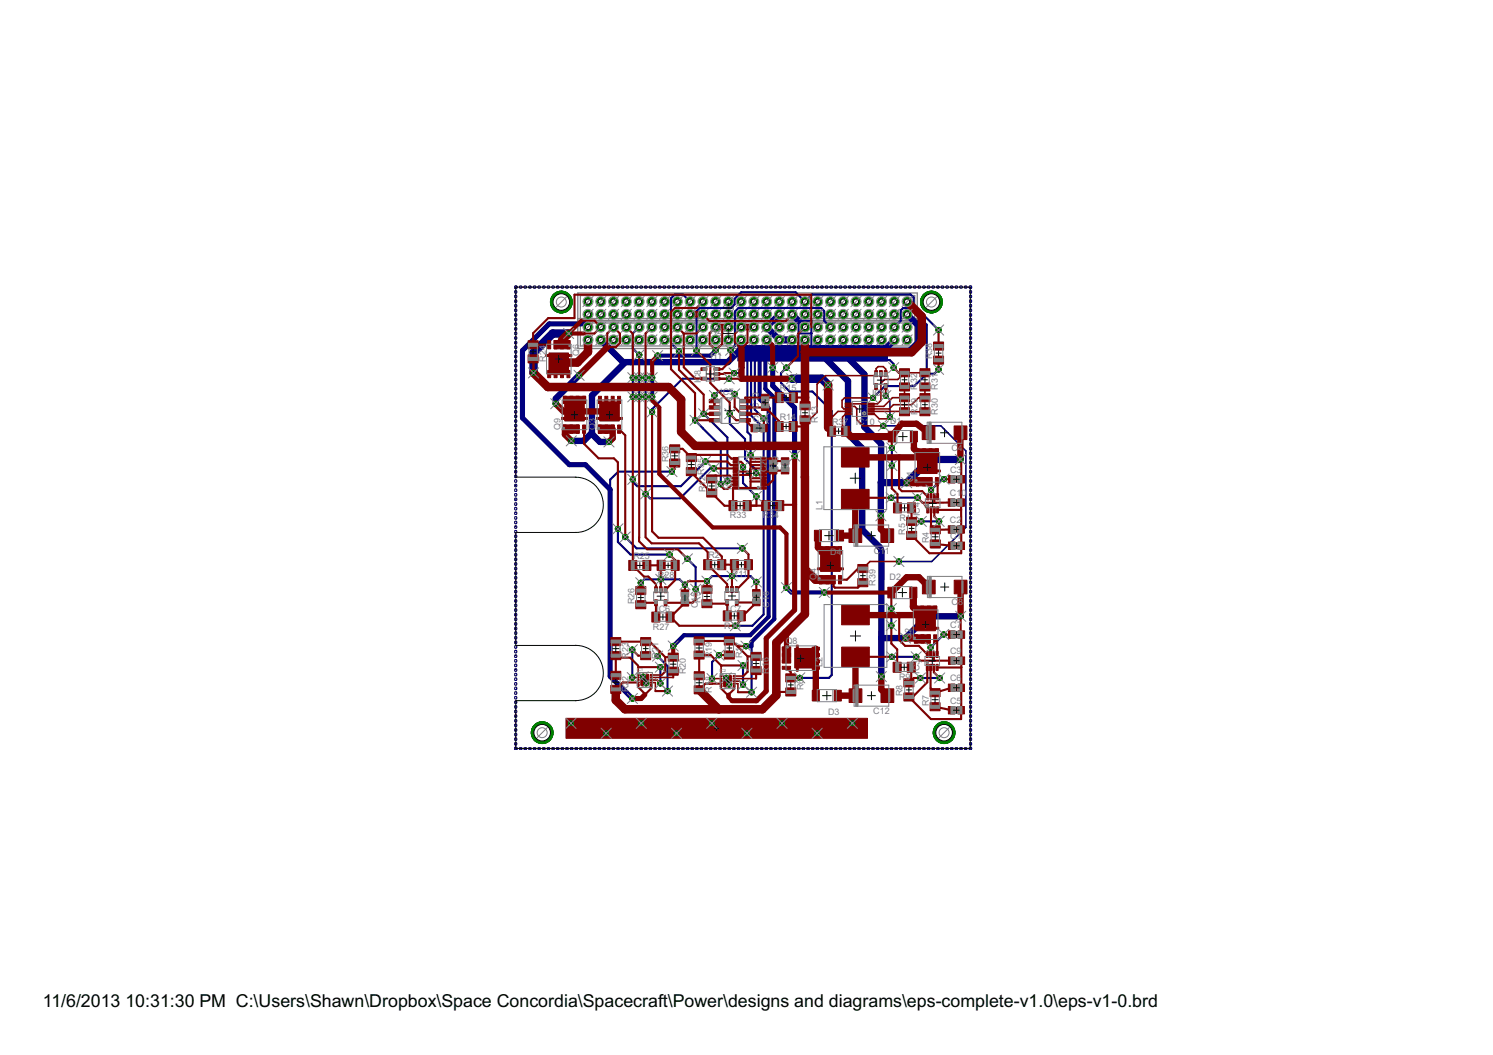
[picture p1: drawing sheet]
<svg xmlns="http://www.w3.org/2000/svg" width="297mm" height="210mm" viewBox="0 0 297 210" stroke-linecap="round" stroke-linejoin="round" font-family="sans-serif">
<defs><g id="words">
<g font-size="4">
<text x="8.5" y="200.4">11/6/2013</text>
<text x="25" y="200.4">10:31:30 PM C:\Users\Shawn\Dropbox\Space Concordia\Spacecraft\Power\designs and diagrams\eps-complete-v1.0\eps-v1-0.brd</text>
</g>
<g font-size="2" fill="#808080">
<text x="115.2" y="70.8" transform="rotate(-90 115.2 70.8)">Q6</text>
<text x="141.4" y="71.4">H1</text>
<text x="141.4" y="66.4">H2</text>
<text x="185.5" y="71.5" transform="rotate(-90 185.5 71.5)">R38</text>
<text x="108.6" y="72" transform="rotate(-90 108.6 72)">R24</text>
<text x="139.4" y="76.3" transform="rotate(-90 139.4 76.3)">IC8</text>
<text x="155.2" y="77.8">R15</text>
<text x="182.5" y="77.6" transform="rotate(-90 182.5 77.6)">R32</text>
<text x="186.6" y="77.6" transform="rotate(-90 186.6 77.6)">R31</text>
<text x="143.3" y="78.5">IC5</text>
<text x="149.7" y="83.9">C14</text>
<text x="151" y="81.3" transform="rotate(-90 151 81.3)">C1</text>
<text x="151" y="79" transform="rotate(-90 151 79)">3</text>
<text x="155.1" y="83.6">R14</text>
<text x="173.5" y="78.8">IC</text>
<text x="175.3" y="78.8">11</text>
<text x="182.5" y="82.5" transform="rotate(-90 182.5 82.5)">R29</text>
<text x="186.6" y="82.5" transform="rotate(-90 186.6 82.5)">R30</text>
<text x="111.5" y="85.5" transform="rotate(-90 111.5 85.5)">Q9</text>
<text x="118.5" y="85.5" transform="rotate(-90 118.5 85.5)">Q3</text>
<text x="162.7" y="84.1" transform="rotate(-90 162.7 84.1)">R13</text>
<text x="165.6" y="84.5">R3</text>
<text x="167.8" y="84.5">7</text>
<text x="170.3" y="84.5">IC</text>
<text x="172.1" y="84.5">10</text>
<text x="177.1" y="84.3">D1</text>
<text x="189.3" y="89.7">C4</text>
<text x="133" y="92" transform="rotate(-90 133 92)">R36</text>
<text x="152.5" y="94" transform="rotate(-90 152.5 94)">C20</text>
<text x="154.9" y="94" transform="rotate(-90 154.9 94)">C1</text>
<text x="154.9" y="91.7" transform="rotate(-90 154.9 91.7)">9</text>
<text x="181.7" y="96" transform="rotate(-90 181.7 96)">Q1</text>
<text x="189" y="94.1">C3</text>
<text x="140.3" y="98" transform="rotate(-90 140.3 98)">R12R35</text>
<text x="145.6" y="97.5" transform="rotate(-90 145.6 97.5)">IC9</text>
<text x="163.6" y="101.4" transform="rotate(-90 163.6 101.4)">L1</text>
<text x="189" y="98.7">C1</text>
<text x="191.3" y="98.7">0</text>
<text x="145.2" y="103.1">R33</text>
<text x="151.7" y="103.2">R</text>
<text x="153" y="103.2">34</text>
<text x="178.9" y="103.6">R1</text>
<text x="180.1" y="106.4" transform="rotate(-90 180.1 106.4)">R5</text>
<text x="183" y="102.7" transform="rotate(-90 183 102.7)">IC4</text>
<text x="189" y="104.1">C2</text>
<text x="189" y="107.3">C1</text>
<text x="126" y="111.2">R25</text>
<text x="140.9" y="111.1">R2</text>
<text x="165.2" y="110.4">D4</text>
<text x="173.8" y="110.1">C11</text>
<text x="184.8" y="108.1" transform="rotate(-90 184.8 108.1)">R4</text>
<text x="130.9" y="115">R28</text>
<text x="139.4" y="120" transform="rotate(-90 139.4 120)">R3</text>
<text x="145.6" y="114.9">R11</text>
<text x="162.4" y="115.5" transform="rotate(-90 162.4 115.5)">Q4</text>
<text x="174.2" y="116.5" transform="rotate(-90 174.2 116.5)">R39</text>
<text x="177" y="115.4">D2</text>
<text x="126.2" y="120.2" transform="rotate(-90 126.2 120.2)">R26</text>
<text x="129.9" y="125.3">R27</text>
<text x="130.6" y="121.8">I</text>
<text x="131.1" y="121.8">C6</text>
<text x="138.8" y="121" transform="rotate(-90 138.8 121)">C15</text>
<text x="144.1" y="125.1">R10</text>
<text x="144.8" y="121.7">I</text>
<text x="145.2" y="121.7">C7</text>
<text x="153" y="120.9" transform="rotate(-90 153 120.9)">C16</text>
<text x="189" y="125">C7</text>
<text x="189.3" y="120.4">C8</text>
<text x="125.1" y="131.1" transform="rotate(-90 125.1 131.1)">R23</text>
<text x="131" y="131.1" transform="rotate(-90 131 131.1)">R21</text>
<text x="141.6" y="130.9" transform="rotate(-90 141.6 130.9)">R19</text>
<text x="147.6" y="130.9" transform="rotate(-90 147.6 130.9)">R17</text>
<text x="156.3" y="128.2">Q8</text>
<text x="181.4" y="127.3" transform="rotate(-90 181.4 127.3)">Q2</text>
<text x="189" y="130.2">C9</text>
<text x="125.1" y="137.8" transform="rotate(-90 125.1 137.8)">R2</text>
<text x="125.1" y="135.5" transform="rotate(-90 125.1 135.5)">2</text>
<text x="136.5" y="134.2" transform="rotate(-90 136.5 134.2)">R20</text>
<text x="141.6" y="137.9" transform="rotate(-90 141.6 137.9)">R1</text>
<text x="141.6" y="135.6" transform="rotate(-90 141.6 135.6)">8</text>
<text x="153" y="134" transform="rotate(-90 153 134)">R16</text>
<text x="159.9" y="137.3" transform="rotate(-90 159.9 137.3)">R6</text>
<text x="163.7" y="132.8" transform="rotate(-90 163.7 132.8)">L2</text>
<text x="178.9" y="135.3">R9</text>
<text x="182.9" y="134" transform="rotate(-90 182.9 134)">IC3</text>
<text x="189" y="135.6">C6</text>
<text x="164.8" y="142.2">D3</text>
<text x="173.7" y="142">C12</text>
<text x="179.6" y="138.5" transform="rotate(-90 179.6 138.5)">R8</text>
<text x="184.8" y="140.5" transform="rotate(-90 184.8 140.5)">R7</text>
<text x="189" y="140">C5</text>
</g>
<g font-size="1" fill="#808080">
<text x="126.7" y="133.5">IC1</text>
<text x="143.2" y="133.8">IC2</text>
</g>
</g></defs>
<path d="M115 58.3h67.5v11h-67.5zM115.5 58.8h66.5v5h-66.5zM115 64.3h67.5M115 63.4h67.5M115.5 63.9h66.5v4.9h-66.5z" fill="none" stroke="#808080" stroke-width=".25"/>
<path d="M146.8 68.7h29.8v3.1h-29.8z" fill="#000080" stroke="#000080" stroke-width=".2"/>
<g fill="none" stroke="#000080" stroke-width=".42">
<path d="M125.9 75.1v3.9M127.1 65.1l-1.2 1.2v3l1.3 1.3M127.2 75.1v3.9M128.4 75.1v3.9M137.3 60l-1.4-1.4h-1.7l-.7 .8v8.9l1.6 1.6M145.1 75.4h-9.3l-6.1 6v.6M146.2 78.4l-.6-.6h-2.6l-.9 .9M147.5 69.3v.4l.4 .4v3.1l-1 1h-.9M147.5 69.3l-.1 .2M148 71.1h1.4v11.6l2.5 2.5v37l-2.2 2.3h-3.4M148.7 71.1v14.9l.6 .6v4M149.5 68.9l.7 .7v11.9l1.7 1.7"/>
<path d="M150.2 69.7l2.1 .1M155.1 67.6h.1M156.5 73.2l-1.1 1v2l1.7 1.7h4.5l3.9 3.9v52.5l-.6 .6h-5.8M158.9 68.9v-5.1h2.5v5.1M158.9 66.4h2.5M161.4 66.3h.1M161.4 68.9h-13.5l-.4 .4M161.4 68.9l1.5 1.5h.4M163.4 70.3h5.1l.7 .8M165.2 65.1l-1.2-1.3v-1.9l-.6-.6h-16.5l-.7 .7v6.8l-.8 .9M172.4 69.8l1.9 1.8h2.7l.8 .8v.8M177.9 65.1l1.3-1.3v-2.1l.5-.4h1.4l3.3 3.3v9.8"/>
<path d="M184.4 74.4l-2.5 2.4h-5.9l-2.3 2.4M186.7 65.7l-4.9-5v-1.5l-.7-.6h-19.5l-1.5 1.4-1.8-1.9h-10.8l-1.3 1.4v1.1l-.8 .7h-6.2l-.6 .6v7.9M186.7 73.5l-.8 .9h-1.5M133.7 93.8h-10.7l-1.6 1.6v2M138.3 83.6l4.9 4.9M140 82.3l4.7 4.7v8.7M140.4 91.8l-4.9 4.9h-8.7l-.9-.8v-.5M142 93.2h-.7l-6 5.9h-6l-.9-.8M143.2 88.5l.2 .3v7.5M143.2 88.5v.1M145.2 82.3v2l3 3.1v3.9l2.3 2.2v.6M147.8 92.9v3.2l2.7 2.7"/>
<path d="M175.2 95.9l.1 .1M175.3 96v.1M176.6 95.9l-1.3 .1M177.3 99h.1M177.3 99h5.2M177.4 89.1v3.5M187.8 95.3l-.4 .1-2.2 2.1M122.9 105.2v2.6l2.6 2.5h7.7M124.4 106.8l2.2 2.3h21.1M127.5 116l.7-.7h7l1.1 1M136.8 111.2l1.6 1.6v4.4M140.7 115.6l1-1h7.6l1.2 1.2"/>
<path d="M175.2 102.6h.1M183.3 103.7h3.5M125.8 129.3v5.5M130.8 130.5l2 2v5M131.4 132.8v3.2M143 130.3l-1.3 1.4v3.3M147.8 132.4v3.8M149.5 128.6v9.1M177.3 121.1v3.4M177.4 130.7h4.9M183.1 134.9h3.8M187.7 126.2l-2.6 2.6"/>
</g>
<path d="M117 65.1l-.7-.7h-7l-5.4 5.3v13.4l9.4 9.4h3.2l4.9 4.9v37.2l4.4 4.4M153.7 73.1v3.7l4.4 4.3v9.6" fill="none" stroke="#000080" stroke-width="1"/>
<g fill="none" stroke="#000080" stroke-width="1.3">
<path d="M115.2 74.7l-4.6 4.6v1M119.5 67.6l4.5 4.5h20.8l2.6-2.6M124.4 72.1l-6.6 6.6v7.6l1.6 1.6h1.8M155.1 62.5l-2.6 2.6 2.6 2.5M157.6 62.5l1.3 1.3M162.7 67.6v1.5l1 1M163.3 70.4l5.4 5.4v10.6l2.8 2.8 .1 16.2 3.4 3.5 .3 .6v17.5M163.3 70.4h4.6l4.1 4.1v10.5l3.3 3.3v7.6M163.7 70.1l-.4 .3M164 69.8l-.3 .3M164.4 69.4l-.4 .4M167.8 67.6v1.8l.3 .4"/>
<path d="M172.8 67.6l.1 2.2M177.9 67.6l-2.1 2.2M180.5 62.5l2.2 2.3v3.3l-1.7 1.7h-17M117.8 86.1l-1.7 1.6h-2.4M175.2 95.9v6.7M175.3 127v7.6M191.1 122.6h-6.6l-4.4 4.4h-4.8"/>
</g>
<path d="M155.1 67.6h2.5M191.1 91.4h-6.1l-4.6 4.6h-5.1" fill="none" stroke="#000080" stroke-width="1.4"/>
<path d="M129.8 75.1v3.9M142.4 69.7l-1.1 1.1h-10.5M151.1 69.8v9.6l1.8 1.8v41.5l-3.7 3.7h-13.1l-2.2 2.1M152.3 69.8v7.6l1.8 1.7v44.1l-4.6 4.5v.9h-1.1M156.5 116.9l.9 1h6.6" fill="none" stroke="#000080" stroke-width=".83"/>
<path d="M125.5 72.1h.3M125.8 72.1h.1M176.2 78.7l.9 .8v3.5M175.7 84.7h11.5l5 5v15.2l-6.8 6.8h-6.6" fill="none" stroke="#000080" stroke-width=".32"/>
<path d="M113.1 66.4h-3.1l-3.8 3.8v4M157.5 75.4h6l1.3 1.2" fill="none" stroke="#000080" stroke-width="1.7"/>
<circle cx="117" cy="62.5" r=".76" fill="#008000" stroke="#008000" stroke-width=".2"/>
<circle cx="117" cy="62.5" r=".51" fill="#fff" stroke="#000" stroke-width=".2"/>
<circle cx="117" cy="60" r=".76" fill="#008000" stroke="#008000" stroke-width=".2"/>
<circle cx="117" cy="60" r=".51" fill="#fff" stroke="#000" stroke-width=".2"/>
<circle cx="119.5" cy="62.5" r=".76" fill="#008000" stroke="#008000" stroke-width=".2"/>
<circle cx="119.5" cy="62.5" r=".51" fill="#fff" stroke="#000" stroke-width=".2"/>
<circle cx="119.5" cy="60" r=".76" fill="#008000" stroke="#008000" stroke-width=".2"/>
<circle cx="119.5" cy="60" r=".51" fill="#fff" stroke="#000" stroke-width=".2"/>
<circle cx="122.1" cy="62.5" r=".76" fill="#008000" stroke="#008000" stroke-width=".2"/>
<circle cx="122.1" cy="62.5" r=".51" fill="#fff" stroke="#000" stroke-width=".2"/>
<circle cx="122.1" cy="60" r=".76" fill="#008000" stroke="#008000" stroke-width=".2"/>
<circle cx="122.1" cy="60" r=".51" fill="#fff" stroke="#000" stroke-width=".2"/>
<circle cx="124.6" cy="62.5" r=".76" fill="#008000" stroke="#008000" stroke-width=".2"/>
<circle cx="124.6" cy="62.5" r=".51" fill="#fff" stroke="#000" stroke-width=".2"/>
<circle cx="124.6" cy="60" r=".76" fill="#008000" stroke="#008000" stroke-width=".2"/>
<circle cx="124.6" cy="60" r=".51" fill="#fff" stroke="#000" stroke-width=".2"/>
<circle cx="127.1" cy="62.5" r=".76" fill="#008000" stroke="#008000" stroke-width=".2"/>
<circle cx="127.1" cy="62.5" r=".51" fill="#fff" stroke="#000" stroke-width=".2"/>
<circle cx="127.1" cy="60" r=".76" fill="#008000" stroke="#008000" stroke-width=".2"/>
<circle cx="127.1" cy="60" r=".51" fill="#fff" stroke="#000" stroke-width=".2"/>
<circle cx="129.7" cy="62.5" r=".76" fill="#008000" stroke="#008000" stroke-width=".2"/>
<circle cx="129.7" cy="62.5" r=".51" fill="#fff" stroke="#000" stroke-width=".2"/>
<circle cx="129.7" cy="60" r=".76" fill="#008000" stroke="#008000" stroke-width=".2"/>
<circle cx="129.7" cy="60" r=".51" fill="#fff" stroke="#000" stroke-width=".2"/>
<circle cx="132.2" cy="62.5" r=".76" fill="#008000" stroke="#008000" stroke-width=".2"/>
<circle cx="132.2" cy="62.5" r=".51" fill="#fff" stroke="#000" stroke-width=".2"/>
<circle cx="132.2" cy="60" r=".76" fill="#008000" stroke="#008000" stroke-width=".2"/>
<circle cx="132.2" cy="60" r=".51" fill="#fff" stroke="#000" stroke-width=".2"/>
<circle cx="134.8" cy="62.5" r=".76" fill="#008000" stroke="#008000" stroke-width=".2"/>
<circle cx="134.8" cy="62.5" r=".51" fill="#fff" stroke="#000" stroke-width=".2"/>
<circle cx="134.8" cy="60" r=".76" fill="#008000" stroke="#008000" stroke-width=".2"/>
<circle cx="134.8" cy="60" r=".51" fill="#fff" stroke="#000" stroke-width=".2"/>
<circle cx="137.3" cy="62.5" r=".76" fill="#008000" stroke="#008000" stroke-width=".2"/>
<circle cx="137.3" cy="62.5" r=".51" fill="#fff" stroke="#000" stroke-width=".2"/>
<circle cx="137.3" cy="60" r=".76" fill="#008000" stroke="#008000" stroke-width=".2"/>
<circle cx="137.3" cy="60" r=".51" fill="#fff" stroke="#000" stroke-width=".2"/>
<circle cx="139.8" cy="62.5" r=".76" fill="#008000" stroke="#008000" stroke-width=".2"/>
<circle cx="139.8" cy="62.5" r=".51" fill="#fff" stroke="#000" stroke-width=".2"/>
<circle cx="139.8" cy="60" r=".76" fill="#008000" stroke="#008000" stroke-width=".2"/>
<circle cx="139.8" cy="60" r=".51" fill="#fff" stroke="#000" stroke-width=".2"/>
<circle cx="142.4" cy="62.5" r=".76" fill="#008000" stroke="#008000" stroke-width=".2"/>
<circle cx="142.4" cy="62.5" r=".51" fill="#fff" stroke="#000" stroke-width=".2"/>
<circle cx="142.4" cy="60" r=".76" fill="#008000" stroke="#008000" stroke-width=".2"/>
<circle cx="142.4" cy="60" r=".51" fill="#fff" stroke="#000" stroke-width=".2"/>
<circle cx="144.9" cy="62.5" r=".76" fill="#008000" stroke="#008000" stroke-width=".2"/>
<circle cx="144.9" cy="62.5" r=".51" fill="#fff" stroke="#000" stroke-width=".2"/>
<circle cx="144.9" cy="60" r=".76" fill="#008000" stroke="#008000" stroke-width=".2"/>
<circle cx="144.9" cy="60" r=".51" fill="#fff" stroke="#000" stroke-width=".2"/>
<circle cx="147.5" cy="62.5" r=".76" fill="#008000" stroke="#008000" stroke-width=".2"/>
<circle cx="147.5" cy="62.5" r=".51" fill="#fff" stroke="#000" stroke-width=".2"/>
<circle cx="147.5" cy="60" r=".76" fill="#008000" stroke="#008000" stroke-width=".2"/>
<circle cx="147.5" cy="60" r=".51" fill="#fff" stroke="#000" stroke-width=".2"/>
<circle cx="150" cy="62.5" r=".76" fill="#008000" stroke="#008000" stroke-width=".2"/>
<circle cx="150" cy="62.5" r=".51" fill="#fff" stroke="#000" stroke-width=".2"/>
<circle cx="150" cy="60" r=".76" fill="#008000" stroke="#008000" stroke-width=".2"/>
<circle cx="150" cy="60" r=".51" fill="#fff" stroke="#000" stroke-width=".2"/>
<circle cx="152.5" cy="62.5" r=".76" fill="#008000" stroke="#008000" stroke-width=".2"/>
<circle cx="152.5" cy="62.5" r=".51" fill="#fff" stroke="#000" stroke-width=".2"/>
<circle cx="152.5" cy="60" r=".76" fill="#008000" stroke="#008000" stroke-width=".2"/>
<circle cx="152.5" cy="60" r=".51" fill="#fff" stroke="#000" stroke-width=".2"/>
<circle cx="155.1" cy="62.5" r=".76" fill="#008000" stroke="#008000" stroke-width=".2"/>
<circle cx="155.1" cy="62.5" r=".51" fill="#fff" stroke="#000" stroke-width=".2"/>
<circle cx="155.1" cy="60" r=".76" fill="#008000" stroke="#008000" stroke-width=".2"/>
<circle cx="155.1" cy="60" r=".51" fill="#fff" stroke="#000" stroke-width=".2"/>
<circle cx="157.6" cy="62.5" r=".76" fill="#008000" stroke="#008000" stroke-width=".2"/>
<circle cx="157.6" cy="62.5" r=".51" fill="#fff" stroke="#000" stroke-width=".2"/>
<circle cx="157.6" cy="60" r=".76" fill="#008000" stroke="#008000" stroke-width=".2"/>
<circle cx="157.6" cy="60" r=".51" fill="#fff" stroke="#000" stroke-width=".2"/>
<circle cx="160.1" cy="62.5" r=".76" fill="#008000" stroke="#008000" stroke-width=".2"/>
<circle cx="160.1" cy="62.5" r=".51" fill="#fff" stroke="#000" stroke-width=".2"/>
<circle cx="160.1" cy="60" r=".76" fill="#008000" stroke="#008000" stroke-width=".2"/>
<circle cx="160.1" cy="60" r=".51" fill="#fff" stroke="#000" stroke-width=".2"/>
<circle cx="162.7" cy="62.5" r=".76" fill="#008000" stroke="#008000" stroke-width=".2"/>
<circle cx="162.7" cy="62.5" r=".51" fill="#fff" stroke="#000" stroke-width=".2"/>
<circle cx="162.7" cy="60" r=".76" fill="#008000" stroke="#008000" stroke-width=".2"/>
<circle cx="162.7" cy="60" r=".51" fill="#fff" stroke="#000" stroke-width=".2"/>
<circle cx="165.2" cy="62.5" r=".76" fill="#008000" stroke="#008000" stroke-width=".2"/>
<circle cx="165.2" cy="62.5" r=".51" fill="#fff" stroke="#000" stroke-width=".2"/>
<circle cx="165.2" cy="60" r=".76" fill="#008000" stroke="#008000" stroke-width=".2"/>
<circle cx="165.2" cy="60" r=".51" fill="#fff" stroke="#000" stroke-width=".2"/>
<circle cx="167.8" cy="62.5" r=".76" fill="#008000" stroke="#008000" stroke-width=".2"/>
<circle cx="167.8" cy="62.5" r=".51" fill="#fff" stroke="#000" stroke-width=".2"/>
<circle cx="167.8" cy="60" r=".76" fill="#008000" stroke="#008000" stroke-width=".2"/>
<circle cx="167.8" cy="60" r=".51" fill="#fff" stroke="#000" stroke-width=".2"/>
<circle cx="170.3" cy="62.5" r=".76" fill="#008000" stroke="#008000" stroke-width=".2"/>
<circle cx="170.3" cy="62.5" r=".51" fill="#fff" stroke="#000" stroke-width=".2"/>
<circle cx="170.3" cy="60" r=".76" fill="#008000" stroke="#008000" stroke-width=".2"/>
<circle cx="170.3" cy="60" r=".51" fill="#fff" stroke="#000" stroke-width=".2"/>
<circle cx="172.8" cy="62.5" r=".76" fill="#008000" stroke="#008000" stroke-width=".2"/>
<circle cx="172.8" cy="62.5" r=".51" fill="#fff" stroke="#000" stroke-width=".2"/>
<circle cx="172.8" cy="60" r=".76" fill="#008000" stroke="#008000" stroke-width=".2"/>
<circle cx="172.8" cy="60" r=".51" fill="#fff" stroke="#000" stroke-width=".2"/>
<circle cx="175.4" cy="62.5" r=".76" fill="#008000" stroke="#008000" stroke-width=".2"/>
<circle cx="175.4" cy="62.5" r=".51" fill="#fff" stroke="#000" stroke-width=".2"/>
<circle cx="175.4" cy="60" r=".76" fill="#008000" stroke="#008000" stroke-width=".2"/>
<circle cx="175.4" cy="60" r=".51" fill="#fff" stroke="#000" stroke-width=".2"/>
<circle cx="177.9" cy="62.5" r=".76" fill="#008000" stroke="#008000" stroke-width=".2"/>
<circle cx="177.9" cy="62.5" r=".51" fill="#fff" stroke="#000" stroke-width=".2"/>
<circle cx="177.9" cy="60" r=".76" fill="#008000" stroke="#008000" stroke-width=".2"/>
<circle cx="177.9" cy="60" r=".51" fill="#fff" stroke="#000" stroke-width=".2"/>
<circle cx="180.5" cy="62.5" r=".76" fill="#008000" stroke="#008000" stroke-width=".2"/>
<circle cx="180.5" cy="62.5" r=".51" fill="#fff" stroke="#000" stroke-width=".2"/>
<circle cx="180.5" cy="60" r=".76" fill="#008000" stroke="#008000" stroke-width=".2"/>
<circle cx="180.5" cy="60" r=".51" fill="#fff" stroke="#000" stroke-width=".2"/>
<circle cx="117" cy="67.6" r=".76" fill="#008000" stroke="#008000" stroke-width=".2"/>
<circle cx="117" cy="67.6" r=".51" fill="#fff" stroke="#000" stroke-width=".2"/>
<circle cx="117" cy="65.1" r=".76" fill="#008000" stroke="#008000" stroke-width=".2"/>
<circle cx="117" cy="65.1" r=".51" fill="#fff" stroke="#000" stroke-width=".2"/>
<circle cx="119.5" cy="67.6" r=".76" fill="#008000" stroke="#008000" stroke-width=".2"/>
<circle cx="119.5" cy="67.6" r=".51" fill="#fff" stroke="#000" stroke-width=".2"/>
<circle cx="119.5" cy="65.1" r=".76" fill="#008000" stroke="#008000" stroke-width=".2"/>
<circle cx="119.5" cy="65.1" r=".51" fill="#fff" stroke="#000" stroke-width=".2"/>
<circle cx="122.1" cy="67.6" r=".76" fill="#008000" stroke="#008000" stroke-width=".2"/>
<circle cx="122.1" cy="67.6" r=".51" fill="#fff" stroke="#000" stroke-width=".2"/>
<circle cx="122.1" cy="65.1" r=".76" fill="#008000" stroke="#008000" stroke-width=".2"/>
<circle cx="122.1" cy="65.1" r=".51" fill="#fff" stroke="#000" stroke-width=".2"/>
<circle cx="124.6" cy="67.6" r=".76" fill="#008000" stroke="#008000" stroke-width=".2"/>
<circle cx="124.6" cy="67.6" r=".51" fill="#fff" stroke="#000" stroke-width=".2"/>
<circle cx="124.6" cy="65.1" r=".76" fill="#008000" stroke="#008000" stroke-width=".2"/>
<circle cx="124.6" cy="65.1" r=".51" fill="#fff" stroke="#000" stroke-width=".2"/>
<circle cx="127.1" cy="67.6" r=".76" fill="#008000" stroke="#008000" stroke-width=".2"/>
<circle cx="127.1" cy="67.6" r=".51" fill="#fff" stroke="#000" stroke-width=".2"/>
<circle cx="127.1" cy="65.1" r=".76" fill="#008000" stroke="#008000" stroke-width=".2"/>
<circle cx="127.1" cy="65.1" r=".51" fill="#fff" stroke="#000" stroke-width=".2"/>
<circle cx="129.7" cy="67.6" r=".76" fill="#008000" stroke="#008000" stroke-width=".2"/>
<circle cx="129.7" cy="67.6" r=".51" fill="#fff" stroke="#000" stroke-width=".2"/>
<circle cx="129.7" cy="65.1" r=".76" fill="#008000" stroke="#008000" stroke-width=".2"/>
<circle cx="129.7" cy="65.1" r=".51" fill="#fff" stroke="#000" stroke-width=".2"/>
<circle cx="132.2" cy="67.6" r=".76" fill="#008000" stroke="#008000" stroke-width=".2"/>
<circle cx="132.2" cy="67.6" r=".51" fill="#fff" stroke="#000" stroke-width=".2"/>
<circle cx="132.2" cy="65.1" r=".76" fill="#008000" stroke="#008000" stroke-width=".2"/>
<circle cx="132.2" cy="65.1" r=".51" fill="#fff" stroke="#000" stroke-width=".2"/>
<circle cx="134.8" cy="67.6" r=".76" fill="#008000" stroke="#008000" stroke-width=".2"/>
<circle cx="134.8" cy="67.6" r=".51" fill="#fff" stroke="#000" stroke-width=".2"/>
<circle cx="134.8" cy="65.1" r=".76" fill="#008000" stroke="#008000" stroke-width=".2"/>
<circle cx="134.8" cy="65.1" r=".51" fill="#fff" stroke="#000" stroke-width=".2"/>
<circle cx="137.3" cy="67.6" r=".76" fill="#008000" stroke="#008000" stroke-width=".2"/>
<circle cx="137.3" cy="67.6" r=".51" fill="#fff" stroke="#000" stroke-width=".2"/>
<circle cx="137.3" cy="65.1" r=".76" fill="#008000" stroke="#008000" stroke-width=".2"/>
<circle cx="137.3" cy="65.1" r=".51" fill="#fff" stroke="#000" stroke-width=".2"/>
<circle cx="139.8" cy="67.6" r=".76" fill="#008000" stroke="#008000" stroke-width=".2"/>
<circle cx="139.8" cy="67.6" r=".51" fill="#fff" stroke="#000" stroke-width=".2"/>
<circle cx="139.8" cy="65.1" r=".76" fill="#008000" stroke="#008000" stroke-width=".2"/>
<circle cx="139.8" cy="65.1" r=".51" fill="#fff" stroke="#000" stroke-width=".2"/>
<circle cx="142.4" cy="67.6" r=".76" fill="#008000" stroke="#008000" stroke-width=".2"/>
<circle cx="142.4" cy="67.6" r=".51" fill="#fff" stroke="#000" stroke-width=".2"/>
<circle cx="142.4" cy="65.1" r=".76" fill="#008000" stroke="#008000" stroke-width=".2"/>
<circle cx="142.4" cy="65.1" r=".51" fill="#fff" stroke="#000" stroke-width=".2"/>
<circle cx="144.9" cy="67.6" r=".76" fill="#008000" stroke="#008000" stroke-width=".2"/>
<circle cx="144.9" cy="67.6" r=".51" fill="#fff" stroke="#000" stroke-width=".2"/>
<circle cx="144.9" cy="65.1" r=".76" fill="#008000" stroke="#008000" stroke-width=".2"/>
<circle cx="144.9" cy="65.1" r=".51" fill="#fff" stroke="#000" stroke-width=".2"/>
<circle cx="147.4" cy="67.6" r=".76" fill="#008000" stroke="#008000" stroke-width=".2"/>
<circle cx="147.4" cy="67.6" r=".51" fill="#fff" stroke="#000" stroke-width=".2"/>
<circle cx="147.4" cy="65.1" r=".76" fill="#008000" stroke="#008000" stroke-width=".2"/>
<circle cx="147.4" cy="65.1" r=".51" fill="#fff" stroke="#000" stroke-width=".2"/>
<circle cx="150" cy="67.6" r=".76" fill="#008000" stroke="#008000" stroke-width=".2"/>
<circle cx="150" cy="67.6" r=".51" fill="#fff" stroke="#000" stroke-width=".2"/>
<circle cx="150" cy="65.1" r=".76" fill="#008000" stroke="#008000" stroke-width=".2"/>
<circle cx="150" cy="65.1" r=".51" fill="#fff" stroke="#000" stroke-width=".2"/>
<circle cx="152.5" cy="67.6" r=".76" fill="#008000" stroke="#008000" stroke-width=".2"/>
<circle cx="152.5" cy="67.6" r=".51" fill="#fff" stroke="#000" stroke-width=".2"/>
<circle cx="152.5" cy="65.1" r=".76" fill="#008000" stroke="#008000" stroke-width=".2"/>
<circle cx="152.5" cy="65.1" r=".51" fill="#fff" stroke="#000" stroke-width=".2"/>
<circle cx="155.1" cy="67.6" r=".76" fill="#008000" stroke="#008000" stroke-width=".2"/>
<circle cx="155.1" cy="67.6" r=".51" fill="#fff" stroke="#000" stroke-width=".2"/>
<circle cx="155.1" cy="65.1" r=".76" fill="#008000" stroke="#008000" stroke-width=".2"/>
<circle cx="155.1" cy="65.1" r=".51" fill="#fff" stroke="#000" stroke-width=".2"/>
<circle cx="157.6" cy="67.6" r=".76" fill="#008000" stroke="#008000" stroke-width=".2"/>
<circle cx="157.6" cy="67.6" r=".51" fill="#fff" stroke="#000" stroke-width=".2"/>
<circle cx="157.6" cy="65.1" r=".76" fill="#008000" stroke="#008000" stroke-width=".2"/>
<circle cx="157.6" cy="65.1" r=".51" fill="#fff" stroke="#000" stroke-width=".2"/>
<circle cx="160.1" cy="67.6" r=".76" fill="#008000" stroke="#008000" stroke-width=".2"/>
<circle cx="160.1" cy="67.6" r=".51" fill="#fff" stroke="#000" stroke-width=".2"/>
<circle cx="160.1" cy="65.1" r=".76" fill="#008000" stroke="#008000" stroke-width=".2"/>
<circle cx="160.1" cy="65.1" r=".51" fill="#fff" stroke="#000" stroke-width=".2"/>
<circle cx="162.7" cy="67.6" r=".76" fill="#008000" stroke="#008000" stroke-width=".2"/>
<circle cx="162.7" cy="67.6" r=".51" fill="#fff" stroke="#000" stroke-width=".2"/>
<circle cx="162.7" cy="65.1" r=".76" fill="#008000" stroke="#008000" stroke-width=".2"/>
<circle cx="162.7" cy="65.1" r=".51" fill="#fff" stroke="#000" stroke-width=".2"/>
<circle cx="165.2" cy="67.6" r=".76" fill="#008000" stroke="#008000" stroke-width=".2"/>
<circle cx="165.2" cy="67.6" r=".51" fill="#fff" stroke="#000" stroke-width=".2"/>
<circle cx="165.2" cy="65.1" r=".76" fill="#008000" stroke="#008000" stroke-width=".2"/>
<circle cx="165.2" cy="65.1" r=".51" fill="#fff" stroke="#000" stroke-width=".2"/>
<circle cx="167.8" cy="67.6" r=".76" fill="#008000" stroke="#008000" stroke-width=".2"/>
<circle cx="167.8" cy="67.6" r=".51" fill="#fff" stroke="#000" stroke-width=".2"/>
<circle cx="167.8" cy="65.1" r=".76" fill="#008000" stroke="#008000" stroke-width=".2"/>
<circle cx="167.8" cy="65.1" r=".51" fill="#fff" stroke="#000" stroke-width=".2"/>
<circle cx="170.3" cy="67.6" r=".76" fill="#008000" stroke="#008000" stroke-width=".2"/>
<circle cx="170.3" cy="67.6" r=".51" fill="#fff" stroke="#000" stroke-width=".2"/>
<circle cx="170.3" cy="65.1" r=".76" fill="#008000" stroke="#008000" stroke-width=".2"/>
<circle cx="170.3" cy="65.1" r=".51" fill="#fff" stroke="#000" stroke-width=".2"/>
<circle cx="172.8" cy="67.6" r=".76" fill="#008000" stroke="#008000" stroke-width=".2"/>
<circle cx="172.8" cy="67.6" r=".51" fill="#fff" stroke="#000" stroke-width=".2"/>
<circle cx="172.8" cy="65.1" r=".76" fill="#008000" stroke="#008000" stroke-width=".2"/>
<circle cx="172.8" cy="65.1" r=".51" fill="#fff" stroke="#000" stroke-width=".2"/>
<circle cx="175.4" cy="67.6" r=".76" fill="#008000" stroke="#008000" stroke-width=".2"/>
<circle cx="175.4" cy="67.6" r=".51" fill="#fff" stroke="#000" stroke-width=".2"/>
<circle cx="175.4" cy="65.1" r=".76" fill="#008000" stroke="#008000" stroke-width=".2"/>
<circle cx="175.4" cy="65.1" r=".51" fill="#fff" stroke="#000" stroke-width=".2"/>
<circle cx="177.9" cy="67.6" r=".76" fill="#008000" stroke="#008000" stroke-width=".2"/>
<circle cx="177.9" cy="67.6" r=".51" fill="#fff" stroke="#000" stroke-width=".2"/>
<circle cx="177.9" cy="65.1" r=".76" fill="#008000" stroke="#008000" stroke-width=".2"/>
<circle cx="177.9" cy="65.1" r=".51" fill="#fff" stroke="#000" stroke-width=".2"/>
<circle cx="180.5" cy="67.6" r=".76" fill="#008000" stroke="#008000" stroke-width=".2"/>
<circle cx="180.5" cy="67.6" r=".51" fill="#fff" stroke="#000" stroke-width=".2"/>
<circle cx="180.5" cy="65.1" r=".76" fill="#008000" stroke="#008000" stroke-width=".2"/>
<circle cx="180.5" cy="65.1" r=".51" fill="#fff" stroke="#000" stroke-width=".2"/>
<circle cx="186.8" cy="103.7" r=".51" fill="#008000" stroke="#008000" stroke-width=".2"/>
<circle cx="186.8" cy="103.7" r=".3" fill="#fff" stroke="#000" stroke-width=".2"/>
<circle cx="183.3" cy="103.7" r=".51" fill="#008000" stroke="#008000" stroke-width=".2"/>
<circle cx="183.3" cy="103.7" r=".3" fill="#fff" stroke="#000" stroke-width=".2"/>
<circle cx="185.1" cy="128.8" r=".51" fill="#008000" stroke="#008000" stroke-width=".2"/>
<circle cx="185.1" cy="128.8" r=".3" fill="#fff" stroke="#000" stroke-width=".2"/>
<circle cx="187.7" cy="126.2" r=".51" fill="#008000" stroke="#008000" stroke-width=".2"/>
<circle cx="187.7" cy="126.2" r=".3" fill="#fff" stroke="#000" stroke-width=".2"/>
<circle cx="186.9" cy="134.9" r=".51" fill="#008000" stroke="#008000" stroke-width=".2"/>
<circle cx="186.9" cy="134.9" r=".3" fill="#fff" stroke="#000" stroke-width=".2"/>
<circle cx="183.1" cy="134.9" r=".51" fill="#008000" stroke="#008000" stroke-width=".2"/>
<circle cx="183.1" cy="134.9" r=".3" fill="#fff" stroke="#000" stroke-width=".2"/>
<circle cx="177.4" cy="130.7" r=".51" fill="#008000" stroke="#008000" stroke-width=".2"/>
<circle cx="177.4" cy="130.7" r=".3" fill="#fff" stroke="#000" stroke-width=".2"/>
<circle cx="182.3" cy="130.7" r=".51" fill="#008000" stroke="#008000" stroke-width=".2"/>
<circle cx="182.3" cy="130.7" r=".3" fill="#fff" stroke="#000" stroke-width=".2"/>
<circle cx="156.5" cy="73.2" r=".51" fill="#008000" stroke="#008000" stroke-width=".2"/>
<circle cx="156.5" cy="73.2" r=".3" fill="#fff" stroke="#000" stroke-width=".2"/>
<circle cx="159.1" cy="134.9" r=".51" fill="#008000" stroke="#008000" stroke-width=".2"/>
<circle cx="159.1" cy="134.9" r=".3" fill="#fff" stroke="#000" stroke-width=".2"/>
<circle cx="145.4" cy="69.7" r=".51" fill="#008000" stroke="#008000" stroke-width=".2"/>
<circle cx="145.4" cy="69.7" r=".3" fill="#fff" stroke="#000" stroke-width=".2"/>
<circle cx="133.7" cy="93.8" r=".51" fill="#008000" stroke="#008000" stroke-width=".2"/>
<circle cx="133.7" cy="93.8" r=".3" fill="#fff" stroke="#000" stroke-width=".2"/>
<circle cx="125.8" cy="139" r=".51" fill="#008000" stroke="#008000" stroke-width=".2"/>
<circle cx="125.8" cy="139" r=".3" fill="#fff" stroke="#000" stroke-width=".2"/>
<circle cx="141.7" cy="135" r=".51" fill="#008000" stroke="#008000" stroke-width=".2"/>
<circle cx="141.7" cy="135" r=".3" fill="#fff" stroke="#000" stroke-width=".2"/>
<circle cx="143" cy="130.3" r=".51" fill="#008000" stroke="#008000" stroke-width=".2"/>
<circle cx="143" cy="130.3" r=".3" fill="#fff" stroke="#000" stroke-width=".2"/>
<circle cx="147.8" cy="136.2" r=".51" fill="#008000" stroke="#008000" stroke-width=".2"/>
<circle cx="147.8" cy="136.2" r=".3" fill="#fff" stroke="#000" stroke-width=".2"/>
<circle cx="147.8" cy="132.4" r=".51" fill="#008000" stroke="#008000" stroke-width=".2"/>
<circle cx="147.8" cy="132.4" r=".3" fill="#fff" stroke="#000" stroke-width=".2"/>
<circle cx="180.4" cy="96" r=".51" fill="#008000" stroke="#008000" stroke-width=".2"/>
<circle cx="180.4" cy="96" r=".3" fill="#fff" stroke="#000" stroke-width=".2"/>
<circle cx="175.3" cy="102.6" r=".51" fill="#008000" stroke="#008000" stroke-width=".2"/>
<circle cx="175.3" cy="102.6" r=".3" fill="#fff" stroke="#000" stroke-width=".2"/>
<circle cx="191.1" cy="91.4" r=".51" fill="#008000" stroke="#008000" stroke-width=".2"/>
<circle cx="191.1" cy="91.4" r=".3" fill="#fff" stroke="#000" stroke-width=".2"/>
<circle cx="151.9" cy="83.2" r=".51" fill="#008000" stroke="#008000" stroke-width=".2"/>
<circle cx="151.9" cy="83.2" r=".3" fill="#fff" stroke="#000" stroke-width=".2"/>
<circle cx="132.8" cy="137.5" r=".51" fill="#008000" stroke="#008000" stroke-width=".2"/>
<circle cx="132.8" cy="137.5" r=".3" fill="#fff" stroke="#000" stroke-width=".2"/>
<circle cx="130.8" cy="130.5" r=".51" fill="#008000" stroke="#008000" stroke-width=".2"/>
<circle cx="130.8" cy="130.5" r=".3" fill="#fff" stroke="#000" stroke-width=".2"/>
<circle cx="149.5" cy="137.7" r=".51" fill="#008000" stroke="#008000" stroke-width=".2"/>
<circle cx="149.5" cy="137.7" r=".3" fill="#fff" stroke="#000" stroke-width=".2"/>
<circle cx="148.4" cy="128.6" r=".51" fill="#008000" stroke="#008000" stroke-width=".2"/>
<circle cx="148.4" cy="128.6" r=".3" fill="#fff" stroke="#000" stroke-width=".2"/>
<circle cx="127.2" cy="70.6" r=".51" fill="#008000" stroke="#008000" stroke-width=".2"/>
<circle cx="127.2" cy="70.6" r=".3" fill="#fff" stroke="#000" stroke-width=".2"/>
<circle cx="127.2" cy="75.1" r=".51" fill="#008000" stroke="#008000" stroke-width=".2"/>
<circle cx="127.2" cy="75.1" r=".3" fill="#fff" stroke="#000" stroke-width=".2"/>
<circle cx="180.1" cy="127" r=".51" fill="#008000" stroke="#008000" stroke-width=".2"/>
<circle cx="180.1" cy="127" r=".3" fill="#fff" stroke="#000" stroke-width=".2"/>
<circle cx="191.1" cy="122.6" r=".51" fill="#008000" stroke="#008000" stroke-width=".2"/>
<circle cx="191.1" cy="122.6" r=".3" fill="#fff" stroke="#000" stroke-width=".2"/>
<circle cx="175.3" cy="134.6" r=".51" fill="#008000" stroke="#008000" stroke-width=".2"/>
<circle cx="175.3" cy="134.6" r=".3" fill="#fff" stroke="#000" stroke-width=".2"/>
<circle cx="133.9" cy="128.5" r=".51" fill="#008000" stroke="#008000" stroke-width=".2"/>
<circle cx="133.9" cy="128.5" r=".3" fill="#fff" stroke="#000" stroke-width=".2"/>
<circle cx="149.3" cy="90.6" r=".51" fill="#008000" stroke="#008000" stroke-width=".2"/>
<circle cx="149.3" cy="90.6" r=".3" fill="#fff" stroke="#000" stroke-width=".2"/>
<circle cx="127.2" cy="79" r=".51" fill="#008000" stroke="#008000" stroke-width=".2"/>
<circle cx="127.2" cy="79" r=".3" fill="#fff" stroke="#000" stroke-width=".2"/>
<circle cx="142.1" cy="78.7" r=".51" fill="#008000" stroke="#008000" stroke-width=".2"/>
<circle cx="142.1" cy="78.7" r=".3" fill="#fff" stroke="#000" stroke-width=".2"/>
<circle cx="146.2" cy="78.4" r=".51" fill="#008000" stroke="#008000" stroke-width=".2"/>
<circle cx="146.2" cy="78.4" r=".3" fill="#fff" stroke="#000" stroke-width=".2"/>
<circle cx="146" cy="74.2" r=".51" fill="#008000" stroke="#008000" stroke-width=".2"/>
<circle cx="146" cy="74.2" r=".3" fill="#fff" stroke="#000" stroke-width=".2"/>
<circle cx="146.3" cy="124.5" r=".51" fill="#008000" stroke="#008000" stroke-width=".2"/>
<circle cx="146.3" cy="124.5" r=".3" fill="#fff" stroke="#000" stroke-width=".2"/>
<circle cx="136.8" cy="111.2" r=".51" fill="#008000" stroke="#008000" stroke-width=".2"/>
<circle cx="136.8" cy="111.2" r=".3" fill="#fff" stroke="#000" stroke-width=".2"/>
<circle cx="138.4" cy="117.2" r=".51" fill="#008000" stroke="#008000" stroke-width=".2"/>
<circle cx="138.4" cy="117.2" r=".3" fill="#fff" stroke="#000" stroke-width=".2"/>
<circle cx="113.7" cy="87.7" r=".51" fill="#008000" stroke="#008000" stroke-width=".2"/>
<circle cx="113.7" cy="87.7" r=".3" fill="#fff" stroke="#000" stroke-width=".2"/>
<circle cx="121.2" cy="87.9" r=".51" fill="#008000" stroke="#008000" stroke-width=".2"/>
<circle cx="121.2" cy="87.9" r=".3" fill="#fff" stroke="#000" stroke-width=".2"/>
<circle cx="177.8" cy="73.2" r=".51" fill="#008000" stroke="#008000" stroke-width=".2"/>
<circle cx="177.8" cy="73.2" r=".3" fill="#fff" stroke="#000" stroke-width=".2"/>
<circle cx="125.8" cy="129.3" r=".51" fill="#008000" stroke="#008000" stroke-width=".2"/>
<circle cx="125.8" cy="129.3" r=".3" fill="#fff" stroke="#000" stroke-width=".2"/>
<circle cx="125.8" cy="134.8" r=".51" fill="#008000" stroke="#008000" stroke-width=".2"/>
<circle cx="125.8" cy="134.8" r=".3" fill="#fff" stroke="#000" stroke-width=".2"/>
<circle cx="131.4" cy="136" r=".51" fill="#008000" stroke="#008000" stroke-width=".2"/>
<circle cx="131.4" cy="136" r=".3" fill="#fff" stroke="#000" stroke-width=".2"/>
<circle cx="131.4" cy="132.7" r=".51" fill="#008000" stroke="#008000" stroke-width=".2"/>
<circle cx="131.4" cy="132.7" r=".3" fill="#fff" stroke="#000" stroke-width=".2"/>
<circle cx="153.7" cy="73.1" r=".51" fill="#008000" stroke="#008000" stroke-width=".2"/>
<circle cx="153.7" cy="73.1" r=".3" fill="#fff" stroke="#000" stroke-width=".2"/>
<circle cx="158.1" cy="90.7" r=".51" fill="#008000" stroke="#008000" stroke-width=".2"/>
<circle cx="158.1" cy="90.7" r=".3" fill="#fff" stroke="#000" stroke-width=".2"/>
<circle cx="142.4" cy="69.7" r=".51" fill="#008000" stroke="#008000" stroke-width=".2"/>
<circle cx="142.4" cy="69.7" r=".3" fill="#fff" stroke="#000" stroke-width=".2"/>
<circle cx="129.8" cy="75.1" r=".51" fill="#008000" stroke="#008000" stroke-width=".2"/>
<circle cx="129.8" cy="75.1" r=".3" fill="#fff" stroke="#000" stroke-width=".2"/>
<circle cx="129.8" cy="79" r=".51" fill="#008000" stroke="#008000" stroke-width=".2"/>
<circle cx="129.8" cy="79" r=".3" fill="#fff" stroke="#000" stroke-width=".2"/>
<circle cx="177.3" cy="121.1" r=".51" fill="#008000" stroke="#008000" stroke-width=".2"/>
<circle cx="177.3" cy="121.1" r=".3" fill="#fff" stroke="#000" stroke-width=".2"/>
<circle cx="177.3" cy="124.5" r=".51" fill="#008000" stroke="#008000" stroke-width=".2"/>
<circle cx="177.3" cy="124.5" r=".3" fill="#fff" stroke="#000" stroke-width=".2"/>
<circle cx="156.5" cy="116.9" r=".51" fill="#008000" stroke="#008000" stroke-width=".2"/>
<circle cx="156.5" cy="116.9" r=".3" fill="#fff" stroke="#000" stroke-width=".2"/>
<circle cx="164" cy="117.9" r=".51" fill="#008000" stroke="#008000" stroke-width=".2"/>
<circle cx="164" cy="117.9" r=".3" fill="#fff" stroke="#000" stroke-width=".2"/>
<circle cx="130.8" cy="70.8" r=".51" fill="#008000" stroke="#008000" stroke-width=".2"/>
<circle cx="130.8" cy="70.8" r=".3" fill="#fff" stroke="#000" stroke-width=".2"/>
<circle cx="157.5" cy="75.4" r=".51" fill="#008000" stroke="#008000" stroke-width=".2"/>
<circle cx="157.5" cy="75.4" r=".3" fill="#fff" stroke="#000" stroke-width=".2"/>
<circle cx="136.3" cy="116.3" r=".51" fill="#008000" stroke="#008000" stroke-width=".2"/>
<circle cx="136.3" cy="116.3" r=".3" fill="#fff" stroke="#000" stroke-width=".2"/>
<circle cx="150.5" cy="115.8" r=".51" fill="#008000" stroke="#008000" stroke-width=".2"/>
<circle cx="150.5" cy="115.8" r=".3" fill="#fff" stroke="#000" stroke-width=".2"/>
<circle cx="145.1" cy="75.4" r=".51" fill="#008000" stroke="#008000" stroke-width=".2"/>
<circle cx="145.1" cy="75.4" r=".3" fill="#fff" stroke="#000" stroke-width=".2"/>
<circle cx="145.6" cy="114.6" r=".51" fill="#008000" stroke="#008000" stroke-width=".2"/>
<circle cx="145.6" cy="114.6" r=".3" fill="#fff" stroke="#000" stroke-width=".2"/>
<circle cx="140.7" cy="115.6" r=".51" fill="#008000" stroke="#008000" stroke-width=".2"/>
<circle cx="140.7" cy="115.6" r=".3" fill="#fff" stroke="#000" stroke-width=".2"/>
<circle cx="131.5" cy="115.3" r=".51" fill="#008000" stroke="#008000" stroke-width=".2"/>
<circle cx="131.5" cy="115.3" r=".3" fill="#fff" stroke="#000" stroke-width=".2"/>
<circle cx="127.5" cy="116" r=".51" fill="#008000" stroke="#008000" stroke-width=".2"/>
<circle cx="127.5" cy="116" r=".3" fill="#fff" stroke="#000" stroke-width=".2"/>
<circle cx="129.7" cy="82" r=".51" fill="#008000" stroke="#008000" stroke-width=".2"/>
<circle cx="129.7" cy="82" r=".3" fill="#fff" stroke="#000" stroke-width=".2"/>
<circle cx="164.8" cy="76.6" r=".51" fill="#008000" stroke="#008000" stroke-width=".2"/>
<circle cx="164.8" cy="76.6" r=".3" fill="#fff" stroke="#000" stroke-width=".2"/>
<circle cx="135.1" cy="69.9" r=".51" fill="#008000" stroke="#008000" stroke-width=".2"/>
<circle cx="135.1" cy="69.9" r=".3" fill="#fff" stroke="#000" stroke-width=".2"/>
<circle cx="140" cy="82.3" r=".51" fill="#008000" stroke="#008000" stroke-width=".2"/>
<circle cx="140" cy="82.3" r=".3" fill="#fff" stroke="#000" stroke-width=".2"/>
<circle cx="144.7" cy="95.7" r=".51" fill="#008000" stroke="#008000" stroke-width=".2"/>
<circle cx="144.7" cy="95.7" r=".3" fill="#fff" stroke="#000" stroke-width=".2"/>
<circle cx="138.3" cy="83.6" r=".51" fill="#008000" stroke="#008000" stroke-width=".2"/>
<circle cx="138.3" cy="83.6" r=".3" fill="#fff" stroke="#000" stroke-width=".2"/>
<circle cx="143.4" cy="96.3" r=".51" fill="#008000" stroke="#008000" stroke-width=".2"/>
<circle cx="143.4" cy="96.3" r=".3" fill="#fff" stroke="#000" stroke-width=".2"/>
<circle cx="125.9" cy="75.1" r=".51" fill="#008000" stroke="#008000" stroke-width=".2"/>
<circle cx="125.9" cy="75.1" r=".3" fill="#fff" stroke="#000" stroke-width=".2"/>
<circle cx="125.9" cy="79" r=".51" fill="#008000" stroke="#008000" stroke-width=".2"/>
<circle cx="125.9" cy="79" r=".3" fill="#fff" stroke="#000" stroke-width=".2"/>
<circle cx="140.4" cy="91.8" r=".51" fill="#008000" stroke="#008000" stroke-width=".2"/>
<circle cx="140.4" cy="91.8" r=".3" fill="#fff" stroke="#000" stroke-width=".2"/>
<circle cx="125.9" cy="95.4" r=".51" fill="#008000" stroke="#008000" stroke-width=".2"/>
<circle cx="125.9" cy="95.4" r=".3" fill="#fff" stroke="#000" stroke-width=".2"/>
<circle cx="133.2" cy="110.3" r=".51" fill="#008000" stroke="#008000" stroke-width=".2"/>
<circle cx="133.2" cy="110.3" r=".3" fill="#fff" stroke="#000" stroke-width=".2"/>
<circle cx="122.9" cy="105.2" r=".51" fill="#008000" stroke="#008000" stroke-width=".2"/>
<circle cx="122.9" cy="105.2" r=".3" fill="#fff" stroke="#000" stroke-width=".2"/>
<circle cx="115.2" cy="74.7" r=".51" fill="#008000" stroke="#008000" stroke-width=".2"/>
<circle cx="115.2" cy="74.7" r=".3" fill="#fff" stroke="#000" stroke-width=".2"/>
<circle cx="110.6" cy="80.3" r=".51" fill="#008000" stroke="#008000" stroke-width=".2"/>
<circle cx="110.6" cy="80.3" r=".3" fill="#fff" stroke="#000" stroke-width=".2"/>
<circle cx="147.7" cy="109.1" r=".51" fill="#008000" stroke="#008000" stroke-width=".2"/>
<circle cx="147.7" cy="109.1" r=".3" fill="#fff" stroke="#000" stroke-width=".2"/>
<circle cx="124.4" cy="106.8" r=".51" fill="#008000" stroke="#008000" stroke-width=".2"/>
<circle cx="124.4" cy="106.8" r=".3" fill="#fff" stroke="#000" stroke-width=".2"/>
<circle cx="128.4" cy="75.1" r=".51" fill="#008000" stroke="#008000" stroke-width=".2"/>
<circle cx="128.4" cy="75.1" r=".3" fill="#fff" stroke="#000" stroke-width=".2"/>
<circle cx="128.4" cy="79" r=".51" fill="#008000" stroke="#008000" stroke-width=".2"/>
<circle cx="128.4" cy="79" r=".3" fill="#fff" stroke="#000" stroke-width=".2"/>
<circle cx="142" cy="93.2" r=".51" fill="#008000" stroke="#008000" stroke-width=".2"/>
<circle cx="142" cy="93.2" r=".3" fill="#fff" stroke="#000" stroke-width=".2"/>
<circle cx="128.4" cy="98.3" r=".51" fill="#008000" stroke="#008000" stroke-width=".2"/>
<circle cx="128.4" cy="98.3" r=".3" fill="#fff" stroke="#000" stroke-width=".2"/>
<circle cx="147.8" cy="92.9" r=".51" fill="#008000" stroke="#008000" stroke-width=".2"/>
<circle cx="147.8" cy="92.9" r=".3" fill="#fff" stroke="#000" stroke-width=".2"/>
<circle cx="150.5" cy="98.8" r=".51" fill="#008000" stroke="#008000" stroke-width=".2"/>
<circle cx="150.5" cy="98.8" r=".3" fill="#fff" stroke="#000" stroke-width=".2"/>
<circle cx="177.1" cy="83" r=".51" fill="#008000" stroke="#008000" stroke-width=".2"/>
<circle cx="177.1" cy="83" r=".3" fill="#fff" stroke="#000" stroke-width=".2"/>
<circle cx="176.2" cy="78.7" r=".51" fill="#008000" stroke="#008000" stroke-width=".2"/>
<circle cx="176.2" cy="78.7" r=".3" fill="#fff" stroke="#000" stroke-width=".2"/>
<circle cx="185.2" cy="97.5" r=".51" fill="#008000" stroke="#008000" stroke-width=".2"/>
<circle cx="185.2" cy="97.5" r=".3" fill="#fff" stroke="#000" stroke-width=".2"/>
<circle cx="187.8" cy="95.3" r=".51" fill="#008000" stroke="#008000" stroke-width=".2"/>
<circle cx="187.8" cy="95.3" r=".3" fill="#fff" stroke="#000" stroke-width=".2"/>
<circle cx="177.3" cy="99" r=".51" fill="#008000" stroke="#008000" stroke-width=".2"/>
<circle cx="177.3" cy="99" r=".3" fill="#fff" stroke="#000" stroke-width=".2"/>
<circle cx="182.5" cy="99" r=".51" fill="#008000" stroke="#008000" stroke-width=".2"/>
<circle cx="182.5" cy="99" r=".3" fill="#fff" stroke="#000" stroke-width=".2"/>
<circle cx="175.7" cy="84.7" r=".51" fill="#008000" stroke="#008000" stroke-width=".2"/>
<circle cx="175.7" cy="84.7" r=".3" fill="#fff" stroke="#000" stroke-width=".2"/>
<circle cx="178.8" cy="111.7" r=".51" fill="#008000" stroke="#008000" stroke-width=".2"/>
<circle cx="178.8" cy="111.7" r=".3" fill="#fff" stroke="#000" stroke-width=".2"/>
<circle cx="138.6" cy="69.8" r=".51" fill="#008000" stroke="#008000" stroke-width=".2"/>
<circle cx="138.6" cy="69.8" r=".3" fill="#fff" stroke="#000" stroke-width=".2"/>
<circle cx="145.2" cy="82.3" r=".51" fill="#008000" stroke="#008000" stroke-width=".2"/>
<circle cx="145.2" cy="82.3" r=".3" fill="#fff" stroke="#000" stroke-width=".2"/>
<circle cx="150.5" cy="94.1" r=".51" fill="#008000" stroke="#008000" stroke-width=".2"/>
<circle cx="150.5" cy="94.1" r=".3" fill="#fff" stroke="#000" stroke-width=".2"/>
<circle cx="186.7" cy="65.7" r=".51" fill="#008000" stroke="#008000" stroke-width=".2"/>
<circle cx="186.7" cy="65.7" r=".3" fill="#fff" stroke="#000" stroke-width=".2"/>
<circle cx="177.4" cy="89.1" r=".51" fill="#008000" stroke="#008000" stroke-width=".2"/>
<circle cx="177.4" cy="89.1" r=".3" fill="#fff" stroke="#000" stroke-width=".2"/>
<circle cx="177.4" cy="92.6" r=".51" fill="#008000" stroke="#008000" stroke-width=".2"/>
<circle cx="177.4" cy="92.6" r=".3" fill="#fff" stroke="#000" stroke-width=".2"/>
<circle cx="106.2" cy="74.2" r=".51" fill="#008000" stroke="#008000" stroke-width=".2"/>
<circle cx="106.2" cy="74.2" r=".3" fill="#fff" stroke="#000" stroke-width=".2"/>
<circle cx="113.1" cy="66.4" r=".51" fill="#008000" stroke="#008000" stroke-width=".2"/>
<circle cx="113.1" cy="66.4" r=".3" fill="#fff" stroke="#000" stroke-width=".2"/>
<circle cx="173.7" cy="79.2" r=".51" fill="#008000" stroke="#008000" stroke-width=".2"/>
<circle cx="173.7" cy="79.2" r=".3" fill="#fff" stroke="#000" stroke-width=".2"/>
<circle cx="186.7" cy="73.5" r=".51" fill="#008000" stroke="#008000" stroke-width=".2"/>
<circle cx="186.7" cy="73.5" r=".3" fill="#fff" stroke="#000" stroke-width=".2"/>
<circle cx="185.3" cy="60.1" r="2.16" fill="#008000" stroke="#008000" stroke-width=".2"/>
<circle cx="185.3" cy="60.1" r="1.65" fill="#fff" stroke="#000" stroke-width=".2"/>
<circle cx="111.7" cy="60.1" r="2.16" fill="#008000" stroke="#008000" stroke-width=".2"/>
<circle cx="111.7" cy="60.1" r="1.65" fill="#fff" stroke="#000" stroke-width=".2"/>
<circle cx="107.9" cy="145.8" r="2.16" fill="#008000" stroke="#008000" stroke-width=".2"/>
<circle cx="107.9" cy="145.8" r="1.65" fill="#fff" stroke="#000" stroke-width=".2"/>
<circle cx="187.8" cy="145.8" r="2.16" fill="#008000" stroke="#008000" stroke-width=".2"/>
<circle cx="187.8" cy="145.8" r="1.65" fill="#fff" stroke="#000" stroke-width=".2"/>
<circle cx="113.6" cy="143.9" r=".51" fill="#008000" stroke="#008000" stroke-width=".2"/>
<circle cx="113.6" cy="143.9" r=".3" fill="#fff" stroke="#000" stroke-width=".2"/>
<circle cx="120.6" cy="145.9" r=".51" fill="#008000" stroke="#008000" stroke-width=".2"/>
<circle cx="120.6" cy="145.9" r=".3" fill="#fff" stroke="#000" stroke-width=".2"/>
<circle cx="127.6" cy="143.9" r=".51" fill="#008000" stroke="#008000" stroke-width=".2"/>
<circle cx="127.6" cy="143.9" r=".3" fill="#fff" stroke="#000" stroke-width=".2"/>
<circle cx="134.6" cy="145.9" r=".51" fill="#008000" stroke="#008000" stroke-width=".2"/>
<circle cx="134.6" cy="145.9" r=".3" fill="#fff" stroke="#000" stroke-width=".2"/>
<circle cx="141.6" cy="143.9" r=".51" fill="#008000" stroke="#008000" stroke-width=".2"/>
<circle cx="141.6" cy="143.9" r=".3" fill="#fff" stroke="#000" stroke-width=".2"/>
<circle cx="148.6" cy="145.9" r=".51" fill="#008000" stroke="#008000" stroke-width=".2"/>
<circle cx="148.6" cy="145.9" r=".3" fill="#fff" stroke="#000" stroke-width=".2"/>
<circle cx="155.6" cy="143.9" r=".51" fill="#008000" stroke="#008000" stroke-width=".2"/>
<circle cx="155.6" cy="143.9" r=".3" fill="#fff" stroke="#000" stroke-width=".2"/>
<circle cx="162.6" cy="145.9" r=".51" fill="#008000" stroke="#008000" stroke-width=".2"/>
<circle cx="162.6" cy="145.9" r=".3" fill="#fff" stroke="#000" stroke-width=".2"/>
<circle cx="169.6" cy="143.9" r=".51" fill="#008000" stroke="#008000" stroke-width=".2"/>
<circle cx="169.6" cy="143.9" r=".3" fill="#fff" stroke="#000" stroke-width=".2"/>
<circle cx="128.6" cy="135.9" r=".51" fill="#008000" stroke="#008000" stroke-width=".2"/>
<circle cx="128.6" cy="135.9" r=".3" fill="#fff" stroke="#000" stroke-width=".2"/>
<circle cx="128" cy="134.7" r=".51" fill="#008000" stroke="#008000" stroke-width=".2"/>
<circle cx="128" cy="134.7" r=".3" fill="#fff" stroke="#000" stroke-width=".2"/>
<circle cx="144.5" cy="134.9" r=".51" fill="#008000" stroke="#008000" stroke-width=".2"/>
<circle cx="144.5" cy="134.9" r=".3" fill="#fff" stroke="#000" stroke-width=".2"/>
<circle cx="145.1" cy="136.2" r=".51" fill="#008000" stroke="#008000" stroke-width=".2"/>
<circle cx="145.1" cy="136.2" r=".3" fill="#fff" stroke="#000" stroke-width=".2"/>
<g fill="#800000" stroke="#800000" stroke-width=".2">
<circle cx="102.6" cy="57.2" r=".25"/>
<circle cx="102.6" cy="58.1" r=".25"/>
<circle cx="102.6" cy="59" r=".25"/>
<circle cx="102.6" cy="59.9" r=".25"/>
<circle cx="102.6" cy="60.8" r=".25"/>
<circle cx="102.6" cy="61.7" r=".25"/>
<circle cx="102.6" cy="62.7" r=".25"/>
<circle cx="102.6" cy="63.6" r=".25"/>
<circle cx="102.6" cy="64.5" r=".25"/>
<circle cx="102.6" cy="65.4" r=".25"/>
<circle cx="102.6" cy="66.3" r=".25"/>
<circle cx="102.6" cy="67.2" r=".25"/>
<circle cx="102.6" cy="68.2" r=".25"/>
<circle cx="102.6" cy="69.1" r=".25"/>
<circle cx="102.6" cy="70" r=".25"/>
<circle cx="102.6" cy="70.9" r=".25"/>
<circle cx="102.6" cy="71.8" r=".25"/>
<circle cx="102.6" cy="72.7" r=".25"/>
<circle cx="102.6" cy="73.7" r=".25"/>
<circle cx="102.6" cy="74.6" r=".25"/>
<circle cx="102.6" cy="75.5" r=".24"/>
<circle cx="102.6" cy="76.4" r=".25"/>
<circle cx="102.6" cy="77.3" r=".25"/>
<circle cx="102.6" cy="78.3" r=".24"/>
<circle cx="102.6" cy="79.2" r=".25"/>
<circle cx="102.6" cy="80.1" r=".25"/>
<circle cx="102.6" cy="81" r=".24"/>
<circle cx="102.6" cy="81.9" r=".25"/>
<circle cx="102.6" cy="82.8" r=".25"/>
<circle cx="102.6" cy="83.8" r=".24"/>
<circle cx="102.6" cy="84.7" r=".25"/>
<circle cx="102.6" cy="85.6" r=".25"/>
<circle cx="102.6" cy="86.5" r=".25"/>
<circle cx="102.6" cy="87.4" r=".25"/>
<circle cx="102.6" cy="88.3" r=".25"/>
<circle cx="102.6" cy="89.3" r=".25"/>
<circle cx="102.6" cy="90.2" r=".25"/>
<circle cx="102.6" cy="91.1" r=".25"/>
<circle cx="102.6" cy="92" r=".25"/>
<circle cx="102.6" cy="92.9" r=".25"/>
<circle cx="102.6" cy="93.9" r=".25"/>
<circle cx="102.6" cy="94.8" r=".25"/>
<circle cx="102.6" cy="95.7" r=".25"/>
<circle cx="102.6" cy="96.6" r=".25"/>
<circle cx="102.6" cy="97.5" r=".25"/>
<circle cx="102.6" cy="98.4" r=".25"/>
<circle cx="102.6" cy="99.4" r=".25"/>
<circle cx="102.6" cy="100.3" r=".25"/>
<circle cx="102.6" cy="101.2" r=".25"/>
<circle cx="102.6" cy="102.1" r=".25"/>
<circle cx="102.6" cy="103" r=".25"/>
<circle cx="102.6" cy="103.9" r=".25"/>
<circle cx="102.6" cy="104.9" r=".25"/>
<circle cx="102.6" cy="105.8" r=".25"/>
<circle cx="102.6" cy="106.7" r=".25"/>
<circle cx="102.6" cy="107.6" r=".25"/>
<circle cx="102.6" cy="108.5" r=".25"/>
<circle cx="102.6" cy="109.5" r=".25"/>
<circle cx="102.6" cy="110.4" r=".25"/>
<circle cx="102.6" cy="111.3" r=".25"/>
<circle cx="102.6" cy="112.2" r=".25"/>
<circle cx="102.6" cy="113.1" r=".25"/>
<circle cx="102.6" cy="114" r=".25"/>
<circle cx="102.6" cy="115" r=".25"/>
<circle cx="102.6" cy="115.9" r=".25"/>
<circle cx="102.6" cy="116.8" r=".25"/>
<circle cx="102.6" cy="117.7" r=".25"/>
<circle cx="102.6" cy="118.6" r=".25"/>
<circle cx="102.6" cy="119.5" r=".25"/>
<circle cx="102.6" cy="120.5" r=".25"/>
<circle cx="102.6" cy="121.4" r=".25"/>
<circle cx="102.6" cy="122.3" r=".25"/>
<circle cx="102.6" cy="123.2" r=".25"/>
<circle cx="102.6" cy="124.1" r=".25"/>
<circle cx="102.6" cy="125.1" r=".25"/>
<circle cx="102.6" cy="126" r=".25"/>
<circle cx="102.6" cy="126.9" r=".25"/>
<circle cx="102.6" cy="127.8" r=".25"/>
<circle cx="102.6" cy="128.7" r=".25"/>
<circle cx="102.6" cy="129.6" r=".25"/>
<circle cx="102.6" cy="130.6" r=".25"/>
<circle cx="102.6" cy="131.5" r=".25"/>
<circle cx="102.6" cy="132.4" r=".25"/>
<circle cx="102.6" cy="133.3" r=".25"/>
<circle cx="102.6" cy="134.2" r=".25"/>
<circle cx="102.6" cy="135.1" r=".25"/>
<circle cx="102.6" cy="136.1" r=".25"/>
<circle cx="102.6" cy="137" r=".25"/>
<circle cx="102.6" cy="137.9" r=".25"/>
<circle cx="102.6" cy="138.8" r=".25"/>
<circle cx="102.6" cy="139.7" r=".25"/>
<circle cx="102.6" cy="140.6" r=".25"/>
<circle cx="102.6" cy="141.6" r=".25"/>
<circle cx="102.6" cy="142.5" r=".25"/>
<circle cx="102.6" cy="143.4" r=".25"/>
<circle cx="102.6" cy="144.3" r=".25"/>
<circle cx="102.6" cy="145.2" r=".25"/>
<circle cx="102.6" cy="146.1" r=".25"/>
<circle cx="102.6" cy="147.1" r=".25"/>
<circle cx="102.6" cy="148" r=".25"/>
<circle cx="102.6" cy="148.9" r=".25"/>
<circle cx="102.7" cy="149" r=".25"/>
<circle cx="103.6" cy="149" r=".25"/>
<circle cx="104.5" cy="149" r=".25"/>
<circle cx="105.4" cy="149" r=".25"/>
<circle cx="106.4" cy="149" r=".26"/>
<circle cx="107.3" cy="149" r=".25"/>
<circle cx="108.2" cy="149" r=".26"/>
<circle cx="109.1" cy="149" r=".25"/>
<circle cx="110" cy="149" r=".25"/>
<circle cx="111" cy="149" r=".25"/>
<circle cx="111.9" cy="149" r=".25"/>
<circle cx="112.8" cy="149" r=".25"/>
<circle cx="113.7" cy="149" r=".25"/>
<circle cx="114.6" cy="149" r=".26"/>
<circle cx="115.6" cy="149" r=".25"/>
<circle cx="116.5" cy="149" r=".25"/>
<circle cx="117.4" cy="149" r=".25"/>
<circle cx="118.3" cy="149" r=".25"/>
<circle cx="119.3" cy="149" r=".25"/>
<circle cx="120.2" cy="149" r=".25"/>
<circle cx="121.1" cy="149" r=".26"/>
<circle cx="122" cy="149" r=".25"/>
<circle cx="123" cy="149" r=".25"/>
<circle cx="123.9" cy="149" r=".25"/>
<circle cx="124.8" cy="149" r=".25"/>
<circle cx="125.7" cy="149" r=".25"/>
<circle cx="126.6" cy="149" r=".25"/>
<circle cx="127.6" cy="149" r=".26"/>
<circle cx="128.5" cy="149" r=".25"/>
<circle cx="129.4" cy="149" r=".26"/>
<circle cx="130.3" cy="149" r=".25"/>
<circle cx="131.3" cy="149" r=".25"/>
<circle cx="132.2" cy="149" r=".25"/>
<circle cx="133.1" cy="149" r=".25"/>
<circle cx="134" cy="149" r=".26"/>
<circle cx="134.9" cy="149" r=".25"/>
<circle cx="135.9" cy="149" r=".26"/>
<circle cx="136.8" cy="149" r=".25"/>
<circle cx="137.7" cy="149" r=".25"/>
<circle cx="138.6" cy="149" r=".25"/>
<circle cx="139.6" cy="149" r=".25"/>
<circle cx="140.5" cy="149" r=".25"/>
<circle cx="141.4" cy="149" r=".25"/>
<circle cx="142.3" cy="149" r=".26"/>
<circle cx="143.2" cy="149" r=".25"/>
<circle cx="144.2" cy="149" r=".25"/>
<circle cx="145.1" cy="149" r=".25"/>
<circle cx="146" cy="149" r=".25"/>
<circle cx="146.9" cy="149" r=".25"/>
<circle cx="147.8" cy="149" r=".25"/>
<circle cx="148.8" cy="149" r=".26"/>
<circle cx="149.7" cy="149" r=".25"/>
<circle cx="150.6" cy="149" r=".25"/>
<circle cx="151.5" cy="149" r=".25"/>
<circle cx="152.5" cy="149" r=".25"/>
<circle cx="153.4" cy="149" r=".25"/>
<circle cx="154.3" cy="149" r=".25"/>
<circle cx="155.2" cy="149" r=".26"/>
<circle cx="156.1" cy="149" r=".25"/>
<circle cx="157.1" cy="149" r=".26"/>
<circle cx="158" cy="149" r=".25"/>
<circle cx="158.9" cy="149" r=".25"/>
<circle cx="159.8" cy="149" r=".25"/>
<circle cx="160.8" cy="149" r=".25"/>
<circle cx="161.7" cy="149" r=".26"/>
<circle cx="162.6" cy="149" r=".25"/>
<circle cx="163.5" cy="149" r=".26"/>
<circle cx="164.4" cy="149" r=".25"/>
<circle cx="165.4" cy="149" r=".25"/>
<circle cx="166.3" cy="149" r=".25"/>
<circle cx="167.2" cy="149" r=".25"/>
<circle cx="168.1" cy="149" r=".25"/>
<circle cx="169.1" cy="149" r=".25"/>
<circle cx="170" cy="149" r=".26"/>
<circle cx="170.9" cy="149" r=".25"/>
<circle cx="171.8" cy="149" r=".25"/>
<circle cx="172.7" cy="149" r=".25"/>
<circle cx="173.7" cy="149" r=".25"/>
<circle cx="174.6" cy="149" r=".25"/>
<circle cx="175.5" cy="149" r=".25"/>
<circle cx="176.4" cy="149" r=".26"/>
<circle cx="177.4" cy="149" r=".25"/>
<circle cx="178.3" cy="149" r=".25"/>
<circle cx="179.2" cy="149" r=".25"/>
<circle cx="180.1" cy="149" r=".25"/>
<circle cx="181" cy="149" r=".25"/>
<circle cx="182" cy="149" r=".25"/>
<circle cx="182.9" cy="149" r=".26"/>
<circle cx="183.8" cy="149" r=".25"/>
<circle cx="184.7" cy="149" r=".26"/>
<circle cx="185.7" cy="149" r=".25"/>
<circle cx="186.6" cy="149" r=".25"/>
<circle cx="187.5" cy="149" r=".25"/>
<circle cx="188.4" cy="149" r=".25"/>
<circle cx="189.3" cy="149" r=".26"/>
<circle cx="190.3" cy="149" r=".25"/>
<circle cx="191.2" cy="149" r=".26"/>
<circle cx="192.1" cy="149" r=".25"/>
<circle cx="193" cy="149" r=".25"/>
<circle cx="193.1" cy="148.9" r=".25"/>
<circle cx="193.1" cy="148" r=".25"/>
<circle cx="193.1" cy="147.1" r=".25"/>
<circle cx="193.1" cy="146.1" r=".25"/>
<circle cx="193.1" cy="145.2" r=".25"/>
<circle cx="193.1" cy="144.3" r=".25"/>
<circle cx="193.1" cy="143.4" r=".25"/>
<circle cx="193.1" cy="142.5" r=".25"/>
<circle cx="193.1" cy="141.6" r=".25"/>
<circle cx="193.1" cy="140.6" r=".25"/>
<circle cx="193.1" cy="139.7" r=".25"/>
<circle cx="193.1" cy="138.8" r=".25"/>
<circle cx="193.1" cy="137.9" r=".25"/>
<circle cx="193.1" cy="137" r=".25"/>
<circle cx="193.1" cy="136.1" r=".25"/>
<circle cx="193.1" cy="135.1" r=".25"/>
<circle cx="193.1" cy="134.2" r=".25"/>
<circle cx="193.1" cy="133.3" r=".25"/>
<circle cx="193.1" cy="132.4" r=".25"/>
<circle cx="193.1" cy="131.5" r=".25"/>
<circle cx="193.1" cy="130.6" r=".25"/>
<circle cx="193.1" cy="129.6" r=".25"/>
<circle cx="193.1" cy="128.7" r=".25"/>
<circle cx="193.1" cy="127.8" r=".25"/>
<circle cx="193.1" cy="126.9" r=".25"/>
<circle cx="193.1" cy="126" r=".25"/>
<circle cx="193.1" cy="125.1" r=".25"/>
<circle cx="193.1" cy="124.1" r=".25"/>
<circle cx="193.1" cy="123.2" r=".25"/>
<circle cx="193.1" cy="122.3" r=".25"/>
<circle cx="193.1" cy="121.4" r=".25"/>
<circle cx="193.1" cy="120.5" r=".25"/>
<circle cx="193.1" cy="119.5" r=".25"/>
<circle cx="193.1" cy="118.6" r=".25"/>
<circle cx="193.1" cy="117.7" r=".25"/>
<circle cx="193.1" cy="116.8" r=".25"/>
<circle cx="193.1" cy="115.9" r=".25"/>
<circle cx="193.1" cy="115" r=".25"/>
<circle cx="193.1" cy="114" r=".25"/>
<circle cx="193.1" cy="113.1" r=".25"/>
<circle cx="193.1" cy="112.2" r=".25"/>
<circle cx="193.1" cy="111.3" r=".25"/>
<circle cx="193.1" cy="110.4" r=".25"/>
<circle cx="193.1" cy="109.5" r=".25"/>
<circle cx="193.1" cy="108.5" r=".25"/>
<circle cx="193.1" cy="107.6" r=".25"/>
<circle cx="193.1" cy="106.7" r=".25"/>
<circle cx="193.1" cy="105.8" r=".25"/>
<circle cx="193.1" cy="104.9" r=".25"/>
<circle cx="193.1" cy="103.9" r=".25"/>
<circle cx="193.1" cy="103" r=".25"/>
<circle cx="193.1" cy="102.1" r=".25"/>
<circle cx="193.1" cy="101.2" r=".25"/>
<circle cx="193.1" cy="100.3" r=".25"/>
<circle cx="193.1" cy="99.4" r=".25"/>
<circle cx="193.1" cy="98.4" r=".25"/>
<circle cx="193.1" cy="97.5" r=".25"/>
<circle cx="193.1" cy="96.6" r=".25"/>
<circle cx="193.1" cy="95.7" r=".25"/>
<circle cx="193.1" cy="94.8" r=".25"/>
<circle cx="193.1" cy="93.9" r=".25"/>
<circle cx="193.1" cy="92.9" r=".25"/>
<circle cx="193.1" cy="92" r=".25"/>
<circle cx="193.1" cy="91.1" r=".25"/>
<circle cx="193.1" cy="90.2" r=".25"/>
<circle cx="193.1" cy="89.3" r=".25"/>
<circle cx="193.1" cy="88.3" r=".25"/>
<circle cx="193.1" cy="87.4" r=".25"/>
<circle cx="193.1" cy="86.5" r=".25"/>
<circle cx="193.1" cy="85.6" r=".25"/>
<circle cx="193.1" cy="84.7" r=".25"/>
<circle cx="193.1" cy="83.8" r=".24"/>
<circle cx="193.1" cy="82.8" r=".25"/>
<circle cx="193.1" cy="81.9" r=".25"/>
<circle cx="193.1" cy="81" r=".24"/>
<circle cx="193.1" cy="80.1" r=".25"/>
<circle cx="193.1" cy="79.2" r=".25"/>
<circle cx="193.1" cy="78.3" r=".24"/>
<circle cx="193.1" cy="77.3" r=".25"/>
<circle cx="193.1" cy="76.4" r=".25"/>
<circle cx="193.1" cy="75.5" r=".24"/>
<circle cx="193.1" cy="74.6" r=".25"/>
<circle cx="193.1" cy="73.7" r=".25"/>
<circle cx="193.1" cy="72.7" r=".25"/>
<circle cx="193.1" cy="71.8" r=".25"/>
<circle cx="193.1" cy="70.9" r=".25"/>
<circle cx="193.1" cy="70" r=".25"/>
<circle cx="193.1" cy="69.1" r=".25"/>
<circle cx="193.1" cy="68.2" r=".25"/>
<circle cx="193.1" cy="67.2" r=".25"/>
<circle cx="193.1" cy="66.3" r=".25"/>
<circle cx="193.1" cy="65.4" r=".25"/>
<circle cx="193.1" cy="64.5" r=".25"/>
<circle cx="193.1" cy="63.6" r=".25"/>
<circle cx="193.1" cy="62.7" r=".25"/>
<circle cx="193.1" cy="61.7" r=".25"/>
<circle cx="193.1" cy="60.8" r=".25"/>
<circle cx="193.1" cy="59.9" r=".25"/>
<circle cx="193.1" cy="59" r=".25"/>
<circle cx="193.1" cy="58.1" r=".25"/>
<circle cx="193.1" cy="57.2" r=".25"/>
<circle cx="193" cy="57.1" r=".25"/>
<circle cx="192.1" cy="57.1" r=".25"/>
<circle cx="191.2" cy="57.1" r=".26"/>
<circle cx="190.3" cy="57.1" r=".25"/>
<circle cx="189.3" cy="57.1" r=".26"/>
<circle cx="188.4" cy="57.1" r=".25"/>
<circle cx="187.5" cy="57.1" r=".25"/>
<circle cx="186.6" cy="57.1" r=".25"/>
<circle cx="185.7" cy="57.1" r=".25"/>
<circle cx="184.7" cy="57.1" r=".26"/>
<circle cx="183.8" cy="57.1" r=".25"/>
<circle cx="182.9" cy="57.1" r=".26"/>
<circle cx="182" cy="57.1" r=".25"/>
<circle cx="181" cy="57.1" r=".25"/>
<circle cx="180.1" cy="57.1" r=".25"/>
<circle cx="179.2" cy="57.1" r=".25"/>
<circle cx="178.3" cy="57.1" r=".25"/>
<circle cx="177.4" cy="57.1" r=".25"/>
<circle cx="176.4" cy="57.1" r=".26"/>
<circle cx="175.5" cy="57.1" r=".25"/>
<circle cx="174.6" cy="57.1" r=".25"/>
<circle cx="173.7" cy="57.1" r=".25"/>
<circle cx="172.7" cy="57.1" r=".25"/>
<circle cx="171.8" cy="57.1" r=".25"/>
<circle cx="170.9" cy="57.1" r=".25"/>
<circle cx="170" cy="57.1" r=".26"/>
<circle cx="169.1" cy="57.1" r=".25"/>
<circle cx="168.1" cy="57.1" r=".25"/>
<circle cx="167.2" cy="57.1" r=".25"/>
<circle cx="166.3" cy="57.1" r=".25"/>
<circle cx="165.4" cy="57.1" r=".25"/>
<circle cx="164.4" cy="57.1" r=".25"/>
<circle cx="163.5" cy="57.1" r=".26"/>
<circle cx="162.6" cy="57.1" r=".25"/>
<circle cx="161.7" cy="57.1" r=".26"/>
<circle cx="160.8" cy="57.1" r=".25"/>
<circle cx="159.8" cy="57.1" r=".25"/>
<circle cx="158.9" cy="57.1" r=".25"/>
<circle cx="158" cy="57.1" r=".25"/>
<circle cx="157.1" cy="57.1" r=".26"/>
<circle cx="156.1" cy="57.1" r=".25"/>
<circle cx="155.2" cy="57.1" r=".26"/>
<circle cx="154.3" cy="57.1" r=".25"/>
<circle cx="153.4" cy="57.1" r=".25"/>
<circle cx="152.5" cy="57.1" r=".25"/>
<circle cx="151.5" cy="57.1" r=".25"/>
<circle cx="150.6" cy="57.1" r=".25"/>
<circle cx="149.7" cy="57.1" r=".25"/>
<circle cx="148.8" cy="57.1" r=".26"/>
<circle cx="147.8" cy="57.1" r=".25"/>
<circle cx="146.9" cy="57.1" r=".25"/>
<circle cx="146" cy="57.1" r=".25"/>
<circle cx="145.1" cy="57.1" r=".25"/>
<circle cx="144.2" cy="57.1" r=".25"/>
<circle cx="143.2" cy="57.1" r=".25"/>
<circle cx="142.3" cy="57.1" r=".26"/>
<circle cx="141.4" cy="57.1" r=".25"/>
<circle cx="140.5" cy="57.1" r=".25"/>
<circle cx="139.6" cy="57.1" r=".25"/>
<circle cx="138.6" cy="57.1" r=".25"/>
<circle cx="137.7" cy="57.1" r=".25"/>
<circle cx="136.8" cy="57.1" r=".25"/>
<circle cx="135.9" cy="57.1" r=".26"/>
<circle cx="134.9" cy="57.1" r=".25"/>
<circle cx="134" cy="57.1" r=".26"/>
<circle cx="133.1" cy="57.1" r=".25"/>
<circle cx="132.2" cy="57.1" r=".25"/>
<circle cx="131.3" cy="57.1" r=".25"/>
<circle cx="130.3" cy="57.1" r=".25"/>
<circle cx="129.4" cy="57.1" r=".26"/>
<circle cx="128.5" cy="57.1" r=".25"/>
<circle cx="127.6" cy="57.1" r=".26"/>
<circle cx="126.6" cy="57.1" r=".25"/>
<circle cx="125.7" cy="57.1" r=".25"/>
<circle cx="124.8" cy="57.1" r=".25"/>
<circle cx="123.9" cy="57.1" r=".25"/>
<circle cx="123" cy="57.1" r=".25"/>
<circle cx="122" cy="57.1" r=".25"/>
<circle cx="121.1" cy="57.1" r=".26"/>
<circle cx="120.2" cy="57.1" r=".25"/>
<circle cx="119.3" cy="57.1" r=".25"/>
<circle cx="118.3" cy="57.1" r=".25"/>
<circle cx="117.4" cy="57.1" r=".25"/>
<circle cx="116.5" cy="57.1" r=".25"/>
<circle cx="115.6" cy="57.1" r=".25"/>
<circle cx="114.6" cy="57.1" r=".26"/>
<circle cx="113.7" cy="57.1" r=".25"/>
<circle cx="112.8" cy="57.1" r=".25"/>
<circle cx="111.9" cy="57.1" r=".25"/>
<circle cx="111" cy="57.1" r=".25"/>
<circle cx="110" cy="57.1" r=".25"/>
<circle cx="109.1" cy="57.1" r=".25"/>
<circle cx="108.2" cy="57.1" r=".26"/>
<circle cx="107.3" cy="57.1" r=".25"/>
<circle cx="106.4" cy="57.1" r=".26"/>
<circle cx="105.4" cy="57.1" r=".25"/>
<circle cx="104.5" cy="57.1" r=".25"/>
<circle cx="103.6" cy="57.1" r=".25"/>
<circle cx="102.7" cy="57.1" r=".25"/>
</g>
<circle cx="117" cy="62.5" r=".76" fill="#008000" stroke="#008000" stroke-width=".2"/>
<circle cx="117" cy="62.5" r=".51" fill="#fff" stroke="#000" stroke-width=".2"/>
<circle cx="117" cy="60" r=".76" fill="#008000" stroke="#008000" stroke-width=".2"/>
<circle cx="117" cy="60" r=".51" fill="#fff" stroke="#000" stroke-width=".2"/>
<circle cx="119.5" cy="62.5" r=".76" fill="#008000" stroke="#008000" stroke-width=".2"/>
<circle cx="119.5" cy="62.5" r=".51" fill="#fff" stroke="#000" stroke-width=".2"/>
<circle cx="119.5" cy="60" r=".76" fill="#008000" stroke="#008000" stroke-width=".2"/>
<circle cx="119.5" cy="60" r=".51" fill="#fff" stroke="#000" stroke-width=".2"/>
<circle cx="122.1" cy="62.5" r=".76" fill="#008000" stroke="#008000" stroke-width=".2"/>
<circle cx="122.1" cy="62.5" r=".51" fill="#fff" stroke="#000" stroke-width=".2"/>
<circle cx="122.1" cy="60" r=".76" fill="#008000" stroke="#008000" stroke-width=".2"/>
<circle cx="122.1" cy="60" r=".51" fill="#fff" stroke="#000" stroke-width=".2"/>
<circle cx="124.6" cy="62.5" r=".76" fill="#008000" stroke="#008000" stroke-width=".2"/>
<circle cx="124.6" cy="62.5" r=".51" fill="#fff" stroke="#000" stroke-width=".2"/>
<circle cx="124.6" cy="60" r=".76" fill="#008000" stroke="#008000" stroke-width=".2"/>
<circle cx="124.6" cy="60" r=".51" fill="#fff" stroke="#000" stroke-width=".2"/>
<circle cx="127.1" cy="62.5" r=".76" fill="#008000" stroke="#008000" stroke-width=".2"/>
<circle cx="127.1" cy="62.5" r=".51" fill="#fff" stroke="#000" stroke-width=".2"/>
<circle cx="127.1" cy="60" r=".76" fill="#008000" stroke="#008000" stroke-width=".2"/>
<circle cx="127.1" cy="60" r=".51" fill="#fff" stroke="#000" stroke-width=".2"/>
<circle cx="129.7" cy="62.5" r=".76" fill="#008000" stroke="#008000" stroke-width=".2"/>
<circle cx="129.7" cy="62.5" r=".51" fill="#fff" stroke="#000" stroke-width=".2"/>
<circle cx="129.7" cy="60" r=".76" fill="#008000" stroke="#008000" stroke-width=".2"/>
<circle cx="129.7" cy="60" r=".51" fill="#fff" stroke="#000" stroke-width=".2"/>
<circle cx="132.2" cy="62.5" r=".76" fill="#008000" stroke="#008000" stroke-width=".2"/>
<circle cx="132.2" cy="62.5" r=".51" fill="#fff" stroke="#000" stroke-width=".2"/>
<circle cx="132.2" cy="60" r=".76" fill="#008000" stroke="#008000" stroke-width=".2"/>
<circle cx="132.2" cy="60" r=".51" fill="#fff" stroke="#000" stroke-width=".2"/>
<circle cx="134.8" cy="62.5" r=".76" fill="#008000" stroke="#008000" stroke-width=".2"/>
<circle cx="134.8" cy="62.5" r=".51" fill="#fff" stroke="#000" stroke-width=".2"/>
<circle cx="134.8" cy="60" r=".76" fill="#008000" stroke="#008000" stroke-width=".2"/>
<circle cx="134.8" cy="60" r=".51" fill="#fff" stroke="#000" stroke-width=".2"/>
<circle cx="137.3" cy="62.5" r=".76" fill="#008000" stroke="#008000" stroke-width=".2"/>
<circle cx="137.3" cy="62.5" r=".51" fill="#fff" stroke="#000" stroke-width=".2"/>
<circle cx="137.3" cy="60" r=".76" fill="#008000" stroke="#008000" stroke-width=".2"/>
<circle cx="137.3" cy="60" r=".51" fill="#fff" stroke="#000" stroke-width=".2"/>
<circle cx="139.8" cy="62.5" r=".76" fill="#008000" stroke="#008000" stroke-width=".2"/>
<circle cx="139.8" cy="62.5" r=".51" fill="#fff" stroke="#000" stroke-width=".2"/>
<circle cx="139.8" cy="60" r=".76" fill="#008000" stroke="#008000" stroke-width=".2"/>
<circle cx="139.8" cy="60" r=".51" fill="#fff" stroke="#000" stroke-width=".2"/>
<circle cx="142.4" cy="62.5" r=".76" fill="#008000" stroke="#008000" stroke-width=".2"/>
<circle cx="142.4" cy="62.5" r=".51" fill="#fff" stroke="#000" stroke-width=".2"/>
<circle cx="142.4" cy="60" r=".76" fill="#008000" stroke="#008000" stroke-width=".2"/>
<circle cx="142.4" cy="60" r=".51" fill="#fff" stroke="#000" stroke-width=".2"/>
<circle cx="144.9" cy="62.5" r=".76" fill="#008000" stroke="#008000" stroke-width=".2"/>
<circle cx="144.9" cy="62.5" r=".51" fill="#fff" stroke="#000" stroke-width=".2"/>
<circle cx="144.9" cy="60" r=".76" fill="#008000" stroke="#008000" stroke-width=".2"/>
<circle cx="144.9" cy="60" r=".51" fill="#fff" stroke="#000" stroke-width=".2"/>
<circle cx="147.5" cy="62.5" r=".76" fill="#008000" stroke="#008000" stroke-width=".2"/>
<circle cx="147.5" cy="62.5" r=".51" fill="#fff" stroke="#000" stroke-width=".2"/>
<circle cx="147.5" cy="60" r=".76" fill="#008000" stroke="#008000" stroke-width=".2"/>
<circle cx="147.5" cy="60" r=".51" fill="#fff" stroke="#000" stroke-width=".2"/>
<circle cx="150" cy="62.5" r=".76" fill="#008000" stroke="#008000" stroke-width=".2"/>
<circle cx="150" cy="62.5" r=".51" fill="#fff" stroke="#000" stroke-width=".2"/>
<circle cx="150" cy="60" r=".76" fill="#008000" stroke="#008000" stroke-width=".2"/>
<circle cx="150" cy="60" r=".51" fill="#fff" stroke="#000" stroke-width=".2"/>
<circle cx="152.5" cy="62.5" r=".76" fill="#008000" stroke="#008000" stroke-width=".2"/>
<circle cx="152.5" cy="62.5" r=".51" fill="#fff" stroke="#000" stroke-width=".2"/>
<circle cx="152.5" cy="60" r=".76" fill="#008000" stroke="#008000" stroke-width=".2"/>
<circle cx="152.5" cy="60" r=".51" fill="#fff" stroke="#000" stroke-width=".2"/>
<circle cx="155.1" cy="62.5" r=".76" fill="#008000" stroke="#008000" stroke-width=".2"/>
<circle cx="155.1" cy="62.5" r=".51" fill="#fff" stroke="#000" stroke-width=".2"/>
<circle cx="155.1" cy="60" r=".76" fill="#008000" stroke="#008000" stroke-width=".2"/>
<circle cx="155.1" cy="60" r=".51" fill="#fff" stroke="#000" stroke-width=".2"/>
<circle cx="157.6" cy="62.5" r=".76" fill="#008000" stroke="#008000" stroke-width=".2"/>
<circle cx="157.6" cy="62.5" r=".51" fill="#fff" stroke="#000" stroke-width=".2"/>
<circle cx="157.6" cy="60" r=".76" fill="#008000" stroke="#008000" stroke-width=".2"/>
<circle cx="157.6" cy="60" r=".51" fill="#fff" stroke="#000" stroke-width=".2"/>
<circle cx="160.1" cy="62.5" r=".76" fill="#008000" stroke="#008000" stroke-width=".2"/>
<circle cx="160.1" cy="62.5" r=".51" fill="#fff" stroke="#000" stroke-width=".2"/>
<circle cx="160.1" cy="60" r=".76" fill="#008000" stroke="#008000" stroke-width=".2"/>
<circle cx="160.1" cy="60" r=".51" fill="#fff" stroke="#000" stroke-width=".2"/>
<circle cx="162.7" cy="62.5" r=".76" fill="#008000" stroke="#008000" stroke-width=".2"/>
<circle cx="162.7" cy="62.5" r=".51" fill="#fff" stroke="#000" stroke-width=".2"/>
<circle cx="162.7" cy="60" r=".76" fill="#008000" stroke="#008000" stroke-width=".2"/>
<circle cx="162.7" cy="60" r=".51" fill="#fff" stroke="#000" stroke-width=".2"/>
<circle cx="165.2" cy="62.5" r=".76" fill="#008000" stroke="#008000" stroke-width=".2"/>
<circle cx="165.2" cy="62.5" r=".51" fill="#fff" stroke="#000" stroke-width=".2"/>
<circle cx="165.2" cy="60" r=".76" fill="#008000" stroke="#008000" stroke-width=".2"/>
<circle cx="165.2" cy="60" r=".51" fill="#fff" stroke="#000" stroke-width=".2"/>
<circle cx="167.8" cy="62.5" r=".76" fill="#008000" stroke="#008000" stroke-width=".2"/>
<circle cx="167.8" cy="62.5" r=".51" fill="#fff" stroke="#000" stroke-width=".2"/>
<circle cx="167.8" cy="60" r=".76" fill="#008000" stroke="#008000" stroke-width=".2"/>
<circle cx="167.8" cy="60" r=".51" fill="#fff" stroke="#000" stroke-width=".2"/>
<circle cx="170.3" cy="62.5" r=".76" fill="#008000" stroke="#008000" stroke-width=".2"/>
<circle cx="170.3" cy="62.5" r=".51" fill="#fff" stroke="#000" stroke-width=".2"/>
<circle cx="170.3" cy="60" r=".76" fill="#008000" stroke="#008000" stroke-width=".2"/>
<circle cx="170.3" cy="60" r=".51" fill="#fff" stroke="#000" stroke-width=".2"/>
<circle cx="172.8" cy="62.5" r=".76" fill="#008000" stroke="#008000" stroke-width=".2"/>
<circle cx="172.8" cy="62.5" r=".51" fill="#fff" stroke="#000" stroke-width=".2"/>
<circle cx="172.8" cy="60" r=".76" fill="#008000" stroke="#008000" stroke-width=".2"/>
<circle cx="172.8" cy="60" r=".51" fill="#fff" stroke="#000" stroke-width=".2"/>
<circle cx="175.4" cy="62.5" r=".76" fill="#008000" stroke="#008000" stroke-width=".2"/>
<circle cx="175.4" cy="62.5" r=".51" fill="#fff" stroke="#000" stroke-width=".2"/>
<circle cx="175.4" cy="60" r=".76" fill="#008000" stroke="#008000" stroke-width=".2"/>
<circle cx="175.4" cy="60" r=".51" fill="#fff" stroke="#000" stroke-width=".2"/>
<circle cx="177.9" cy="62.5" r=".76" fill="#008000" stroke="#008000" stroke-width=".2"/>
<circle cx="177.9" cy="62.5" r=".51" fill="#fff" stroke="#000" stroke-width=".2"/>
<circle cx="177.9" cy="60" r=".76" fill="#008000" stroke="#008000" stroke-width=".2"/>
<circle cx="177.9" cy="60" r=".51" fill="#fff" stroke="#000" stroke-width=".2"/>
<circle cx="180.5" cy="62.5" r=".76" fill="#008000" stroke="#008000" stroke-width=".2"/>
<circle cx="180.5" cy="62.5" r=".51" fill="#fff" stroke="#000" stroke-width=".2"/>
<circle cx="180.5" cy="60" r=".76" fill="#008000" stroke="#008000" stroke-width=".2"/>
<circle cx="180.5" cy="60" r=".51" fill="#fff" stroke="#000" stroke-width=".2"/>
<circle cx="117" cy="67.6" r=".76" fill="#008000" stroke="#008000" stroke-width=".2"/>
<circle cx="117" cy="67.6" r=".51" fill="#fff" stroke="#000" stroke-width=".2"/>
<circle cx="117" cy="65.1" r=".76" fill="#008000" stroke="#008000" stroke-width=".2"/>
<circle cx="117" cy="65.1" r=".51" fill="#fff" stroke="#000" stroke-width=".2"/>
<circle cx="119.5" cy="67.6" r=".76" fill="#008000" stroke="#008000" stroke-width=".2"/>
<circle cx="119.5" cy="67.6" r=".51" fill="#fff" stroke="#000" stroke-width=".2"/>
<circle cx="119.5" cy="65.1" r=".76" fill="#008000" stroke="#008000" stroke-width=".2"/>
<circle cx="119.5" cy="65.1" r=".51" fill="#fff" stroke="#000" stroke-width=".2"/>
<circle cx="122.1" cy="67.6" r=".76" fill="#008000" stroke="#008000" stroke-width=".2"/>
<circle cx="122.1" cy="67.6" r=".51" fill="#fff" stroke="#000" stroke-width=".2"/>
<circle cx="122.1" cy="65.1" r=".76" fill="#008000" stroke="#008000" stroke-width=".2"/>
<circle cx="122.1" cy="65.1" r=".51" fill="#fff" stroke="#000" stroke-width=".2"/>
<circle cx="124.6" cy="67.6" r=".76" fill="#008000" stroke="#008000" stroke-width=".2"/>
<circle cx="124.6" cy="67.6" r=".51" fill="#fff" stroke="#000" stroke-width=".2"/>
<circle cx="124.6" cy="65.1" r=".76" fill="#008000" stroke="#008000" stroke-width=".2"/>
<circle cx="124.6" cy="65.1" r=".51" fill="#fff" stroke="#000" stroke-width=".2"/>
<circle cx="127.1" cy="67.6" r=".76" fill="#008000" stroke="#008000" stroke-width=".2"/>
<circle cx="127.1" cy="67.6" r=".51" fill="#fff" stroke="#000" stroke-width=".2"/>
<circle cx="127.1" cy="65.1" r=".76" fill="#008000" stroke="#008000" stroke-width=".2"/>
<circle cx="127.1" cy="65.1" r=".51" fill="#fff" stroke="#000" stroke-width=".2"/>
<circle cx="129.7" cy="67.6" r=".76" fill="#008000" stroke="#008000" stroke-width=".2"/>
<circle cx="129.7" cy="67.6" r=".51" fill="#fff" stroke="#000" stroke-width=".2"/>
<circle cx="129.7" cy="65.1" r=".76" fill="#008000" stroke="#008000" stroke-width=".2"/>
<circle cx="129.7" cy="65.1" r=".51" fill="#fff" stroke="#000" stroke-width=".2"/>
<circle cx="132.2" cy="67.6" r=".76" fill="#008000" stroke="#008000" stroke-width=".2"/>
<circle cx="132.2" cy="67.6" r=".51" fill="#fff" stroke="#000" stroke-width=".2"/>
<circle cx="132.2" cy="65.1" r=".76" fill="#008000" stroke="#008000" stroke-width=".2"/>
<circle cx="132.2" cy="65.1" r=".51" fill="#fff" stroke="#000" stroke-width=".2"/>
<circle cx="134.8" cy="67.6" r=".76" fill="#008000" stroke="#008000" stroke-width=".2"/>
<circle cx="134.8" cy="67.6" r=".51" fill="#fff" stroke="#000" stroke-width=".2"/>
<circle cx="134.8" cy="65.1" r=".76" fill="#008000" stroke="#008000" stroke-width=".2"/>
<circle cx="134.8" cy="65.1" r=".51" fill="#fff" stroke="#000" stroke-width=".2"/>
<circle cx="137.3" cy="67.6" r=".76" fill="#008000" stroke="#008000" stroke-width=".2"/>
<circle cx="137.3" cy="67.6" r=".51" fill="#fff" stroke="#000" stroke-width=".2"/>
<circle cx="137.3" cy="65.1" r=".76" fill="#008000" stroke="#008000" stroke-width=".2"/>
<circle cx="137.3" cy="65.1" r=".51" fill="#fff" stroke="#000" stroke-width=".2"/>
<circle cx="139.8" cy="67.6" r=".76" fill="#008000" stroke="#008000" stroke-width=".2"/>
<circle cx="139.8" cy="67.6" r=".51" fill="#fff" stroke="#000" stroke-width=".2"/>
<circle cx="139.8" cy="65.1" r=".76" fill="#008000" stroke="#008000" stroke-width=".2"/>
<circle cx="139.8" cy="65.1" r=".51" fill="#fff" stroke="#000" stroke-width=".2"/>
<circle cx="142.4" cy="67.6" r=".76" fill="#008000" stroke="#008000" stroke-width=".2"/>
<circle cx="142.4" cy="67.6" r=".51" fill="#fff" stroke="#000" stroke-width=".2"/>
<circle cx="142.4" cy="65.1" r=".76" fill="#008000" stroke="#008000" stroke-width=".2"/>
<circle cx="142.4" cy="65.1" r=".51" fill="#fff" stroke="#000" stroke-width=".2"/>
<circle cx="144.9" cy="67.6" r=".76" fill="#008000" stroke="#008000" stroke-width=".2"/>
<circle cx="144.9" cy="67.6" r=".51" fill="#fff" stroke="#000" stroke-width=".2"/>
<circle cx="144.9" cy="65.1" r=".76" fill="#008000" stroke="#008000" stroke-width=".2"/>
<circle cx="144.9" cy="65.1" r=".51" fill="#fff" stroke="#000" stroke-width=".2"/>
<circle cx="147.4" cy="67.6" r=".76" fill="#008000" stroke="#008000" stroke-width=".2"/>
<circle cx="147.4" cy="67.6" r=".51" fill="#fff" stroke="#000" stroke-width=".2"/>
<circle cx="147.4" cy="65.1" r=".76" fill="#008000" stroke="#008000" stroke-width=".2"/>
<circle cx="147.4" cy="65.1" r=".51" fill="#fff" stroke="#000" stroke-width=".2"/>
<circle cx="150" cy="67.6" r=".76" fill="#008000" stroke="#008000" stroke-width=".2"/>
<circle cx="150" cy="67.6" r=".51" fill="#fff" stroke="#000" stroke-width=".2"/>
<circle cx="150" cy="65.1" r=".76" fill="#008000" stroke="#008000" stroke-width=".2"/>
<circle cx="150" cy="65.1" r=".51" fill="#fff" stroke="#000" stroke-width=".2"/>
<circle cx="152.5" cy="67.6" r=".76" fill="#008000" stroke="#008000" stroke-width=".2"/>
<circle cx="152.5" cy="67.6" r=".51" fill="#fff" stroke="#000" stroke-width=".2"/>
<circle cx="152.5" cy="65.1" r=".76" fill="#008000" stroke="#008000" stroke-width=".2"/>
<circle cx="152.5" cy="65.1" r=".51" fill="#fff" stroke="#000" stroke-width=".2"/>
<circle cx="155.1" cy="67.6" r=".76" fill="#008000" stroke="#008000" stroke-width=".2"/>
<circle cx="155.1" cy="67.6" r=".51" fill="#fff" stroke="#000" stroke-width=".2"/>
<circle cx="155.1" cy="65.1" r=".76" fill="#008000" stroke="#008000" stroke-width=".2"/>
<circle cx="155.1" cy="65.1" r=".51" fill="#fff" stroke="#000" stroke-width=".2"/>
<circle cx="157.6" cy="67.6" r=".76" fill="#008000" stroke="#008000" stroke-width=".2"/>
<circle cx="157.6" cy="67.6" r=".51" fill="#fff" stroke="#000" stroke-width=".2"/>
<circle cx="157.6" cy="65.1" r=".76" fill="#008000" stroke="#008000" stroke-width=".2"/>
<circle cx="157.6" cy="65.1" r=".51" fill="#fff" stroke="#000" stroke-width=".2"/>
<circle cx="160.1" cy="67.6" r=".76" fill="#008000" stroke="#008000" stroke-width=".2"/>
<circle cx="160.1" cy="67.6" r=".51" fill="#fff" stroke="#000" stroke-width=".2"/>
<circle cx="160.1" cy="65.1" r=".76" fill="#008000" stroke="#008000" stroke-width=".2"/>
<circle cx="160.1" cy="65.1" r=".51" fill="#fff" stroke="#000" stroke-width=".2"/>
<circle cx="162.7" cy="67.6" r=".76" fill="#008000" stroke="#008000" stroke-width=".2"/>
<circle cx="162.7" cy="67.6" r=".51" fill="#fff" stroke="#000" stroke-width=".2"/>
<circle cx="162.7" cy="65.1" r=".76" fill="#008000" stroke="#008000" stroke-width=".2"/>
<circle cx="162.7" cy="65.1" r=".51" fill="#fff" stroke="#000" stroke-width=".2"/>
<circle cx="165.2" cy="67.6" r=".76" fill="#008000" stroke="#008000" stroke-width=".2"/>
<circle cx="165.2" cy="67.6" r=".51" fill="#fff" stroke="#000" stroke-width=".2"/>
<circle cx="165.2" cy="65.1" r=".76" fill="#008000" stroke="#008000" stroke-width=".2"/>
<circle cx="165.2" cy="65.1" r=".51" fill="#fff" stroke="#000" stroke-width=".2"/>
<circle cx="167.8" cy="67.6" r=".76" fill="#008000" stroke="#008000" stroke-width=".2"/>
<circle cx="167.8" cy="67.6" r=".51" fill="#fff" stroke="#000" stroke-width=".2"/>
<circle cx="167.8" cy="65.1" r=".76" fill="#008000" stroke="#008000" stroke-width=".2"/>
<circle cx="167.8" cy="65.1" r=".51" fill="#fff" stroke="#000" stroke-width=".2"/>
<circle cx="170.3" cy="67.6" r=".76" fill="#008000" stroke="#008000" stroke-width=".2"/>
<circle cx="170.3" cy="67.6" r=".51" fill="#fff" stroke="#000" stroke-width=".2"/>
<circle cx="170.3" cy="65.1" r=".76" fill="#008000" stroke="#008000" stroke-width=".2"/>
<circle cx="170.3" cy="65.1" r=".51" fill="#fff" stroke="#000" stroke-width=".2"/>
<circle cx="172.8" cy="67.6" r=".76" fill="#008000" stroke="#008000" stroke-width=".2"/>
<circle cx="172.8" cy="67.6" r=".51" fill="#fff" stroke="#000" stroke-width=".2"/>
<circle cx="172.8" cy="65.1" r=".76" fill="#008000" stroke="#008000" stroke-width=".2"/>
<circle cx="172.8" cy="65.1" r=".51" fill="#fff" stroke="#000" stroke-width=".2"/>
<circle cx="175.4" cy="67.6" r=".76" fill="#008000" stroke="#008000" stroke-width=".2"/>
<circle cx="175.4" cy="67.6" r=".51" fill="#fff" stroke="#000" stroke-width=".2"/>
<circle cx="175.4" cy="65.1" r=".76" fill="#008000" stroke="#008000" stroke-width=".2"/>
<circle cx="175.4" cy="65.1" r=".51" fill="#fff" stroke="#000" stroke-width=".2"/>
<circle cx="177.9" cy="67.6" r=".76" fill="#008000" stroke="#008000" stroke-width=".2"/>
<circle cx="177.9" cy="67.6" r=".51" fill="#fff" stroke="#000" stroke-width=".2"/>
<circle cx="177.9" cy="65.1" r=".76" fill="#008000" stroke="#008000" stroke-width=".2"/>
<circle cx="177.9" cy="65.1" r=".51" fill="#fff" stroke="#000" stroke-width=".2"/>
<circle cx="180.5" cy="67.6" r=".76" fill="#008000" stroke="#008000" stroke-width=".2"/>
<circle cx="180.5" cy="67.6" r=".51" fill="#fff" stroke="#000" stroke-width=".2"/>
<circle cx="180.5" cy="65.1" r=".76" fill="#008000" stroke="#008000" stroke-width=".2"/>
<circle cx="180.5" cy="65.1" r=".51" fill="#fff" stroke="#000" stroke-width=".2"/>
<circle cx="186.8" cy="103.7" r=".51" fill="#008000" stroke="#008000" stroke-width=".2"/>
<circle cx="186.8" cy="103.7" r=".3" fill="#fff" stroke="#000" stroke-width=".2"/>
<circle cx="183.3" cy="103.7" r=".51" fill="#008000" stroke="#008000" stroke-width=".2"/>
<circle cx="183.3" cy="103.7" r=".3" fill="#fff" stroke="#000" stroke-width=".2"/>
<circle cx="185.1" cy="128.8" r=".51" fill="#008000" stroke="#008000" stroke-width=".2"/>
<circle cx="185.1" cy="128.8" r=".3" fill="#fff" stroke="#000" stroke-width=".2"/>
<circle cx="187.7" cy="126.2" r=".51" fill="#008000" stroke="#008000" stroke-width=".2"/>
<circle cx="187.7" cy="126.2" r=".3" fill="#fff" stroke="#000" stroke-width=".2"/>
<circle cx="186.9" cy="134.9" r=".51" fill="#008000" stroke="#008000" stroke-width=".2"/>
<circle cx="186.9" cy="134.9" r=".3" fill="#fff" stroke="#000" stroke-width=".2"/>
<circle cx="183.1" cy="134.9" r=".51" fill="#008000" stroke="#008000" stroke-width=".2"/>
<circle cx="183.1" cy="134.9" r=".3" fill="#fff" stroke="#000" stroke-width=".2"/>
<circle cx="177.4" cy="130.7" r=".51" fill="#008000" stroke="#008000" stroke-width=".2"/>
<circle cx="177.4" cy="130.7" r=".3" fill="#fff" stroke="#000" stroke-width=".2"/>
<circle cx="182.3" cy="130.7" r=".51" fill="#008000" stroke="#008000" stroke-width=".2"/>
<circle cx="182.3" cy="130.7" r=".3" fill="#fff" stroke="#000" stroke-width=".2"/>
<circle cx="156.5" cy="73.2" r=".51" fill="#008000" stroke="#008000" stroke-width=".2"/>
<circle cx="156.5" cy="73.2" r=".3" fill="#fff" stroke="#000" stroke-width=".2"/>
<circle cx="159.1" cy="134.9" r=".51" fill="#008000" stroke="#008000" stroke-width=".2"/>
<circle cx="159.1" cy="134.9" r=".3" fill="#fff" stroke="#000" stroke-width=".2"/>
<circle cx="145.4" cy="69.7" r=".51" fill="#008000" stroke="#008000" stroke-width=".2"/>
<circle cx="145.4" cy="69.7" r=".3" fill="#fff" stroke="#000" stroke-width=".2"/>
<circle cx="133.7" cy="93.8" r=".51" fill="#008000" stroke="#008000" stroke-width=".2"/>
<circle cx="133.7" cy="93.8" r=".3" fill="#fff" stroke="#000" stroke-width=".2"/>
<circle cx="125.8" cy="139" r=".51" fill="#008000" stroke="#008000" stroke-width=".2"/>
<circle cx="125.8" cy="139" r=".3" fill="#fff" stroke="#000" stroke-width=".2"/>
<circle cx="141.7" cy="135" r=".51" fill="#008000" stroke="#008000" stroke-width=".2"/>
<circle cx="141.7" cy="135" r=".3" fill="#fff" stroke="#000" stroke-width=".2"/>
<circle cx="143" cy="130.3" r=".51" fill="#008000" stroke="#008000" stroke-width=".2"/>
<circle cx="143" cy="130.3" r=".3" fill="#fff" stroke="#000" stroke-width=".2"/>
<circle cx="147.8" cy="136.2" r=".51" fill="#008000" stroke="#008000" stroke-width=".2"/>
<circle cx="147.8" cy="136.2" r=".3" fill="#fff" stroke="#000" stroke-width=".2"/>
<circle cx="147.8" cy="132.4" r=".51" fill="#008000" stroke="#008000" stroke-width=".2"/>
<circle cx="147.8" cy="132.4" r=".3" fill="#fff" stroke="#000" stroke-width=".2"/>
<circle cx="180.4" cy="96" r=".51" fill="#008000" stroke="#008000" stroke-width=".2"/>
<circle cx="180.4" cy="96" r=".3" fill="#fff" stroke="#000" stroke-width=".2"/>
<circle cx="175.3" cy="102.6" r=".51" fill="#008000" stroke="#008000" stroke-width=".2"/>
<circle cx="175.3" cy="102.6" r=".3" fill="#fff" stroke="#000" stroke-width=".2"/>
<circle cx="191.1" cy="91.4" r=".51" fill="#008000" stroke="#008000" stroke-width=".2"/>
<circle cx="191.1" cy="91.4" r=".3" fill="#fff" stroke="#000" stroke-width=".2"/>
<circle cx="151.9" cy="83.2" r=".51" fill="#008000" stroke="#008000" stroke-width=".2"/>
<circle cx="151.9" cy="83.2" r=".3" fill="#fff" stroke="#000" stroke-width=".2"/>
<circle cx="132.8" cy="137.5" r=".51" fill="#008000" stroke="#008000" stroke-width=".2"/>
<circle cx="132.8" cy="137.5" r=".3" fill="#fff" stroke="#000" stroke-width=".2"/>
<circle cx="130.8" cy="130.5" r=".51" fill="#008000" stroke="#008000" stroke-width=".2"/>
<circle cx="130.8" cy="130.5" r=".3" fill="#fff" stroke="#000" stroke-width=".2"/>
<circle cx="149.5" cy="137.7" r=".51" fill="#008000" stroke="#008000" stroke-width=".2"/>
<circle cx="149.5" cy="137.7" r=".3" fill="#fff" stroke="#000" stroke-width=".2"/>
<circle cx="148.4" cy="128.6" r=".51" fill="#008000" stroke="#008000" stroke-width=".2"/>
<circle cx="148.4" cy="128.6" r=".3" fill="#fff" stroke="#000" stroke-width=".2"/>
<circle cx="127.2" cy="70.6" r=".51" fill="#008000" stroke="#008000" stroke-width=".2"/>
<circle cx="127.2" cy="70.6" r=".3" fill="#fff" stroke="#000" stroke-width=".2"/>
<circle cx="127.2" cy="75.1" r=".51" fill="#008000" stroke="#008000" stroke-width=".2"/>
<circle cx="127.2" cy="75.1" r=".3" fill="#fff" stroke="#000" stroke-width=".2"/>
<circle cx="180.1" cy="127" r=".51" fill="#008000" stroke="#008000" stroke-width=".2"/>
<circle cx="180.1" cy="127" r=".3" fill="#fff" stroke="#000" stroke-width=".2"/>
<circle cx="191.1" cy="122.6" r=".51" fill="#008000" stroke="#008000" stroke-width=".2"/>
<circle cx="191.1" cy="122.6" r=".3" fill="#fff" stroke="#000" stroke-width=".2"/>
<circle cx="175.3" cy="134.6" r=".51" fill="#008000" stroke="#008000" stroke-width=".2"/>
<circle cx="175.3" cy="134.6" r=".3" fill="#fff" stroke="#000" stroke-width=".2"/>
<circle cx="133.9" cy="128.5" r=".51" fill="#008000" stroke="#008000" stroke-width=".2"/>
<circle cx="133.9" cy="128.5" r=".3" fill="#fff" stroke="#000" stroke-width=".2"/>
<circle cx="149.3" cy="90.6" r=".51" fill="#008000" stroke="#008000" stroke-width=".2"/>
<circle cx="149.3" cy="90.6" r=".3" fill="#fff" stroke="#000" stroke-width=".2"/>
<circle cx="127.2" cy="79" r=".51" fill="#008000" stroke="#008000" stroke-width=".2"/>
<circle cx="127.2" cy="79" r=".3" fill="#fff" stroke="#000" stroke-width=".2"/>
<circle cx="142.1" cy="78.7" r=".51" fill="#008000" stroke="#008000" stroke-width=".2"/>
<circle cx="142.1" cy="78.7" r=".3" fill="#fff" stroke="#000" stroke-width=".2"/>
<circle cx="146.2" cy="78.4" r=".51" fill="#008000" stroke="#008000" stroke-width=".2"/>
<circle cx="146.2" cy="78.4" r=".3" fill="#fff" stroke="#000" stroke-width=".2"/>
<circle cx="146" cy="74.2" r=".51" fill="#008000" stroke="#008000" stroke-width=".2"/>
<circle cx="146" cy="74.2" r=".3" fill="#fff" stroke="#000" stroke-width=".2"/>
<circle cx="146.3" cy="124.5" r=".51" fill="#008000" stroke="#008000" stroke-width=".2"/>
<circle cx="146.3" cy="124.5" r=".3" fill="#fff" stroke="#000" stroke-width=".2"/>
<circle cx="136.8" cy="111.2" r=".51" fill="#008000" stroke="#008000" stroke-width=".2"/>
<circle cx="136.8" cy="111.2" r=".3" fill="#fff" stroke="#000" stroke-width=".2"/>
<circle cx="138.4" cy="117.2" r=".51" fill="#008000" stroke="#008000" stroke-width=".2"/>
<circle cx="138.4" cy="117.2" r=".3" fill="#fff" stroke="#000" stroke-width=".2"/>
<circle cx="113.7" cy="87.7" r=".51" fill="#008000" stroke="#008000" stroke-width=".2"/>
<circle cx="113.7" cy="87.7" r=".3" fill="#fff" stroke="#000" stroke-width=".2"/>
<circle cx="121.2" cy="87.9" r=".51" fill="#008000" stroke="#008000" stroke-width=".2"/>
<circle cx="121.2" cy="87.9" r=".3" fill="#fff" stroke="#000" stroke-width=".2"/>
<circle cx="177.8" cy="73.2" r=".51" fill="#008000" stroke="#008000" stroke-width=".2"/>
<circle cx="177.8" cy="73.2" r=".3" fill="#fff" stroke="#000" stroke-width=".2"/>
<circle cx="125.8" cy="129.3" r=".51" fill="#008000" stroke="#008000" stroke-width=".2"/>
<circle cx="125.8" cy="129.3" r=".3" fill="#fff" stroke="#000" stroke-width=".2"/>
<circle cx="125.8" cy="134.8" r=".51" fill="#008000" stroke="#008000" stroke-width=".2"/>
<circle cx="125.8" cy="134.8" r=".3" fill="#fff" stroke="#000" stroke-width=".2"/>
<circle cx="131.4" cy="136" r=".51" fill="#008000" stroke="#008000" stroke-width=".2"/>
<circle cx="131.4" cy="136" r=".3" fill="#fff" stroke="#000" stroke-width=".2"/>
<circle cx="131.4" cy="132.7" r=".51" fill="#008000" stroke="#008000" stroke-width=".2"/>
<circle cx="131.4" cy="132.7" r=".3" fill="#fff" stroke="#000" stroke-width=".2"/>
<circle cx="153.7" cy="73.1" r=".51" fill="#008000" stroke="#008000" stroke-width=".2"/>
<circle cx="153.7" cy="73.1" r=".3" fill="#fff" stroke="#000" stroke-width=".2"/>
<circle cx="158.1" cy="90.7" r=".51" fill="#008000" stroke="#008000" stroke-width=".2"/>
<circle cx="158.1" cy="90.7" r=".3" fill="#fff" stroke="#000" stroke-width=".2"/>
<circle cx="142.4" cy="69.7" r=".51" fill="#008000" stroke="#008000" stroke-width=".2"/>
<circle cx="142.4" cy="69.7" r=".3" fill="#fff" stroke="#000" stroke-width=".2"/>
<circle cx="129.8" cy="75.1" r=".51" fill="#008000" stroke="#008000" stroke-width=".2"/>
<circle cx="129.8" cy="75.1" r=".3" fill="#fff" stroke="#000" stroke-width=".2"/>
<circle cx="129.8" cy="79" r=".51" fill="#008000" stroke="#008000" stroke-width=".2"/>
<circle cx="129.8" cy="79" r=".3" fill="#fff" stroke="#000" stroke-width=".2"/>
<circle cx="177.3" cy="121.1" r=".51" fill="#008000" stroke="#008000" stroke-width=".2"/>
<circle cx="177.3" cy="121.1" r=".3" fill="#fff" stroke="#000" stroke-width=".2"/>
<circle cx="177.3" cy="124.5" r=".51" fill="#008000" stroke="#008000" stroke-width=".2"/>
<circle cx="177.3" cy="124.5" r=".3" fill="#fff" stroke="#000" stroke-width=".2"/>
<circle cx="156.5" cy="116.9" r=".51" fill="#008000" stroke="#008000" stroke-width=".2"/>
<circle cx="156.5" cy="116.9" r=".3" fill="#fff" stroke="#000" stroke-width=".2"/>
<circle cx="164" cy="117.9" r=".51" fill="#008000" stroke="#008000" stroke-width=".2"/>
<circle cx="164" cy="117.9" r=".3" fill="#fff" stroke="#000" stroke-width=".2"/>
<circle cx="130.8" cy="70.8" r=".51" fill="#008000" stroke="#008000" stroke-width=".2"/>
<circle cx="130.8" cy="70.8" r=".3" fill="#fff" stroke="#000" stroke-width=".2"/>
<circle cx="157.5" cy="75.4" r=".51" fill="#008000" stroke="#008000" stroke-width=".2"/>
<circle cx="157.5" cy="75.4" r=".3" fill="#fff" stroke="#000" stroke-width=".2"/>
<circle cx="136.3" cy="116.3" r=".51" fill="#008000" stroke="#008000" stroke-width=".2"/>
<circle cx="136.3" cy="116.3" r=".3" fill="#fff" stroke="#000" stroke-width=".2"/>
<circle cx="150.5" cy="115.8" r=".51" fill="#008000" stroke="#008000" stroke-width=".2"/>
<circle cx="150.5" cy="115.8" r=".3" fill="#fff" stroke="#000" stroke-width=".2"/>
<circle cx="145.1" cy="75.4" r=".51" fill="#008000" stroke="#008000" stroke-width=".2"/>
<circle cx="145.1" cy="75.4" r=".3" fill="#fff" stroke="#000" stroke-width=".2"/>
<circle cx="145.6" cy="114.6" r=".51" fill="#008000" stroke="#008000" stroke-width=".2"/>
<circle cx="145.6" cy="114.6" r=".3" fill="#fff" stroke="#000" stroke-width=".2"/>
<circle cx="140.7" cy="115.6" r=".51" fill="#008000" stroke="#008000" stroke-width=".2"/>
<circle cx="140.7" cy="115.6" r=".3" fill="#fff" stroke="#000" stroke-width=".2"/>
<circle cx="131.5" cy="115.3" r=".51" fill="#008000" stroke="#008000" stroke-width=".2"/>
<circle cx="131.5" cy="115.3" r=".3" fill="#fff" stroke="#000" stroke-width=".2"/>
<circle cx="127.5" cy="116" r=".51" fill="#008000" stroke="#008000" stroke-width=".2"/>
<circle cx="127.5" cy="116" r=".3" fill="#fff" stroke="#000" stroke-width=".2"/>
<circle cx="129.7" cy="82" r=".51" fill="#008000" stroke="#008000" stroke-width=".2"/>
<circle cx="129.7" cy="82" r=".3" fill="#fff" stroke="#000" stroke-width=".2"/>
<circle cx="164.8" cy="76.6" r=".51" fill="#008000" stroke="#008000" stroke-width=".2"/>
<circle cx="164.8" cy="76.6" r=".3" fill="#fff" stroke="#000" stroke-width=".2"/>
<circle cx="135.1" cy="69.9" r=".51" fill="#008000" stroke="#008000" stroke-width=".2"/>
<circle cx="135.1" cy="69.9" r=".3" fill="#fff" stroke="#000" stroke-width=".2"/>
<circle cx="140" cy="82.3" r=".51" fill="#008000" stroke="#008000" stroke-width=".2"/>
<circle cx="140" cy="82.3" r=".3" fill="#fff" stroke="#000" stroke-width=".2"/>
<circle cx="144.7" cy="95.7" r=".51" fill="#008000" stroke="#008000" stroke-width=".2"/>
<circle cx="144.7" cy="95.7" r=".3" fill="#fff" stroke="#000" stroke-width=".2"/>
<circle cx="138.3" cy="83.6" r=".51" fill="#008000" stroke="#008000" stroke-width=".2"/>
<circle cx="138.3" cy="83.6" r=".3" fill="#fff" stroke="#000" stroke-width=".2"/>
<circle cx="143.4" cy="96.3" r=".51" fill="#008000" stroke="#008000" stroke-width=".2"/>
<circle cx="143.4" cy="96.3" r=".3" fill="#fff" stroke="#000" stroke-width=".2"/>
<circle cx="125.9" cy="75.1" r=".51" fill="#008000" stroke="#008000" stroke-width=".2"/>
<circle cx="125.9" cy="75.1" r=".3" fill="#fff" stroke="#000" stroke-width=".2"/>
<circle cx="125.9" cy="79" r=".51" fill="#008000" stroke="#008000" stroke-width=".2"/>
<circle cx="125.9" cy="79" r=".3" fill="#fff" stroke="#000" stroke-width=".2"/>
<circle cx="140.4" cy="91.8" r=".51" fill="#008000" stroke="#008000" stroke-width=".2"/>
<circle cx="140.4" cy="91.8" r=".3" fill="#fff" stroke="#000" stroke-width=".2"/>
<circle cx="125.9" cy="95.4" r=".51" fill="#008000" stroke="#008000" stroke-width=".2"/>
<circle cx="125.9" cy="95.4" r=".3" fill="#fff" stroke="#000" stroke-width=".2"/>
<circle cx="133.2" cy="110.3" r=".51" fill="#008000" stroke="#008000" stroke-width=".2"/>
<circle cx="133.2" cy="110.3" r=".3" fill="#fff" stroke="#000" stroke-width=".2"/>
<circle cx="122.9" cy="105.2" r=".51" fill="#008000" stroke="#008000" stroke-width=".2"/>
<circle cx="122.9" cy="105.2" r=".3" fill="#fff" stroke="#000" stroke-width=".2"/>
<circle cx="115.2" cy="74.7" r=".51" fill="#008000" stroke="#008000" stroke-width=".2"/>
<circle cx="115.2" cy="74.7" r=".3" fill="#fff" stroke="#000" stroke-width=".2"/>
<circle cx="110.6" cy="80.3" r=".51" fill="#008000" stroke="#008000" stroke-width=".2"/>
<circle cx="110.6" cy="80.3" r=".3" fill="#fff" stroke="#000" stroke-width=".2"/>
<circle cx="147.7" cy="109.1" r=".51" fill="#008000" stroke="#008000" stroke-width=".2"/>
<circle cx="147.7" cy="109.1" r=".3" fill="#fff" stroke="#000" stroke-width=".2"/>
<circle cx="124.4" cy="106.8" r=".51" fill="#008000" stroke="#008000" stroke-width=".2"/>
<circle cx="124.4" cy="106.8" r=".3" fill="#fff" stroke="#000" stroke-width=".2"/>
<circle cx="128.4" cy="75.1" r=".51" fill="#008000" stroke="#008000" stroke-width=".2"/>
<circle cx="128.4" cy="75.1" r=".3" fill="#fff" stroke="#000" stroke-width=".2"/>
<circle cx="128.4" cy="79" r=".51" fill="#008000" stroke="#008000" stroke-width=".2"/>
<circle cx="128.4" cy="79" r=".3" fill="#fff" stroke="#000" stroke-width=".2"/>
<circle cx="142" cy="93.2" r=".51" fill="#008000" stroke="#008000" stroke-width=".2"/>
<circle cx="142" cy="93.2" r=".3" fill="#fff" stroke="#000" stroke-width=".2"/>
<circle cx="128.4" cy="98.3" r=".51" fill="#008000" stroke="#008000" stroke-width=".2"/>
<circle cx="128.4" cy="98.3" r=".3" fill="#fff" stroke="#000" stroke-width=".2"/>
<circle cx="147.8" cy="92.9" r=".51" fill="#008000" stroke="#008000" stroke-width=".2"/>
<circle cx="147.8" cy="92.9" r=".3" fill="#fff" stroke="#000" stroke-width=".2"/>
<circle cx="150.5" cy="98.8" r=".51" fill="#008000" stroke="#008000" stroke-width=".2"/>
<circle cx="150.5" cy="98.8" r=".3" fill="#fff" stroke="#000" stroke-width=".2"/>
<circle cx="177.1" cy="83" r=".51" fill="#008000" stroke="#008000" stroke-width=".2"/>
<circle cx="177.1" cy="83" r=".3" fill="#fff" stroke="#000" stroke-width=".2"/>
<circle cx="176.2" cy="78.7" r=".51" fill="#008000" stroke="#008000" stroke-width=".2"/>
<circle cx="176.2" cy="78.7" r=".3" fill="#fff" stroke="#000" stroke-width=".2"/>
<circle cx="185.2" cy="97.5" r=".51" fill="#008000" stroke="#008000" stroke-width=".2"/>
<circle cx="185.2" cy="97.5" r=".3" fill="#fff" stroke="#000" stroke-width=".2"/>
<circle cx="187.8" cy="95.3" r=".51" fill="#008000" stroke="#008000" stroke-width=".2"/>
<circle cx="187.8" cy="95.3" r=".3" fill="#fff" stroke="#000" stroke-width=".2"/>
<circle cx="177.3" cy="99" r=".51" fill="#008000" stroke="#008000" stroke-width=".2"/>
<circle cx="177.3" cy="99" r=".3" fill="#fff" stroke="#000" stroke-width=".2"/>
<circle cx="182.5" cy="99" r=".51" fill="#008000" stroke="#008000" stroke-width=".2"/>
<circle cx="182.5" cy="99" r=".3" fill="#fff" stroke="#000" stroke-width=".2"/>
<circle cx="175.7" cy="84.7" r=".51" fill="#008000" stroke="#008000" stroke-width=".2"/>
<circle cx="175.7" cy="84.7" r=".3" fill="#fff" stroke="#000" stroke-width=".2"/>
<circle cx="178.8" cy="111.7" r=".51" fill="#008000" stroke="#008000" stroke-width=".2"/>
<circle cx="178.8" cy="111.7" r=".3" fill="#fff" stroke="#000" stroke-width=".2"/>
<circle cx="138.6" cy="69.8" r=".51" fill="#008000" stroke="#008000" stroke-width=".2"/>
<circle cx="138.6" cy="69.8" r=".3" fill="#fff" stroke="#000" stroke-width=".2"/>
<circle cx="145.2" cy="82.3" r=".51" fill="#008000" stroke="#008000" stroke-width=".2"/>
<circle cx="145.2" cy="82.3" r=".3" fill="#fff" stroke="#000" stroke-width=".2"/>
<circle cx="150.5" cy="94.1" r=".51" fill="#008000" stroke="#008000" stroke-width=".2"/>
<circle cx="150.5" cy="94.1" r=".3" fill="#fff" stroke="#000" stroke-width=".2"/>
<circle cx="186.7" cy="65.7" r=".51" fill="#008000" stroke="#008000" stroke-width=".2"/>
<circle cx="186.7" cy="65.7" r=".3" fill="#fff" stroke="#000" stroke-width=".2"/>
<circle cx="177.4" cy="89.1" r=".51" fill="#008000" stroke="#008000" stroke-width=".2"/>
<circle cx="177.4" cy="89.1" r=".3" fill="#fff" stroke="#000" stroke-width=".2"/>
<circle cx="177.4" cy="92.6" r=".51" fill="#008000" stroke="#008000" stroke-width=".2"/>
<circle cx="177.4" cy="92.6" r=".3" fill="#fff" stroke="#000" stroke-width=".2"/>
<circle cx="106.2" cy="74.2" r=".51" fill="#008000" stroke="#008000" stroke-width=".2"/>
<circle cx="106.2" cy="74.2" r=".3" fill="#fff" stroke="#000" stroke-width=".2"/>
<circle cx="113.1" cy="66.4" r=".51" fill="#008000" stroke="#008000" stroke-width=".2"/>
<circle cx="113.1" cy="66.4" r=".3" fill="#fff" stroke="#000" stroke-width=".2"/>
<circle cx="173.7" cy="79.2" r=".51" fill="#008000" stroke="#008000" stroke-width=".2"/>
<circle cx="173.7" cy="79.2" r=".3" fill="#fff" stroke="#000" stroke-width=".2"/>
<circle cx="186.7" cy="73.5" r=".51" fill="#008000" stroke="#008000" stroke-width=".2"/>
<circle cx="186.7" cy="73.5" r=".3" fill="#fff" stroke="#000" stroke-width=".2"/>
<circle cx="185.3" cy="60.1" r="2.16" fill="#008000" stroke="#008000" stroke-width=".2"/>
<circle cx="185.3" cy="60.1" r="1.65" fill="#fff" stroke="#000" stroke-width=".2"/>
<circle cx="111.7" cy="60.1" r="2.16" fill="#008000" stroke="#008000" stroke-width=".2"/>
<circle cx="111.7" cy="60.1" r="1.65" fill="#fff" stroke="#000" stroke-width=".2"/>
<circle cx="107.9" cy="145.8" r="2.16" fill="#008000" stroke="#008000" stroke-width=".2"/>
<circle cx="107.9" cy="145.8" r="1.65" fill="#fff" stroke="#000" stroke-width=".2"/>
<circle cx="187.8" cy="145.8" r="2.16" fill="#008000" stroke="#008000" stroke-width=".2"/>
<circle cx="187.8" cy="145.8" r="1.65" fill="#fff" stroke="#000" stroke-width=".2"/>
<circle cx="113.6" cy="143.9" r=".51" fill="#008000" stroke="#008000" stroke-width=".2"/>
<circle cx="113.6" cy="143.9" r=".3" fill="#fff" stroke="#000" stroke-width=".2"/>
<circle cx="120.6" cy="145.9" r=".51" fill="#008000" stroke="#008000" stroke-width=".2"/>
<circle cx="120.6" cy="145.9" r=".3" fill="#fff" stroke="#000" stroke-width=".2"/>
<circle cx="127.6" cy="143.9" r=".51" fill="#008000" stroke="#008000" stroke-width=".2"/>
<circle cx="127.6" cy="143.9" r=".3" fill="#fff" stroke="#000" stroke-width=".2"/>
<circle cx="134.6" cy="145.9" r=".51" fill="#008000" stroke="#008000" stroke-width=".2"/>
<circle cx="134.6" cy="145.9" r=".3" fill="#fff" stroke="#000" stroke-width=".2"/>
<circle cx="141.6" cy="143.9" r=".51" fill="#008000" stroke="#008000" stroke-width=".2"/>
<circle cx="141.6" cy="143.9" r=".3" fill="#fff" stroke="#000" stroke-width=".2"/>
<circle cx="148.6" cy="145.9" r=".51" fill="#008000" stroke="#008000" stroke-width=".2"/>
<circle cx="148.6" cy="145.9" r=".3" fill="#fff" stroke="#000" stroke-width=".2"/>
<circle cx="155.6" cy="143.9" r=".51" fill="#008000" stroke="#008000" stroke-width=".2"/>
<circle cx="155.6" cy="143.9" r=".3" fill="#fff" stroke="#000" stroke-width=".2"/>
<circle cx="162.6" cy="145.9" r=".51" fill="#008000" stroke="#008000" stroke-width=".2"/>
<circle cx="162.6" cy="145.9" r=".3" fill="#fff" stroke="#000" stroke-width=".2"/>
<circle cx="169.6" cy="143.9" r=".51" fill="#008000" stroke="#008000" stroke-width=".2"/>
<circle cx="169.6" cy="143.9" r=".3" fill="#fff" stroke="#000" stroke-width=".2"/>
<circle cx="128.6" cy="135.9" r=".51" fill="#008000" stroke="#008000" stroke-width=".2"/>
<circle cx="128.6" cy="135.9" r=".3" fill="#fff" stroke="#000" stroke-width=".2"/>
<circle cx="128" cy="134.7" r=".51" fill="#008000" stroke="#008000" stroke-width=".2"/>
<circle cx="128" cy="134.7" r=".3" fill="#fff" stroke="#000" stroke-width=".2"/>
<circle cx="144.5" cy="134.9" r=".51" fill="#008000" stroke="#008000" stroke-width=".2"/>
<circle cx="144.5" cy="134.9" r=".3" fill="#fff" stroke="#000" stroke-width=".2"/>
<circle cx="145.1" cy="136.2" r=".51" fill="#008000" stroke="#008000" stroke-width=".2"/>
<circle cx="145.1" cy="136.2" r=".3" fill="#fff" stroke="#000" stroke-width=".2"/>
<g fill="#000080" stroke="#000080" stroke-width=".2">
<circle cx="102.6" cy="57.2" r=".25"/>
<circle cx="102.6" cy="58.1" r=".25"/>
<circle cx="102.6" cy="59" r=".25"/>
<circle cx="102.6" cy="59.9" r=".25"/>
<circle cx="102.6" cy="60.8" r=".25"/>
<circle cx="102.6" cy="61.7" r=".25"/>
<circle cx="102.6" cy="62.7" r=".25"/>
<circle cx="102.6" cy="63.6" r=".25"/>
<circle cx="102.6" cy="64.5" r=".25"/>
<circle cx="102.6" cy="65.4" r=".25"/>
<circle cx="102.6" cy="66.3" r=".25"/>
<circle cx="102.6" cy="67.3" r=".24"/>
<circle cx="102.6" cy="68.2" r=".25"/>
<circle cx="102.6" cy="69.1" r=".25"/>
<circle cx="102.6" cy="70" r=".25"/>
<circle cx="102.6" cy="70.9" r=".25"/>
<circle cx="102.6" cy="71.8" r=".25"/>
<circle cx="102.6" cy="72.8" r=".25"/>
<circle cx="102.6" cy="73.7" r=".25"/>
<circle cx="102.6" cy="74.6" r=".25"/>
<circle cx="102.6" cy="75.5" r=".25"/>
<circle cx="102.6" cy="76.4" r=".25"/>
<circle cx="102.6" cy="77.3" r=".25"/>
<circle cx="102.6" cy="78.3" r=".25"/>
<circle cx="102.6" cy="79.2" r=".25"/>
<circle cx="102.6" cy="80.1" r=".25"/>
<circle cx="102.6" cy="81" r=".25"/>
<circle cx="102.6" cy="81.9" r=".25"/>
<circle cx="102.6" cy="82.8" r=".25"/>
<circle cx="102.6" cy="83.8" r=".25"/>
<circle cx="102.6" cy="84.7" r=".25"/>
<circle cx="102.6" cy="85.6" r=".25"/>
<circle cx="102.6" cy="86.5" r=".25"/>
<circle cx="102.6" cy="87.4" r=".25"/>
<circle cx="102.6" cy="88.3" r=".25"/>
<circle cx="102.6" cy="89.3" r=".25"/>
<circle cx="102.6" cy="90.2" r=".25"/>
<circle cx="102.6" cy="91.1" r=".25"/>
<circle cx="102.6" cy="92" r=".25"/>
<circle cx="102.6" cy="92.9" r=".25"/>
<circle cx="102.6" cy="93.9" r=".25"/>
<circle cx="102.6" cy="94.8" r=".25"/>
<circle cx="102.6" cy="95.7" r=".25"/>
<circle cx="102.6" cy="96.6" r=".25"/>
<circle cx="102.6" cy="97.5" r=".25"/>
<circle cx="102.6" cy="98.4" r=".25"/>
<circle cx="102.6" cy="99.4" r=".25"/>
<circle cx="102.6" cy="100.3" r=".25"/>
<circle cx="102.6" cy="101.2" r=".25"/>
<circle cx="102.6" cy="102.1" r=".24"/>
<circle cx="102.6" cy="103" r=".25"/>
<circle cx="102.6" cy="103.9" r=".25"/>
<circle cx="102.6" cy="104.9" r=".24"/>
<circle cx="102.6" cy="105.8" r=".25"/>
<circle cx="102.6" cy="106.7" r=".25"/>
<circle cx="102.6" cy="107.6" r=".25"/>
<circle cx="102.6" cy="108.5" r=".25"/>
<circle cx="102.6" cy="109.5" r=".25"/>
<circle cx="102.6" cy="110.4" r=".25"/>
<circle cx="102.6" cy="111.3" r=".25"/>
<circle cx="102.6" cy="112.2" r=".25"/>
<circle cx="102.6" cy="113.1" r=".25"/>
<circle cx="102.6" cy="114" r=".25"/>
<circle cx="102.6" cy="115" r=".25"/>
<circle cx="102.6" cy="115.9" r=".25"/>
<circle cx="102.6" cy="116.8" r=".25"/>
<circle cx="102.6" cy="117.7" r=".25"/>
<circle cx="102.6" cy="118.6" r=".25"/>
<circle cx="102.6" cy="119.5" r=".25"/>
<circle cx="102.6" cy="120.5" r=".25"/>
<circle cx="102.6" cy="121.4" r=".25"/>
<circle cx="102.6" cy="122.3" r=".25"/>
<circle cx="102.6" cy="123.2" r=".25"/>
<circle cx="102.6" cy="124.1" r=".25"/>
<circle cx="102.6" cy="125.1" r=".25"/>
<circle cx="102.6" cy="126" r=".25"/>
<circle cx="102.6" cy="126.9" r=".25"/>
<circle cx="102.6" cy="127.8" r=".25"/>
<circle cx="102.6" cy="128.7" r=".25"/>
<circle cx="102.6" cy="129.6" r=".25"/>
<circle cx="102.6" cy="130.6" r=".25"/>
<circle cx="102.6" cy="131.5" r=".25"/>
<circle cx="102.6" cy="132.4" r=".25"/>
<circle cx="102.6" cy="133.3" r=".25"/>
<circle cx="102.6" cy="134.2" r=".25"/>
<circle cx="102.6" cy="135.1" r=".25"/>
<circle cx="102.6" cy="136.1" r=".25"/>
<circle cx="102.6" cy="137" r=".25"/>
<circle cx="102.6" cy="137.9" r=".25"/>
<circle cx="102.6" cy="138.8" r=".25"/>
<circle cx="102.6" cy="139.7" r=".24"/>
<circle cx="102.6" cy="140.7" r=".25"/>
<circle cx="102.6" cy="141.6" r=".25"/>
<circle cx="102.6" cy="142.5" r=".24"/>
<circle cx="102.6" cy="143.4" r=".25"/>
<circle cx="102.6" cy="144.3" r=".25"/>
<circle cx="102.6" cy="145.2" r=".25"/>
<circle cx="102.6" cy="146.2" r=".25"/>
<circle cx="102.6" cy="147.1" r=".25"/>
<circle cx="102.6" cy="148" r=".25"/>
<circle cx="102.6" cy="148.9" r=".25"/>
<circle cx="102.7" cy="149" r=".25"/>
<circle cx="103.6" cy="149" r=".25"/>
<circle cx="104.5" cy="149" r=".25"/>
<circle cx="105.4" cy="149" r=".25"/>
<circle cx="106.4" cy="149" r=".26"/>
<circle cx="107.3" cy="149" r=".25"/>
<circle cx="108.2" cy="149" r=".25"/>
<circle cx="109.1" cy="149" r=".25"/>
<circle cx="110" cy="149" r=".25"/>
<circle cx="111" cy="149" r=".25"/>
<circle cx="111.9" cy="149" r=".25"/>
<circle cx="112.8" cy="149" r=".26"/>
<circle cx="113.7" cy="149" r=".25"/>
<circle cx="114.7" cy="149" r=".25"/>
<circle cx="115.6" cy="149" r=".25"/>
<circle cx="116.5" cy="149" r=".25"/>
<circle cx="117.4" cy="149" r=".25"/>
<circle cx="118.3" cy="149" r=".25"/>
<circle cx="119.3" cy="149" r=".26"/>
<circle cx="120.2" cy="149" r=".25"/>
<circle cx="121.1" cy="149" r=".25"/>
<circle cx="122" cy="149" r=".25"/>
<circle cx="123" cy="149" r=".25"/>
<circle cx="123.9" cy="149" r=".26"/>
<circle cx="124.8" cy="149" r=".25"/>
<circle cx="125.7" cy="149" r=".26"/>
<circle cx="126.6" cy="149" r=".25"/>
<circle cx="127.6" cy="149" r=".25"/>
<circle cx="128.5" cy="149" r=".25"/>
<circle cx="129.4" cy="149" r=".25"/>
<circle cx="130.3" cy="149" r=".26"/>
<circle cx="131.3" cy="149" r=".25"/>
<circle cx="132.2" cy="149" r=".26"/>
<circle cx="133.1" cy="149" r=".25"/>
<circle cx="134" cy="149" r=".25"/>
<circle cx="134.9" cy="149" r=".25"/>
<circle cx="135.9" cy="149" r=".25"/>
<circle cx="136.8" cy="149" r=".26"/>
<circle cx="137.7" cy="149" r=".25"/>
<circle cx="138.6" cy="149" r=".25"/>
<circle cx="139.6" cy="149" r=".25"/>
<circle cx="140.5" cy="149" r=".25"/>
<circle cx="141.4" cy="149" r=".25"/>
<circle cx="142.3" cy="149" r=".25"/>
<circle cx="143.2" cy="149" r=".26"/>
<circle cx="144.2" cy="149" r=".25"/>
<circle cx="145.1" cy="149" r=".25"/>
<circle cx="146" cy="149" r=".25"/>
<circle cx="146.9" cy="149" r=".25"/>
<circle cx="147.8" cy="149" r=".25"/>
<circle cx="148.8" cy="149" r=".25"/>
<circle cx="149.7" cy="149" r=".26"/>
<circle cx="150.6" cy="149" r=".25"/>
<circle cx="151.6" cy="149" r=".25"/>
<circle cx="152.5" cy="149" r=".25"/>
<circle cx="153.4" cy="149" r=".25"/>
<circle cx="154.3" cy="149" r=".26"/>
<circle cx="155.2" cy="149" r=".25"/>
<circle cx="156.2" cy="149" r=".26"/>
<circle cx="157.1" cy="149" r=".25"/>
<circle cx="158" cy="149" r=".25"/>
<circle cx="158.9" cy="149" r=".25"/>
<circle cx="159.9" cy="149" r=".25"/>
<circle cx="160.8" cy="149" r=".26"/>
<circle cx="161.7" cy="149" r=".25"/>
<circle cx="162.6" cy="149" r=".25"/>
<circle cx="163.5" cy="149" r=".25"/>
<circle cx="164.5" cy="149" r=".25"/>
<circle cx="165.4" cy="149" r=".25"/>
<circle cx="166.3" cy="149" r=".25"/>
<circle cx="167.2" cy="149" r=".26"/>
<circle cx="168.1" cy="149" r=".25"/>
<circle cx="169.1" cy="149" r=".25"/>
<circle cx="170" cy="149" r=".25"/>
<circle cx="170.9" cy="149" r=".25"/>
<circle cx="171.8" cy="149" r=".25"/>
<circle cx="172.8" cy="149" r=".25"/>
<circle cx="173.7" cy="149" r=".26"/>
<circle cx="174.6" cy="149" r=".25"/>
<circle cx="175.5" cy="149" r=".25"/>
<circle cx="176.4" cy="149" r=".25"/>
<circle cx="177.4" cy="149" r=".25"/>
<circle cx="178.3" cy="149" r=".26"/>
<circle cx="179.2" cy="149" r=".25"/>
<circle cx="180.1" cy="149" r=".26"/>
<circle cx="181.1" cy="149" r=".25"/>
<circle cx="182" cy="149" r=".25"/>
<circle cx="182.9" cy="149" r=".25"/>
<circle cx="183.8" cy="149" r=".25"/>
<circle cx="184.8" cy="149" r=".26"/>
<circle cx="185.7" cy="149" r=".25"/>
<circle cx="186.6" cy="149" r=".25"/>
<circle cx="187.5" cy="149" r=".25"/>
<circle cx="188.4" cy="149" r=".25"/>
<circle cx="189.4" cy="149" r=".25"/>
<circle cx="190.3" cy="149" r=".25"/>
<circle cx="191.2" cy="149" r=".26"/>
<circle cx="192.1" cy="149" r=".25"/>
<circle cx="193.1" cy="149" r=".25"/>
<circle cx="193.1" cy="148.9" r=".25"/>
<circle cx="193.1" cy="148" r=".25"/>
<circle cx="193.1" cy="147.1" r=".25"/>
<circle cx="193.1" cy="146.2" r=".25"/>
<circle cx="193.1" cy="145.2" r=".25"/>
<circle cx="193.1" cy="144.3" r=".25"/>
<circle cx="193.1" cy="143.4" r=".25"/>
<circle cx="193.1" cy="142.5" r=".24"/>
<circle cx="193.1" cy="141.6" r=".25"/>
<circle cx="193.1" cy="140.7" r=".25"/>
<circle cx="193.1" cy="139.7" r=".24"/>
<circle cx="193.1" cy="138.8" r=".25"/>
<circle cx="193.1" cy="137.9" r=".25"/>
<circle cx="193.1" cy="137" r=".25"/>
<circle cx="193.1" cy="136.1" r=".25"/>
<circle cx="193.1" cy="135.1" r=".25"/>
<circle cx="193.1" cy="134.2" r=".25"/>
<circle cx="193.1" cy="133.3" r=".25"/>
<circle cx="193.1" cy="132.4" r=".25"/>
<circle cx="193.1" cy="131.5" r=".25"/>
<circle cx="193.1" cy="130.6" r=".25"/>
<circle cx="193.1" cy="129.6" r=".25"/>
<circle cx="193.1" cy="128.7" r=".25"/>
<circle cx="193.1" cy="127.8" r=".25"/>
<circle cx="193.1" cy="126.9" r=".25"/>
<circle cx="193.1" cy="126" r=".25"/>
<circle cx="193.1" cy="125.1" r=".25"/>
<circle cx="193.1" cy="124.1" r=".25"/>
<circle cx="193.1" cy="123.2" r=".25"/>
<circle cx="193.1" cy="122.3" r=".25"/>
<circle cx="193.1" cy="121.4" r=".25"/>
<circle cx="193.1" cy="120.5" r=".25"/>
<circle cx="193.1" cy="119.5" r=".25"/>
<circle cx="193.1" cy="118.6" r=".25"/>
<circle cx="193.1" cy="117.7" r=".25"/>
<circle cx="193.1" cy="116.8" r=".25"/>
<circle cx="193.1" cy="115.9" r=".25"/>
<circle cx="193.1" cy="115" r=".25"/>
<circle cx="193.1" cy="114" r=".25"/>
<circle cx="193.1" cy="113.1" r=".25"/>
<circle cx="193.1" cy="112.2" r=".25"/>
<circle cx="193.1" cy="111.3" r=".25"/>
<circle cx="193.1" cy="110.4" r=".25"/>
<circle cx="193.1" cy="109.5" r=".25"/>
<circle cx="193.1" cy="108.5" r=".25"/>
<circle cx="193.1" cy="107.6" r=".25"/>
<circle cx="193.1" cy="106.7" r=".25"/>
<circle cx="193.1" cy="105.8" r=".25"/>
<circle cx="193.1" cy="104.9" r=".24"/>
<circle cx="193.1" cy="103.9" r=".25"/>
<circle cx="193.1" cy="103" r=".25"/>
<circle cx="193.1" cy="102.1" r=".24"/>
<circle cx="193.1" cy="101.2" r=".25"/>
<circle cx="193.1" cy="100.3" r=".25"/>
<circle cx="193.1" cy="99.4" r=".25"/>
<circle cx="193.1" cy="98.4" r=".25"/>
<circle cx="193.1" cy="97.5" r=".25"/>
<circle cx="193.1" cy="96.6" r=".25"/>
<circle cx="193.1" cy="95.7" r=".25"/>
<circle cx="193.1" cy="94.8" r=".25"/>
<circle cx="193.1" cy="93.9" r=".25"/>
<circle cx="193.1" cy="92.9" r=".25"/>
<circle cx="193.1" cy="92" r=".25"/>
<circle cx="193.1" cy="91.1" r=".25"/>
<circle cx="193.1" cy="90.2" r=".25"/>
<circle cx="193.1" cy="89.3" r=".25"/>
<circle cx="193.1" cy="88.3" r=".25"/>
<circle cx="193.1" cy="87.4" r=".25"/>
<circle cx="193.1" cy="86.5" r=".25"/>
<circle cx="193.1" cy="85.6" r=".25"/>
<circle cx="193.1" cy="84.7" r=".25"/>
<circle cx="193.1" cy="83.8" r=".25"/>
<circle cx="193.1" cy="82.8" r=".25"/>
<circle cx="193.1" cy="81.9" r=".25"/>
<circle cx="193.1" cy="81" r=".25"/>
<circle cx="193.1" cy="80.1" r=".25"/>
<circle cx="193.1" cy="79.2" r=".25"/>
<circle cx="193.1" cy="78.3" r=".25"/>
<circle cx="193.1" cy="77.3" r=".25"/>
<circle cx="193.1" cy="76.4" r=".25"/>
<circle cx="193.1" cy="75.5" r=".25"/>
<circle cx="193.1" cy="74.6" r=".25"/>
<circle cx="193.1" cy="73.7" r=".25"/>
<circle cx="193.1" cy="72.8" r=".25"/>
<circle cx="193.1" cy="71.8" r=".25"/>
<circle cx="193.1" cy="70.9" r=".25"/>
<circle cx="193.1" cy="70" r=".25"/>
<circle cx="193.1" cy="69.1" r=".25"/>
<circle cx="193.1" cy="68.2" r=".25"/>
<circle cx="193.1" cy="67.3" r=".24"/>
<circle cx="193.1" cy="66.3" r=".25"/>
<circle cx="193.1" cy="65.4" r=".25"/>
<circle cx="193.1" cy="64.5" r=".25"/>
<circle cx="193.1" cy="63.6" r=".25"/>
<circle cx="193.1" cy="62.7" r=".25"/>
<circle cx="193.1" cy="61.7" r=".25"/>
<circle cx="193.1" cy="60.8" r=".25"/>
<circle cx="193.1" cy="59.9" r=".25"/>
<circle cx="193.1" cy="59" r=".25"/>
<circle cx="193.1" cy="58.1" r=".25"/>
<circle cx="193.1" cy="57.2" r=".25"/>
<circle cx="193.1" cy="57.1" r=".25"/>
<circle cx="192.1" cy="57.1" r=".25"/>
<circle cx="191.2" cy="57.1" r=".26"/>
<circle cx="190.3" cy="57.1" r=".25"/>
<circle cx="189.4" cy="57.1" r=".25"/>
<circle cx="188.4" cy="57.1" r=".25"/>
<circle cx="187.5" cy="57.1" r=".25"/>
<circle cx="186.6" cy="57.1" r=".25"/>
<circle cx="185.7" cy="57.1" r=".25"/>
<circle cx="184.8" cy="57.1" r=".26"/>
<circle cx="183.8" cy="57.1" r=".25"/>
<circle cx="182.9" cy="57.1" r=".25"/>
<circle cx="182" cy="57.1" r=".25"/>
<circle cx="181.1" cy="57.1" r=".25"/>
<circle cx="180.1" cy="57.1" r=".26"/>
<circle cx="179.2" cy="57.1" r=".25"/>
<circle cx="178.3" cy="57.1" r=".26"/>
<circle cx="177.4" cy="57.1" r=".25"/>
<circle cx="176.4" cy="57.1" r=".25"/>
<circle cx="175.5" cy="57.1" r=".25"/>
<circle cx="174.6" cy="57.1" r=".25"/>
<circle cx="173.7" cy="57.1" r=".26"/>
<circle cx="172.8" cy="57.1" r=".25"/>
<circle cx="171.8" cy="57.1" r=".25"/>
<circle cx="170.9" cy="57.1" r=".25"/>
<circle cx="170" cy="57.1" r=".25"/>
<circle cx="169.1" cy="57.1" r=".25"/>
<circle cx="168.1" cy="57.1" r=".25"/>
<circle cx="167.2" cy="57.1" r=".26"/>
<circle cx="166.3" cy="57.1" r=".25"/>
<circle cx="165.4" cy="57.1" r=".25"/>
<circle cx="164.5" cy="57.1" r=".25"/>
<circle cx="163.5" cy="57.1" r=".25"/>
<circle cx="162.6" cy="57.1" r=".25"/>
<circle cx="161.7" cy="57.1" r=".25"/>
<circle cx="160.8" cy="57.1" r=".26"/>
<circle cx="159.9" cy="57.1" r=".25"/>
<circle cx="158.9" cy="57.1" r=".25"/>
<circle cx="158" cy="57.1" r=".25"/>
<circle cx="157.1" cy="57.1" r=".25"/>
<circle cx="156.2" cy="57.1" r=".26"/>
<circle cx="155.2" cy="57.1" r=".25"/>
<circle cx="154.3" cy="57.1" r=".26"/>
<circle cx="153.4" cy="57.1" r=".25"/>
<circle cx="152.5" cy="57.1" r=".25"/>
<circle cx="151.6" cy="57.1" r=".25"/>
<circle cx="150.6" cy="57.1" r=".25"/>
<circle cx="149.7" cy="57.1" r=".26"/>
<circle cx="148.8" cy="57.1" r=".25"/>
<circle cx="147.8" cy="57.1" r=".25"/>
<circle cx="146.9" cy="57.1" r=".25"/>
<circle cx="146" cy="57.1" r=".25"/>
<circle cx="145.1" cy="57.1" r=".25"/>
<circle cx="144.2" cy="57.1" r=".25"/>
<circle cx="143.2" cy="57.1" r=".26"/>
<circle cx="142.3" cy="57.1" r=".25"/>
<circle cx="141.4" cy="57.1" r=".25"/>
<circle cx="140.5" cy="57.1" r=".25"/>
<circle cx="139.6" cy="57.1" r=".25"/>
<circle cx="138.6" cy="57.1" r=".25"/>
<circle cx="137.7" cy="57.1" r=".25"/>
<circle cx="136.8" cy="57.1" r=".26"/>
<circle cx="135.9" cy="57.1" r=".25"/>
<circle cx="134.9" cy="57.1" r=".25"/>
<circle cx="134" cy="57.1" r=".25"/>
<circle cx="133.1" cy="57.1" r=".25"/>
<circle cx="132.2" cy="57.1" r=".26"/>
<circle cx="131.3" cy="57.1" r=".25"/>
<circle cx="130.3" cy="57.1" r=".26"/>
<circle cx="129.4" cy="57.1" r=".25"/>
<circle cx="128.5" cy="57.1" r=".25"/>
<circle cx="127.6" cy="57.1" r=".25"/>
<circle cx="126.6" cy="57.1" r=".25"/>
<circle cx="125.7" cy="57.1" r=".26"/>
<circle cx="124.8" cy="57.1" r=".25"/>
<circle cx="123.9" cy="57.1" r=".26"/>
<circle cx="123" cy="57.1" r=".25"/>
<circle cx="122" cy="57.1" r=".25"/>
<circle cx="121.1" cy="57.1" r=".25"/>
<circle cx="120.2" cy="57.1" r=".25"/>
<circle cx="119.3" cy="57.1" r=".26"/>
<circle cx="118.3" cy="57.1" r=".25"/>
<circle cx="117.4" cy="57.1" r=".25"/>
<circle cx="116.5" cy="57.1" r=".25"/>
<circle cx="115.6" cy="57.1" r=".25"/>
<circle cx="114.7" cy="57.1" r=".25"/>
<circle cx="113.7" cy="57.1" r=".25"/>
<circle cx="112.8" cy="57.1" r=".26"/>
<circle cx="111.9" cy="57.1" r=".25"/>
<circle cx="111" cy="57.1" r=".25"/>
<circle cx="110" cy="57.1" r=".25"/>
<circle cx="109.1" cy="57.1" r=".25"/>
<circle cx="108.2" cy="57.1" r=".25"/>
<circle cx="107.3" cy="57.1" r=".25"/>
<circle cx="106.4" cy="57.1" r=".26"/>
<circle cx="105.4" cy="57.1" r=".25"/>
<circle cx="104.5" cy="57.1" r=".25"/>
<circle cx="103.6" cy="57.1" r=".25"/>
<circle cx="102.7" cy="57.1" r=".25"/>
</g>
<circle cx="117" cy="62.5" r=".76" fill="#008000" stroke="#008000" stroke-width=".2"/>
<circle cx="117" cy="62.5" r=".51" fill="#fff" stroke="#000" stroke-width=".2"/>
<circle cx="117" cy="60" r=".76" fill="#008000" stroke="#008000" stroke-width=".2"/>
<circle cx="117" cy="60" r=".51" fill="#fff" stroke="#000" stroke-width=".2"/>
<circle cx="119.5" cy="62.5" r=".76" fill="#008000" stroke="#008000" stroke-width=".2"/>
<circle cx="119.5" cy="62.5" r=".51" fill="#fff" stroke="#000" stroke-width=".2"/>
<circle cx="119.5" cy="60" r=".76" fill="#008000" stroke="#008000" stroke-width=".2"/>
<circle cx="119.5" cy="60" r=".51" fill="#fff" stroke="#000" stroke-width=".2"/>
<circle cx="122.1" cy="62.5" r=".76" fill="#008000" stroke="#008000" stroke-width=".2"/>
<circle cx="122.1" cy="62.5" r=".51" fill="#fff" stroke="#000" stroke-width=".2"/>
<circle cx="122.1" cy="60" r=".76" fill="#008000" stroke="#008000" stroke-width=".2"/>
<circle cx="122.1" cy="60" r=".51" fill="#fff" stroke="#000" stroke-width=".2"/>
<circle cx="124.6" cy="62.5" r=".76" fill="#008000" stroke="#008000" stroke-width=".2"/>
<circle cx="124.6" cy="62.5" r=".51" fill="#fff" stroke="#000" stroke-width=".2"/>
<circle cx="124.6" cy="60" r=".76" fill="#008000" stroke="#008000" stroke-width=".2"/>
<circle cx="124.6" cy="60" r=".51" fill="#fff" stroke="#000" stroke-width=".2"/>
<circle cx="127.1" cy="62.5" r=".76" fill="#008000" stroke="#008000" stroke-width=".2"/>
<circle cx="127.1" cy="62.5" r=".51" fill="#fff" stroke="#000" stroke-width=".2"/>
<circle cx="127.1" cy="60" r=".76" fill="#008000" stroke="#008000" stroke-width=".2"/>
<circle cx="127.1" cy="60" r=".51" fill="#fff" stroke="#000" stroke-width=".2"/>
<circle cx="129.7" cy="62.5" r=".76" fill="#008000" stroke="#008000" stroke-width=".2"/>
<circle cx="129.7" cy="62.5" r=".51" fill="#fff" stroke="#000" stroke-width=".2"/>
<circle cx="129.7" cy="60" r=".76" fill="#008000" stroke="#008000" stroke-width=".2"/>
<circle cx="129.7" cy="60" r=".51" fill="#fff" stroke="#000" stroke-width=".2"/>
<circle cx="132.2" cy="62.5" r=".76" fill="#008000" stroke="#008000" stroke-width=".2"/>
<circle cx="132.2" cy="62.5" r=".51" fill="#fff" stroke="#000" stroke-width=".2"/>
<circle cx="132.2" cy="60" r=".76" fill="#008000" stroke="#008000" stroke-width=".2"/>
<circle cx="132.2" cy="60" r=".51" fill="#fff" stroke="#000" stroke-width=".2"/>
<circle cx="134.8" cy="62.5" r=".76" fill="#008000" stroke="#008000" stroke-width=".2"/>
<circle cx="134.8" cy="62.5" r=".51" fill="#fff" stroke="#000" stroke-width=".2"/>
<circle cx="134.8" cy="60" r=".76" fill="#008000" stroke="#008000" stroke-width=".2"/>
<circle cx="134.8" cy="60" r=".51" fill="#fff" stroke="#000" stroke-width=".2"/>
<circle cx="137.3" cy="62.5" r=".76" fill="#008000" stroke="#008000" stroke-width=".2"/>
<circle cx="137.3" cy="62.5" r=".51" fill="#fff" stroke="#000" stroke-width=".2"/>
<circle cx="137.3" cy="60" r=".76" fill="#008000" stroke="#008000" stroke-width=".2"/>
<circle cx="137.3" cy="60" r=".51" fill="#fff" stroke="#000" stroke-width=".2"/>
<circle cx="139.8" cy="62.5" r=".76" fill="#008000" stroke="#008000" stroke-width=".2"/>
<circle cx="139.8" cy="62.5" r=".51" fill="#fff" stroke="#000" stroke-width=".2"/>
<circle cx="139.8" cy="60" r=".76" fill="#008000" stroke="#008000" stroke-width=".2"/>
<circle cx="139.8" cy="60" r=".51" fill="#fff" stroke="#000" stroke-width=".2"/>
<circle cx="142.4" cy="62.5" r=".76" fill="#008000" stroke="#008000" stroke-width=".2"/>
<circle cx="142.4" cy="62.5" r=".51" fill="#fff" stroke="#000" stroke-width=".2"/>
<circle cx="142.4" cy="60" r=".76" fill="#008000" stroke="#008000" stroke-width=".2"/>
<circle cx="142.4" cy="60" r=".51" fill="#fff" stroke="#000" stroke-width=".2"/>
<circle cx="144.9" cy="62.5" r=".76" fill="#008000" stroke="#008000" stroke-width=".2"/>
<circle cx="144.9" cy="62.5" r=".51" fill="#fff" stroke="#000" stroke-width=".2"/>
<circle cx="144.9" cy="60" r=".76" fill="#008000" stroke="#008000" stroke-width=".2"/>
<circle cx="144.9" cy="60" r=".51" fill="#fff" stroke="#000" stroke-width=".2"/>
<circle cx="147.5" cy="62.5" r=".76" fill="#008000" stroke="#008000" stroke-width=".2"/>
<circle cx="147.5" cy="62.5" r=".51" fill="#fff" stroke="#000" stroke-width=".2"/>
<circle cx="147.5" cy="60" r=".76" fill="#008000" stroke="#008000" stroke-width=".2"/>
<circle cx="147.5" cy="60" r=".51" fill="#fff" stroke="#000" stroke-width=".2"/>
<circle cx="150" cy="62.5" r=".76" fill="#008000" stroke="#008000" stroke-width=".2"/>
<circle cx="150" cy="62.5" r=".51" fill="#fff" stroke="#000" stroke-width=".2"/>
<circle cx="150" cy="60" r=".76" fill="#008000" stroke="#008000" stroke-width=".2"/>
<circle cx="150" cy="60" r=".51" fill="#fff" stroke="#000" stroke-width=".2"/>
<circle cx="152.5" cy="62.5" r=".76" fill="#008000" stroke="#008000" stroke-width=".2"/>
<circle cx="152.5" cy="62.5" r=".51" fill="#fff" stroke="#000" stroke-width=".2"/>
<circle cx="152.5" cy="60" r=".76" fill="#008000" stroke="#008000" stroke-width=".2"/>
<circle cx="152.5" cy="60" r=".51" fill="#fff" stroke="#000" stroke-width=".2"/>
<circle cx="155.1" cy="62.5" r=".76" fill="#008000" stroke="#008000" stroke-width=".2"/>
<circle cx="155.1" cy="62.5" r=".51" fill="#fff" stroke="#000" stroke-width=".2"/>
<circle cx="155.1" cy="60" r=".76" fill="#008000" stroke="#008000" stroke-width=".2"/>
<circle cx="155.1" cy="60" r=".51" fill="#fff" stroke="#000" stroke-width=".2"/>
<circle cx="157.6" cy="62.5" r=".76" fill="#008000" stroke="#008000" stroke-width=".2"/>
<circle cx="157.6" cy="62.5" r=".51" fill="#fff" stroke="#000" stroke-width=".2"/>
<circle cx="157.6" cy="60" r=".76" fill="#008000" stroke="#008000" stroke-width=".2"/>
<circle cx="157.6" cy="60" r=".51" fill="#fff" stroke="#000" stroke-width=".2"/>
<circle cx="160.1" cy="62.5" r=".76" fill="#008000" stroke="#008000" stroke-width=".2"/>
<circle cx="160.1" cy="62.5" r=".51" fill="#fff" stroke="#000" stroke-width=".2"/>
<circle cx="160.1" cy="60" r=".76" fill="#008000" stroke="#008000" stroke-width=".2"/>
<circle cx="160.1" cy="60" r=".51" fill="#fff" stroke="#000" stroke-width=".2"/>
<circle cx="162.7" cy="62.5" r=".76" fill="#008000" stroke="#008000" stroke-width=".2"/>
<circle cx="162.7" cy="62.5" r=".51" fill="#fff" stroke="#000" stroke-width=".2"/>
<circle cx="162.7" cy="60" r=".76" fill="#008000" stroke="#008000" stroke-width=".2"/>
<circle cx="162.7" cy="60" r=".51" fill="#fff" stroke="#000" stroke-width=".2"/>
<circle cx="165.2" cy="62.5" r=".76" fill="#008000" stroke="#008000" stroke-width=".2"/>
<circle cx="165.2" cy="62.5" r=".51" fill="#fff" stroke="#000" stroke-width=".2"/>
<circle cx="165.2" cy="60" r=".76" fill="#008000" stroke="#008000" stroke-width=".2"/>
<circle cx="165.2" cy="60" r=".51" fill="#fff" stroke="#000" stroke-width=".2"/>
<circle cx="167.8" cy="62.5" r=".76" fill="#008000" stroke="#008000" stroke-width=".2"/>
<circle cx="167.8" cy="62.5" r=".51" fill="#fff" stroke="#000" stroke-width=".2"/>
<circle cx="167.8" cy="60" r=".76" fill="#008000" stroke="#008000" stroke-width=".2"/>
<circle cx="167.8" cy="60" r=".51" fill="#fff" stroke="#000" stroke-width=".2"/>
<circle cx="170.3" cy="62.5" r=".76" fill="#008000" stroke="#008000" stroke-width=".2"/>
<circle cx="170.3" cy="62.5" r=".51" fill="#fff" stroke="#000" stroke-width=".2"/>
<circle cx="170.3" cy="60" r=".76" fill="#008000" stroke="#008000" stroke-width=".2"/>
<circle cx="170.3" cy="60" r=".51" fill="#fff" stroke="#000" stroke-width=".2"/>
<circle cx="172.8" cy="62.5" r=".76" fill="#008000" stroke="#008000" stroke-width=".2"/>
<circle cx="172.8" cy="62.5" r=".51" fill="#fff" stroke="#000" stroke-width=".2"/>
<circle cx="172.8" cy="60" r=".76" fill="#008000" stroke="#008000" stroke-width=".2"/>
<circle cx="172.8" cy="60" r=".51" fill="#fff" stroke="#000" stroke-width=".2"/>
<circle cx="175.4" cy="62.5" r=".76" fill="#008000" stroke="#008000" stroke-width=".2"/>
<circle cx="175.4" cy="62.5" r=".51" fill="#fff" stroke="#000" stroke-width=".2"/>
<circle cx="175.4" cy="60" r=".76" fill="#008000" stroke="#008000" stroke-width=".2"/>
<circle cx="175.4" cy="60" r=".51" fill="#fff" stroke="#000" stroke-width=".2"/>
<circle cx="177.9" cy="62.5" r=".76" fill="#008000" stroke="#008000" stroke-width=".2"/>
<circle cx="177.9" cy="62.5" r=".51" fill="#fff" stroke="#000" stroke-width=".2"/>
<circle cx="177.9" cy="60" r=".76" fill="#008000" stroke="#008000" stroke-width=".2"/>
<circle cx="177.9" cy="60" r=".51" fill="#fff" stroke="#000" stroke-width=".2"/>
<circle cx="180.5" cy="62.5" r=".76" fill="#008000" stroke="#008000" stroke-width=".2"/>
<circle cx="180.5" cy="62.5" r=".51" fill="#fff" stroke="#000" stroke-width=".2"/>
<circle cx="180.5" cy="60" r=".76" fill="#008000" stroke="#008000" stroke-width=".2"/>
<circle cx="180.5" cy="60" r=".51" fill="#fff" stroke="#000" stroke-width=".2"/>
<circle cx="117" cy="67.6" r=".76" fill="#008000" stroke="#008000" stroke-width=".2"/>
<circle cx="117" cy="67.6" r=".51" fill="#fff" stroke="#000" stroke-width=".2"/>
<circle cx="117" cy="65.1" r=".76" fill="#008000" stroke="#008000" stroke-width=".2"/>
<circle cx="117" cy="65.1" r=".51" fill="#fff" stroke="#000" stroke-width=".2"/>
<circle cx="119.5" cy="67.6" r=".76" fill="#008000" stroke="#008000" stroke-width=".2"/>
<circle cx="119.5" cy="67.6" r=".51" fill="#fff" stroke="#000" stroke-width=".2"/>
<circle cx="119.5" cy="65.1" r=".76" fill="#008000" stroke="#008000" stroke-width=".2"/>
<circle cx="119.5" cy="65.1" r=".51" fill="#fff" stroke="#000" stroke-width=".2"/>
<circle cx="122.1" cy="67.6" r=".76" fill="#008000" stroke="#008000" stroke-width=".2"/>
<circle cx="122.1" cy="67.6" r=".51" fill="#fff" stroke="#000" stroke-width=".2"/>
<circle cx="122.1" cy="65.1" r=".76" fill="#008000" stroke="#008000" stroke-width=".2"/>
<circle cx="122.1" cy="65.1" r=".51" fill="#fff" stroke="#000" stroke-width=".2"/>
<circle cx="124.6" cy="67.6" r=".76" fill="#008000" stroke="#008000" stroke-width=".2"/>
<circle cx="124.6" cy="67.6" r=".51" fill="#fff" stroke="#000" stroke-width=".2"/>
<circle cx="124.6" cy="65.1" r=".76" fill="#008000" stroke="#008000" stroke-width=".2"/>
<circle cx="124.6" cy="65.1" r=".51" fill="#fff" stroke="#000" stroke-width=".2"/>
<circle cx="127.1" cy="67.6" r=".76" fill="#008000" stroke="#008000" stroke-width=".2"/>
<circle cx="127.1" cy="67.6" r=".51" fill="#fff" stroke="#000" stroke-width=".2"/>
<circle cx="127.1" cy="65.1" r=".76" fill="#008000" stroke="#008000" stroke-width=".2"/>
<circle cx="127.1" cy="65.1" r=".51" fill="#fff" stroke="#000" stroke-width=".2"/>
<circle cx="129.7" cy="67.6" r=".76" fill="#008000" stroke="#008000" stroke-width=".2"/>
<circle cx="129.7" cy="67.6" r=".51" fill="#fff" stroke="#000" stroke-width=".2"/>
<circle cx="129.7" cy="65.1" r=".76" fill="#008000" stroke="#008000" stroke-width=".2"/>
<circle cx="129.7" cy="65.1" r=".51" fill="#fff" stroke="#000" stroke-width=".2"/>
<circle cx="132.2" cy="67.6" r=".76" fill="#008000" stroke="#008000" stroke-width=".2"/>
<circle cx="132.2" cy="67.6" r=".51" fill="#fff" stroke="#000" stroke-width=".2"/>
<circle cx="132.2" cy="65.1" r=".76" fill="#008000" stroke="#008000" stroke-width=".2"/>
<circle cx="132.2" cy="65.1" r=".51" fill="#fff" stroke="#000" stroke-width=".2"/>
<circle cx="134.8" cy="67.6" r=".76" fill="#008000" stroke="#008000" stroke-width=".2"/>
<circle cx="134.8" cy="67.6" r=".51" fill="#fff" stroke="#000" stroke-width=".2"/>
<circle cx="134.8" cy="65.1" r=".76" fill="#008000" stroke="#008000" stroke-width=".2"/>
<circle cx="134.8" cy="65.1" r=".51" fill="#fff" stroke="#000" stroke-width=".2"/>
<circle cx="137.3" cy="67.6" r=".76" fill="#008000" stroke="#008000" stroke-width=".2"/>
<circle cx="137.3" cy="67.6" r=".51" fill="#fff" stroke="#000" stroke-width=".2"/>
<circle cx="137.3" cy="65.1" r=".76" fill="#008000" stroke="#008000" stroke-width=".2"/>
<circle cx="137.3" cy="65.1" r=".51" fill="#fff" stroke="#000" stroke-width=".2"/>
<circle cx="139.8" cy="67.6" r=".76" fill="#008000" stroke="#008000" stroke-width=".2"/>
<circle cx="139.8" cy="67.6" r=".51" fill="#fff" stroke="#000" stroke-width=".2"/>
<circle cx="139.8" cy="65.1" r=".76" fill="#008000" stroke="#008000" stroke-width=".2"/>
<circle cx="139.8" cy="65.1" r=".51" fill="#fff" stroke="#000" stroke-width=".2"/>
<circle cx="142.4" cy="67.6" r=".76" fill="#008000" stroke="#008000" stroke-width=".2"/>
<circle cx="142.4" cy="67.6" r=".51" fill="#fff" stroke="#000" stroke-width=".2"/>
<circle cx="142.4" cy="65.1" r=".76" fill="#008000" stroke="#008000" stroke-width=".2"/>
<circle cx="142.4" cy="65.1" r=".51" fill="#fff" stroke="#000" stroke-width=".2"/>
<circle cx="144.9" cy="67.6" r=".76" fill="#008000" stroke="#008000" stroke-width=".2"/>
<circle cx="144.9" cy="67.6" r=".51" fill="#fff" stroke="#000" stroke-width=".2"/>
<circle cx="144.9" cy="65.1" r=".76" fill="#008000" stroke="#008000" stroke-width=".2"/>
<circle cx="144.9" cy="65.1" r=".51" fill="#fff" stroke="#000" stroke-width=".2"/>
<circle cx="147.4" cy="67.6" r=".76" fill="#008000" stroke="#008000" stroke-width=".2"/>
<circle cx="147.4" cy="67.6" r=".51" fill="#fff" stroke="#000" stroke-width=".2"/>
<circle cx="147.4" cy="65.1" r=".76" fill="#008000" stroke="#008000" stroke-width=".2"/>
<circle cx="147.4" cy="65.1" r=".51" fill="#fff" stroke="#000" stroke-width=".2"/>
<circle cx="150" cy="67.6" r=".76" fill="#008000" stroke="#008000" stroke-width=".2"/>
<circle cx="150" cy="67.6" r=".51" fill="#fff" stroke="#000" stroke-width=".2"/>
<circle cx="150" cy="65.1" r=".76" fill="#008000" stroke="#008000" stroke-width=".2"/>
<circle cx="150" cy="65.1" r=".51" fill="#fff" stroke="#000" stroke-width=".2"/>
<circle cx="152.5" cy="67.6" r=".76" fill="#008000" stroke="#008000" stroke-width=".2"/>
<circle cx="152.5" cy="67.6" r=".51" fill="#fff" stroke="#000" stroke-width=".2"/>
<circle cx="152.5" cy="65.1" r=".76" fill="#008000" stroke="#008000" stroke-width=".2"/>
<circle cx="152.5" cy="65.1" r=".51" fill="#fff" stroke="#000" stroke-width=".2"/>
<circle cx="155.1" cy="67.6" r=".76" fill="#008000" stroke="#008000" stroke-width=".2"/>
<circle cx="155.1" cy="67.6" r=".51" fill="#fff" stroke="#000" stroke-width=".2"/>
<circle cx="155.1" cy="65.1" r=".76" fill="#008000" stroke="#008000" stroke-width=".2"/>
<circle cx="155.1" cy="65.1" r=".51" fill="#fff" stroke="#000" stroke-width=".2"/>
<circle cx="157.6" cy="67.6" r=".76" fill="#008000" stroke="#008000" stroke-width=".2"/>
<circle cx="157.6" cy="67.6" r=".51" fill="#fff" stroke="#000" stroke-width=".2"/>
<circle cx="157.6" cy="65.1" r=".76" fill="#008000" stroke="#008000" stroke-width=".2"/>
<circle cx="157.6" cy="65.1" r=".51" fill="#fff" stroke="#000" stroke-width=".2"/>
<circle cx="160.1" cy="67.6" r=".76" fill="#008000" stroke="#008000" stroke-width=".2"/>
<circle cx="160.1" cy="67.6" r=".51" fill="#fff" stroke="#000" stroke-width=".2"/>
<circle cx="160.1" cy="65.1" r=".76" fill="#008000" stroke="#008000" stroke-width=".2"/>
<circle cx="160.1" cy="65.1" r=".51" fill="#fff" stroke="#000" stroke-width=".2"/>
<circle cx="162.7" cy="67.6" r=".76" fill="#008000" stroke="#008000" stroke-width=".2"/>
<circle cx="162.7" cy="67.6" r=".51" fill="#fff" stroke="#000" stroke-width=".2"/>
<circle cx="162.7" cy="65.1" r=".76" fill="#008000" stroke="#008000" stroke-width=".2"/>
<circle cx="162.7" cy="65.1" r=".51" fill="#fff" stroke="#000" stroke-width=".2"/>
<circle cx="165.2" cy="67.6" r=".76" fill="#008000" stroke="#008000" stroke-width=".2"/>
<circle cx="165.2" cy="67.6" r=".51" fill="#fff" stroke="#000" stroke-width=".2"/>
<circle cx="165.2" cy="65.1" r=".76" fill="#008000" stroke="#008000" stroke-width=".2"/>
<circle cx="165.2" cy="65.1" r=".51" fill="#fff" stroke="#000" stroke-width=".2"/>
<circle cx="167.8" cy="67.6" r=".76" fill="#008000" stroke="#008000" stroke-width=".2"/>
<circle cx="167.8" cy="67.6" r=".51" fill="#fff" stroke="#000" stroke-width=".2"/>
<circle cx="167.8" cy="65.1" r=".76" fill="#008000" stroke="#008000" stroke-width=".2"/>
<circle cx="167.8" cy="65.1" r=".51" fill="#fff" stroke="#000" stroke-width=".2"/>
<circle cx="170.3" cy="67.6" r=".76" fill="#008000" stroke="#008000" stroke-width=".2"/>
<circle cx="170.3" cy="67.6" r=".51" fill="#fff" stroke="#000" stroke-width=".2"/>
<circle cx="170.3" cy="65.1" r=".76" fill="#008000" stroke="#008000" stroke-width=".2"/>
<circle cx="170.3" cy="65.1" r=".51" fill="#fff" stroke="#000" stroke-width=".2"/>
<circle cx="172.8" cy="67.6" r=".76" fill="#008000" stroke="#008000" stroke-width=".2"/>
<circle cx="172.8" cy="67.6" r=".51" fill="#fff" stroke="#000" stroke-width=".2"/>
<circle cx="172.8" cy="65.1" r=".76" fill="#008000" stroke="#008000" stroke-width=".2"/>
<circle cx="172.8" cy="65.1" r=".51" fill="#fff" stroke="#000" stroke-width=".2"/>
<circle cx="175.4" cy="67.6" r=".76" fill="#008000" stroke="#008000" stroke-width=".2"/>
<circle cx="175.4" cy="67.6" r=".51" fill="#fff" stroke="#000" stroke-width=".2"/>
<circle cx="175.4" cy="65.1" r=".76" fill="#008000" stroke="#008000" stroke-width=".2"/>
<circle cx="175.4" cy="65.1" r=".51" fill="#fff" stroke="#000" stroke-width=".2"/>
<circle cx="177.9" cy="67.6" r=".76" fill="#008000" stroke="#008000" stroke-width=".2"/>
<circle cx="177.9" cy="67.6" r=".51" fill="#fff" stroke="#000" stroke-width=".2"/>
<circle cx="177.9" cy="65.1" r=".76" fill="#008000" stroke="#008000" stroke-width=".2"/>
<circle cx="177.9" cy="65.1" r=".51" fill="#fff" stroke="#000" stroke-width=".2"/>
<circle cx="180.5" cy="67.6" r=".76" fill="#008000" stroke="#008000" stroke-width=".2"/>
<circle cx="180.5" cy="67.6" r=".51" fill="#fff" stroke="#000" stroke-width=".2"/>
<circle cx="180.5" cy="65.1" r=".76" fill="#008000" stroke="#008000" stroke-width=".2"/>
<circle cx="180.5" cy="65.1" r=".51" fill="#fff" stroke="#000" stroke-width=".2"/>
<circle cx="186.8" cy="103.7" r=".51" fill="#008000" stroke="#008000" stroke-width=".2"/>
<circle cx="186.8" cy="103.7" r=".3" fill="#fff" stroke="#000" stroke-width=".2"/>
<circle cx="183.3" cy="103.7" r=".51" fill="#008000" stroke="#008000" stroke-width=".2"/>
<circle cx="183.3" cy="103.7" r=".3" fill="#fff" stroke="#000" stroke-width=".2"/>
<circle cx="185.1" cy="128.8" r=".51" fill="#008000" stroke="#008000" stroke-width=".2"/>
<circle cx="185.1" cy="128.8" r=".3" fill="#fff" stroke="#000" stroke-width=".2"/>
<circle cx="187.7" cy="126.2" r=".51" fill="#008000" stroke="#008000" stroke-width=".2"/>
<circle cx="187.7" cy="126.2" r=".3" fill="#fff" stroke="#000" stroke-width=".2"/>
<circle cx="186.9" cy="134.9" r=".51" fill="#008000" stroke="#008000" stroke-width=".2"/>
<circle cx="186.9" cy="134.9" r=".3" fill="#fff" stroke="#000" stroke-width=".2"/>
<circle cx="183.1" cy="134.9" r=".51" fill="#008000" stroke="#008000" stroke-width=".2"/>
<circle cx="183.1" cy="134.9" r=".3" fill="#fff" stroke="#000" stroke-width=".2"/>
<circle cx="177.4" cy="130.7" r=".51" fill="#008000" stroke="#008000" stroke-width=".2"/>
<circle cx="177.4" cy="130.7" r=".3" fill="#fff" stroke="#000" stroke-width=".2"/>
<circle cx="182.3" cy="130.7" r=".51" fill="#008000" stroke="#008000" stroke-width=".2"/>
<circle cx="182.3" cy="130.7" r=".3" fill="#fff" stroke="#000" stroke-width=".2"/>
<circle cx="156.5" cy="73.2" r=".51" fill="#008000" stroke="#008000" stroke-width=".2"/>
<circle cx="156.5" cy="73.2" r=".3" fill="#fff" stroke="#000" stroke-width=".2"/>
<circle cx="159.1" cy="134.9" r=".51" fill="#008000" stroke="#008000" stroke-width=".2"/>
<circle cx="159.1" cy="134.9" r=".3" fill="#fff" stroke="#000" stroke-width=".2"/>
<circle cx="145.4" cy="69.7" r=".51" fill="#008000" stroke="#008000" stroke-width=".2"/>
<circle cx="145.4" cy="69.7" r=".3" fill="#fff" stroke="#000" stroke-width=".2"/>
<circle cx="133.7" cy="93.8" r=".51" fill="#008000" stroke="#008000" stroke-width=".2"/>
<circle cx="133.7" cy="93.8" r=".3" fill="#fff" stroke="#000" stroke-width=".2"/>
<circle cx="125.8" cy="139" r=".51" fill="#008000" stroke="#008000" stroke-width=".2"/>
<circle cx="125.8" cy="139" r=".3" fill="#fff" stroke="#000" stroke-width=".2"/>
<circle cx="141.7" cy="135" r=".51" fill="#008000" stroke="#008000" stroke-width=".2"/>
<circle cx="141.7" cy="135" r=".3" fill="#fff" stroke="#000" stroke-width=".2"/>
<circle cx="143" cy="130.3" r=".51" fill="#008000" stroke="#008000" stroke-width=".2"/>
<circle cx="143" cy="130.3" r=".3" fill="#fff" stroke="#000" stroke-width=".2"/>
<circle cx="147.8" cy="136.2" r=".51" fill="#008000" stroke="#008000" stroke-width=".2"/>
<circle cx="147.8" cy="136.2" r=".3" fill="#fff" stroke="#000" stroke-width=".2"/>
<circle cx="147.8" cy="132.4" r=".51" fill="#008000" stroke="#008000" stroke-width=".2"/>
<circle cx="147.8" cy="132.4" r=".3" fill="#fff" stroke="#000" stroke-width=".2"/>
<circle cx="180.4" cy="96" r=".51" fill="#008000" stroke="#008000" stroke-width=".2"/>
<circle cx="180.4" cy="96" r=".3" fill="#fff" stroke="#000" stroke-width=".2"/>
<circle cx="175.3" cy="102.6" r=".51" fill="#008000" stroke="#008000" stroke-width=".2"/>
<circle cx="175.3" cy="102.6" r=".3" fill="#fff" stroke="#000" stroke-width=".2"/>
<circle cx="191.1" cy="91.4" r=".51" fill="#008000" stroke="#008000" stroke-width=".2"/>
<circle cx="191.1" cy="91.4" r=".3" fill="#fff" stroke="#000" stroke-width=".2"/>
<circle cx="151.9" cy="83.2" r=".51" fill="#008000" stroke="#008000" stroke-width=".2"/>
<circle cx="151.9" cy="83.2" r=".3" fill="#fff" stroke="#000" stroke-width=".2"/>
<circle cx="132.8" cy="137.5" r=".51" fill="#008000" stroke="#008000" stroke-width=".2"/>
<circle cx="132.8" cy="137.5" r=".3" fill="#fff" stroke="#000" stroke-width=".2"/>
<circle cx="130.8" cy="130.5" r=".51" fill="#008000" stroke="#008000" stroke-width=".2"/>
<circle cx="130.8" cy="130.5" r=".3" fill="#fff" stroke="#000" stroke-width=".2"/>
<circle cx="149.5" cy="137.7" r=".51" fill="#008000" stroke="#008000" stroke-width=".2"/>
<circle cx="149.5" cy="137.7" r=".3" fill="#fff" stroke="#000" stroke-width=".2"/>
<circle cx="148.4" cy="128.6" r=".51" fill="#008000" stroke="#008000" stroke-width=".2"/>
<circle cx="148.4" cy="128.6" r=".3" fill="#fff" stroke="#000" stroke-width=".2"/>
<circle cx="127.2" cy="70.6" r=".51" fill="#008000" stroke="#008000" stroke-width=".2"/>
<circle cx="127.2" cy="70.6" r=".3" fill="#fff" stroke="#000" stroke-width=".2"/>
<circle cx="127.2" cy="75.1" r=".51" fill="#008000" stroke="#008000" stroke-width=".2"/>
<circle cx="127.2" cy="75.1" r=".3" fill="#fff" stroke="#000" stroke-width=".2"/>
<circle cx="180.1" cy="127" r=".51" fill="#008000" stroke="#008000" stroke-width=".2"/>
<circle cx="180.1" cy="127" r=".3" fill="#fff" stroke="#000" stroke-width=".2"/>
<circle cx="191.1" cy="122.6" r=".51" fill="#008000" stroke="#008000" stroke-width=".2"/>
<circle cx="191.1" cy="122.6" r=".3" fill="#fff" stroke="#000" stroke-width=".2"/>
<circle cx="175.3" cy="134.6" r=".51" fill="#008000" stroke="#008000" stroke-width=".2"/>
<circle cx="175.3" cy="134.6" r=".3" fill="#fff" stroke="#000" stroke-width=".2"/>
<circle cx="133.9" cy="128.5" r=".51" fill="#008000" stroke="#008000" stroke-width=".2"/>
<circle cx="133.9" cy="128.5" r=".3" fill="#fff" stroke="#000" stroke-width=".2"/>
<circle cx="149.3" cy="90.6" r=".51" fill="#008000" stroke="#008000" stroke-width=".2"/>
<circle cx="149.3" cy="90.6" r=".3" fill="#fff" stroke="#000" stroke-width=".2"/>
<circle cx="127.2" cy="79" r=".51" fill="#008000" stroke="#008000" stroke-width=".2"/>
<circle cx="127.2" cy="79" r=".3" fill="#fff" stroke="#000" stroke-width=".2"/>
<circle cx="142.1" cy="78.7" r=".51" fill="#008000" stroke="#008000" stroke-width=".2"/>
<circle cx="142.1" cy="78.7" r=".3" fill="#fff" stroke="#000" stroke-width=".2"/>
<circle cx="146.2" cy="78.4" r=".51" fill="#008000" stroke="#008000" stroke-width=".2"/>
<circle cx="146.2" cy="78.4" r=".3" fill="#fff" stroke="#000" stroke-width=".2"/>
<circle cx="146" cy="74.2" r=".51" fill="#008000" stroke="#008000" stroke-width=".2"/>
<circle cx="146" cy="74.2" r=".3" fill="#fff" stroke="#000" stroke-width=".2"/>
<circle cx="146.3" cy="124.5" r=".51" fill="#008000" stroke="#008000" stroke-width=".2"/>
<circle cx="146.3" cy="124.5" r=".3" fill="#fff" stroke="#000" stroke-width=".2"/>
<circle cx="136.8" cy="111.2" r=".51" fill="#008000" stroke="#008000" stroke-width=".2"/>
<circle cx="136.8" cy="111.2" r=".3" fill="#fff" stroke="#000" stroke-width=".2"/>
<circle cx="138.4" cy="117.2" r=".51" fill="#008000" stroke="#008000" stroke-width=".2"/>
<circle cx="138.4" cy="117.2" r=".3" fill="#fff" stroke="#000" stroke-width=".2"/>
<circle cx="113.7" cy="87.7" r=".51" fill="#008000" stroke="#008000" stroke-width=".2"/>
<circle cx="113.7" cy="87.7" r=".3" fill="#fff" stroke="#000" stroke-width=".2"/>
<circle cx="121.2" cy="87.9" r=".51" fill="#008000" stroke="#008000" stroke-width=".2"/>
<circle cx="121.2" cy="87.9" r=".3" fill="#fff" stroke="#000" stroke-width=".2"/>
<circle cx="177.8" cy="73.2" r=".51" fill="#008000" stroke="#008000" stroke-width=".2"/>
<circle cx="177.8" cy="73.2" r=".3" fill="#fff" stroke="#000" stroke-width=".2"/>
<circle cx="125.8" cy="129.3" r=".51" fill="#008000" stroke="#008000" stroke-width=".2"/>
<circle cx="125.8" cy="129.3" r=".3" fill="#fff" stroke="#000" stroke-width=".2"/>
<circle cx="125.8" cy="134.8" r=".51" fill="#008000" stroke="#008000" stroke-width=".2"/>
<circle cx="125.8" cy="134.8" r=".3" fill="#fff" stroke="#000" stroke-width=".2"/>
<circle cx="131.4" cy="136" r=".51" fill="#008000" stroke="#008000" stroke-width=".2"/>
<circle cx="131.4" cy="136" r=".3" fill="#fff" stroke="#000" stroke-width=".2"/>
<circle cx="131.4" cy="132.7" r=".51" fill="#008000" stroke="#008000" stroke-width=".2"/>
<circle cx="131.4" cy="132.7" r=".3" fill="#fff" stroke="#000" stroke-width=".2"/>
<circle cx="153.7" cy="73.1" r=".51" fill="#008000" stroke="#008000" stroke-width=".2"/>
<circle cx="153.7" cy="73.1" r=".3" fill="#fff" stroke="#000" stroke-width=".2"/>
<circle cx="158.1" cy="90.7" r=".51" fill="#008000" stroke="#008000" stroke-width=".2"/>
<circle cx="158.1" cy="90.7" r=".3" fill="#fff" stroke="#000" stroke-width=".2"/>
<circle cx="142.4" cy="69.7" r=".51" fill="#008000" stroke="#008000" stroke-width=".2"/>
<circle cx="142.4" cy="69.7" r=".3" fill="#fff" stroke="#000" stroke-width=".2"/>
<circle cx="129.8" cy="75.1" r=".51" fill="#008000" stroke="#008000" stroke-width=".2"/>
<circle cx="129.8" cy="75.1" r=".3" fill="#fff" stroke="#000" stroke-width=".2"/>
<circle cx="129.8" cy="79" r=".51" fill="#008000" stroke="#008000" stroke-width=".2"/>
<circle cx="129.8" cy="79" r=".3" fill="#fff" stroke="#000" stroke-width=".2"/>
<circle cx="177.3" cy="121.1" r=".51" fill="#008000" stroke="#008000" stroke-width=".2"/>
<circle cx="177.3" cy="121.1" r=".3" fill="#fff" stroke="#000" stroke-width=".2"/>
<circle cx="177.3" cy="124.5" r=".51" fill="#008000" stroke="#008000" stroke-width=".2"/>
<circle cx="177.3" cy="124.5" r=".3" fill="#fff" stroke="#000" stroke-width=".2"/>
<circle cx="156.5" cy="116.9" r=".51" fill="#008000" stroke="#008000" stroke-width=".2"/>
<circle cx="156.5" cy="116.9" r=".3" fill="#fff" stroke="#000" stroke-width=".2"/>
<circle cx="164" cy="117.9" r=".51" fill="#008000" stroke="#008000" stroke-width=".2"/>
<circle cx="164" cy="117.9" r=".3" fill="#fff" stroke="#000" stroke-width=".2"/>
<circle cx="130.8" cy="70.8" r=".51" fill="#008000" stroke="#008000" stroke-width=".2"/>
<circle cx="130.8" cy="70.8" r=".3" fill="#fff" stroke="#000" stroke-width=".2"/>
<circle cx="157.5" cy="75.4" r=".51" fill="#008000" stroke="#008000" stroke-width=".2"/>
<circle cx="157.5" cy="75.4" r=".3" fill="#fff" stroke="#000" stroke-width=".2"/>
<circle cx="136.3" cy="116.3" r=".51" fill="#008000" stroke="#008000" stroke-width=".2"/>
<circle cx="136.3" cy="116.3" r=".3" fill="#fff" stroke="#000" stroke-width=".2"/>
<circle cx="150.5" cy="115.8" r=".51" fill="#008000" stroke="#008000" stroke-width=".2"/>
<circle cx="150.5" cy="115.8" r=".3" fill="#fff" stroke="#000" stroke-width=".2"/>
<circle cx="145.1" cy="75.4" r=".51" fill="#008000" stroke="#008000" stroke-width=".2"/>
<circle cx="145.1" cy="75.4" r=".3" fill="#fff" stroke="#000" stroke-width=".2"/>
<circle cx="145.6" cy="114.6" r=".51" fill="#008000" stroke="#008000" stroke-width=".2"/>
<circle cx="145.6" cy="114.6" r=".3" fill="#fff" stroke="#000" stroke-width=".2"/>
<circle cx="140.7" cy="115.6" r=".51" fill="#008000" stroke="#008000" stroke-width=".2"/>
<circle cx="140.7" cy="115.6" r=".3" fill="#fff" stroke="#000" stroke-width=".2"/>
<circle cx="131.5" cy="115.3" r=".51" fill="#008000" stroke="#008000" stroke-width=".2"/>
<circle cx="131.5" cy="115.3" r=".3" fill="#fff" stroke="#000" stroke-width=".2"/>
<circle cx="127.5" cy="116" r=".51" fill="#008000" stroke="#008000" stroke-width=".2"/>
<circle cx="127.5" cy="116" r=".3" fill="#fff" stroke="#000" stroke-width=".2"/>
<circle cx="129.7" cy="82" r=".51" fill="#008000" stroke="#008000" stroke-width=".2"/>
<circle cx="129.7" cy="82" r=".3" fill="#fff" stroke="#000" stroke-width=".2"/>
<circle cx="164.8" cy="76.6" r=".51" fill="#008000" stroke="#008000" stroke-width=".2"/>
<circle cx="164.8" cy="76.6" r=".3" fill="#fff" stroke="#000" stroke-width=".2"/>
<circle cx="135.1" cy="69.9" r=".51" fill="#008000" stroke="#008000" stroke-width=".2"/>
<circle cx="135.1" cy="69.9" r=".3" fill="#fff" stroke="#000" stroke-width=".2"/>
<circle cx="140" cy="82.3" r=".51" fill="#008000" stroke="#008000" stroke-width=".2"/>
<circle cx="140" cy="82.3" r=".3" fill="#fff" stroke="#000" stroke-width=".2"/>
<circle cx="144.7" cy="95.7" r=".51" fill="#008000" stroke="#008000" stroke-width=".2"/>
<circle cx="144.7" cy="95.7" r=".3" fill="#fff" stroke="#000" stroke-width=".2"/>
<circle cx="138.3" cy="83.6" r=".51" fill="#008000" stroke="#008000" stroke-width=".2"/>
<circle cx="138.3" cy="83.6" r=".3" fill="#fff" stroke="#000" stroke-width=".2"/>
<circle cx="143.4" cy="96.3" r=".51" fill="#008000" stroke="#008000" stroke-width=".2"/>
<circle cx="143.4" cy="96.3" r=".3" fill="#fff" stroke="#000" stroke-width=".2"/>
<circle cx="125.9" cy="75.1" r=".51" fill="#008000" stroke="#008000" stroke-width=".2"/>
<circle cx="125.9" cy="75.1" r=".3" fill="#fff" stroke="#000" stroke-width=".2"/>
<circle cx="125.9" cy="79" r=".51" fill="#008000" stroke="#008000" stroke-width=".2"/>
<circle cx="125.9" cy="79" r=".3" fill="#fff" stroke="#000" stroke-width=".2"/>
<circle cx="140.4" cy="91.8" r=".51" fill="#008000" stroke="#008000" stroke-width=".2"/>
<circle cx="140.4" cy="91.8" r=".3" fill="#fff" stroke="#000" stroke-width=".2"/>
<circle cx="125.9" cy="95.4" r=".51" fill="#008000" stroke="#008000" stroke-width=".2"/>
<circle cx="125.9" cy="95.4" r=".3" fill="#fff" stroke="#000" stroke-width=".2"/>
<circle cx="133.2" cy="110.3" r=".51" fill="#008000" stroke="#008000" stroke-width=".2"/>
<circle cx="133.2" cy="110.3" r=".3" fill="#fff" stroke="#000" stroke-width=".2"/>
<circle cx="122.9" cy="105.2" r=".51" fill="#008000" stroke="#008000" stroke-width=".2"/>
<circle cx="122.9" cy="105.2" r=".3" fill="#fff" stroke="#000" stroke-width=".2"/>
<circle cx="115.2" cy="74.7" r=".51" fill="#008000" stroke="#008000" stroke-width=".2"/>
<circle cx="115.2" cy="74.7" r=".3" fill="#fff" stroke="#000" stroke-width=".2"/>
<circle cx="110.6" cy="80.3" r=".51" fill="#008000" stroke="#008000" stroke-width=".2"/>
<circle cx="110.6" cy="80.3" r=".3" fill="#fff" stroke="#000" stroke-width=".2"/>
<circle cx="147.7" cy="109.1" r=".51" fill="#008000" stroke="#008000" stroke-width=".2"/>
<circle cx="147.7" cy="109.1" r=".3" fill="#fff" stroke="#000" stroke-width=".2"/>
<circle cx="124.4" cy="106.8" r=".51" fill="#008000" stroke="#008000" stroke-width=".2"/>
<circle cx="124.4" cy="106.8" r=".3" fill="#fff" stroke="#000" stroke-width=".2"/>
<circle cx="128.4" cy="75.1" r=".51" fill="#008000" stroke="#008000" stroke-width=".2"/>
<circle cx="128.4" cy="75.1" r=".3" fill="#fff" stroke="#000" stroke-width=".2"/>
<circle cx="128.4" cy="79" r=".51" fill="#008000" stroke="#008000" stroke-width=".2"/>
<circle cx="128.4" cy="79" r=".3" fill="#fff" stroke="#000" stroke-width=".2"/>
<circle cx="142" cy="93.2" r=".51" fill="#008000" stroke="#008000" stroke-width=".2"/>
<circle cx="142" cy="93.2" r=".3" fill="#fff" stroke="#000" stroke-width=".2"/>
<circle cx="128.4" cy="98.3" r=".51" fill="#008000" stroke="#008000" stroke-width=".2"/>
<circle cx="128.4" cy="98.3" r=".3" fill="#fff" stroke="#000" stroke-width=".2"/>
<circle cx="147.8" cy="92.9" r=".51" fill="#008000" stroke="#008000" stroke-width=".2"/>
<circle cx="147.8" cy="92.9" r=".3" fill="#fff" stroke="#000" stroke-width=".2"/>
<circle cx="150.5" cy="98.8" r=".51" fill="#008000" stroke="#008000" stroke-width=".2"/>
<circle cx="150.5" cy="98.8" r=".3" fill="#fff" stroke="#000" stroke-width=".2"/>
<circle cx="177.1" cy="83" r=".51" fill="#008000" stroke="#008000" stroke-width=".2"/>
<circle cx="177.1" cy="83" r=".3" fill="#fff" stroke="#000" stroke-width=".2"/>
<circle cx="176.2" cy="78.7" r=".51" fill="#008000" stroke="#008000" stroke-width=".2"/>
<circle cx="176.2" cy="78.7" r=".3" fill="#fff" stroke="#000" stroke-width=".2"/>
<circle cx="185.2" cy="97.5" r=".51" fill="#008000" stroke="#008000" stroke-width=".2"/>
<circle cx="185.2" cy="97.5" r=".3" fill="#fff" stroke="#000" stroke-width=".2"/>
<circle cx="187.8" cy="95.3" r=".51" fill="#008000" stroke="#008000" stroke-width=".2"/>
<circle cx="187.8" cy="95.3" r=".3" fill="#fff" stroke="#000" stroke-width=".2"/>
<circle cx="177.3" cy="99" r=".51" fill="#008000" stroke="#008000" stroke-width=".2"/>
<circle cx="177.3" cy="99" r=".3" fill="#fff" stroke="#000" stroke-width=".2"/>
<circle cx="182.5" cy="99" r=".51" fill="#008000" stroke="#008000" stroke-width=".2"/>
<circle cx="182.5" cy="99" r=".3" fill="#fff" stroke="#000" stroke-width=".2"/>
<circle cx="175.7" cy="84.7" r=".51" fill="#008000" stroke="#008000" stroke-width=".2"/>
<circle cx="175.7" cy="84.7" r=".3" fill="#fff" stroke="#000" stroke-width=".2"/>
<circle cx="178.8" cy="111.7" r=".51" fill="#008000" stroke="#008000" stroke-width=".2"/>
<circle cx="178.8" cy="111.7" r=".3" fill="#fff" stroke="#000" stroke-width=".2"/>
<circle cx="138.6" cy="69.8" r=".51" fill="#008000" stroke="#008000" stroke-width=".2"/>
<circle cx="138.6" cy="69.8" r=".3" fill="#fff" stroke="#000" stroke-width=".2"/>
<circle cx="145.2" cy="82.3" r=".51" fill="#008000" stroke="#008000" stroke-width=".2"/>
<circle cx="145.2" cy="82.3" r=".3" fill="#fff" stroke="#000" stroke-width=".2"/>
<circle cx="150.5" cy="94.1" r=".51" fill="#008000" stroke="#008000" stroke-width=".2"/>
<circle cx="150.5" cy="94.1" r=".3" fill="#fff" stroke="#000" stroke-width=".2"/>
<circle cx="186.7" cy="65.7" r=".51" fill="#008000" stroke="#008000" stroke-width=".2"/>
<circle cx="186.7" cy="65.7" r=".3" fill="#fff" stroke="#000" stroke-width=".2"/>
<circle cx="177.4" cy="89.1" r=".51" fill="#008000" stroke="#008000" stroke-width=".2"/>
<circle cx="177.4" cy="89.1" r=".3" fill="#fff" stroke="#000" stroke-width=".2"/>
<circle cx="177.4" cy="92.6" r=".51" fill="#008000" stroke="#008000" stroke-width=".2"/>
<circle cx="177.4" cy="92.6" r=".3" fill="#fff" stroke="#000" stroke-width=".2"/>
<circle cx="106.2" cy="74.2" r=".51" fill="#008000" stroke="#008000" stroke-width=".2"/>
<circle cx="106.2" cy="74.2" r=".3" fill="#fff" stroke="#000" stroke-width=".2"/>
<circle cx="113.1" cy="66.4" r=".51" fill="#008000" stroke="#008000" stroke-width=".2"/>
<circle cx="113.1" cy="66.4" r=".3" fill="#fff" stroke="#000" stroke-width=".2"/>
<circle cx="173.7" cy="79.2" r=".51" fill="#008000" stroke="#008000" stroke-width=".2"/>
<circle cx="173.7" cy="79.2" r=".3" fill="#fff" stroke="#000" stroke-width=".2"/>
<circle cx="186.7" cy="73.5" r=".51" fill="#008000" stroke="#008000" stroke-width=".2"/>
<circle cx="186.7" cy="73.5" r=".3" fill="#fff" stroke="#000" stroke-width=".2"/>
<circle cx="185.3" cy="60.1" r="2.16" fill="#008000" stroke="#008000" stroke-width=".2"/>
<circle cx="185.3" cy="60.1" r="1.65" fill="#fff" stroke="#000" stroke-width=".2"/>
<circle cx="111.7" cy="60.1" r="2.16" fill="#008000" stroke="#008000" stroke-width=".2"/>
<circle cx="111.7" cy="60.1" r="1.65" fill="#fff" stroke="#000" stroke-width=".2"/>
<circle cx="107.9" cy="145.8" r="2.16" fill="#008000" stroke="#008000" stroke-width=".2"/>
<circle cx="107.9" cy="145.8" r="1.65" fill="#fff" stroke="#000" stroke-width=".2"/>
<circle cx="187.8" cy="145.8" r="2.16" fill="#008000" stroke="#008000" stroke-width=".2"/>
<circle cx="187.8" cy="145.8" r="1.65" fill="#fff" stroke="#000" stroke-width=".2"/>
<circle cx="113.6" cy="143.9" r=".51" fill="#008000" stroke="#008000" stroke-width=".2"/>
<circle cx="113.6" cy="143.9" r=".3" fill="#fff" stroke="#000" stroke-width=".2"/>
<circle cx="120.6" cy="145.9" r=".51" fill="#008000" stroke="#008000" stroke-width=".2"/>
<circle cx="120.6" cy="145.9" r=".3" fill="#fff" stroke="#000" stroke-width=".2"/>
<circle cx="127.6" cy="143.9" r=".51" fill="#008000" stroke="#008000" stroke-width=".2"/>
<circle cx="127.6" cy="143.9" r=".3" fill="#fff" stroke="#000" stroke-width=".2"/>
<circle cx="134.6" cy="145.9" r=".51" fill="#008000" stroke="#008000" stroke-width=".2"/>
<circle cx="134.6" cy="145.9" r=".3" fill="#fff" stroke="#000" stroke-width=".2"/>
<circle cx="141.6" cy="143.9" r=".51" fill="#008000" stroke="#008000" stroke-width=".2"/>
<circle cx="141.6" cy="143.9" r=".3" fill="#fff" stroke="#000" stroke-width=".2"/>
<circle cx="148.6" cy="145.9" r=".51" fill="#008000" stroke="#008000" stroke-width=".2"/>
<circle cx="148.6" cy="145.9" r=".3" fill="#fff" stroke="#000" stroke-width=".2"/>
<circle cx="155.6" cy="143.9" r=".51" fill="#008000" stroke="#008000" stroke-width=".2"/>
<circle cx="155.6" cy="143.9" r=".3" fill="#fff" stroke="#000" stroke-width=".2"/>
<circle cx="162.6" cy="145.9" r=".51" fill="#008000" stroke="#008000" stroke-width=".2"/>
<circle cx="162.6" cy="145.9" r=".3" fill="#fff" stroke="#000" stroke-width=".2"/>
<circle cx="169.6" cy="143.9" r=".51" fill="#008000" stroke="#008000" stroke-width=".2"/>
<circle cx="169.6" cy="143.9" r=".3" fill="#fff" stroke="#000" stroke-width=".2"/>
<circle cx="128.6" cy="135.9" r=".51" fill="#008000" stroke="#008000" stroke-width=".2"/>
<circle cx="128.6" cy="135.9" r=".3" fill="#fff" stroke="#000" stroke-width=".2"/>
<circle cx="128" cy="134.7" r=".51" fill="#008000" stroke="#008000" stroke-width=".2"/>
<circle cx="128" cy="134.7" r=".3" fill="#fff" stroke="#000" stroke-width=".2"/>
<circle cx="144.5" cy="134.9" r=".51" fill="#008000" stroke="#008000" stroke-width=".2"/>
<circle cx="144.5" cy="134.9" r=".3" fill="#fff" stroke="#000" stroke-width=".2"/>
<circle cx="145.1" cy="136.2" r=".51" fill="#008000" stroke="#008000" stroke-width=".2"/>
<circle cx="145.1" cy="136.2" r=".3" fill="#fff" stroke="#000" stroke-width=".2"/>
<g fill="#800000" stroke="#800000" stroke-width=".2">
<path d="M110.2 67.8h3.2v1.6h-3.2z"/>
<path d="M109.5 73.9h3.5v.4h-3.5z"/>
<path d="M112.1 84.5h3.1v1.7h-3.1z"/>
<path d="M119 84.6h3.2v1.6h-3.2z"/>
<path d="M155.7 128.7h1.6v3.2h-1.6z"/>
<path d="M163 114.5h3.2v1.7h-3.2z"/>
<path d="M163 108.8h4.4v1.4h-4.4z"/>
<path d="M182.3 95h3.1v1.7h-3.1z"/>
<path d="M182.3 89.3h4.4v1.4h-4.4z"/>
<path d="M181.9 126.3h3.2v1.7h-3.2z"/>
<path d="M181.9 120.6h4.5v1.4h-4.5z"/>
<path d="M112.1 78.8h4.4v1.5h-4.4z"/>
<path d="M185.1 107.4h2v1.6h-2z"/>
<path d="M185.1 104.6h2v1.6h-2z"/>
<path d="M180.4 105.7h2v1.6h-2z"/>
<path d="M180.4 102.9h2v1.6h-2z"/>
<path d="M185 139.8h2v1.6h-2z"/>
<path d="M185 137h2v1.6h-2z"/>
<path d="M179.8 137.9h2v1.6h-2z"/>
<path d="M179.8 135.1h2v1.6h-2z"/>
<path d="M180.5 131.8h1.6v2h-1.6z"/>
<path d="M177.7 131.8h1.6v2h-1.6z"/>
<path d="M180.6 100.1h1.6v1.9h-1.6z"/>
<path d="M177.8 100.1h1.6v1.9h-1.6z"/>
<path d="M143.3 135.4h.4v.3h-.4z"/>
<path d="M143.3 134.9h.4v.2h-.4z"/>
<path d="M143.3 135.9h.4v.2h-.4z"/>
<path d="M143.3 134.4h.4v.2h-.4z"/>
<path d="M143.3 136.4h.4v.3h-.4z"/>
<path d="M145.9 136.4h.4v.3h-.4z"/>
<path d="M145.9 135.9h.4v.2h-.4z"/>
<path d="M145.9 135.4h.4v.3h-.4z"/>
<path d="M145.9 134.9h.4v.2h-.4z"/>
<path d="M145.9 134.4h.4v.2h-.4z"/>
<path d="M149.4 129.8h2v1.6h-2z"/>
<path d="M149.4 132.6h2v1.6h-2z"/>
<path d="M144.1 126.7h2v1.6h-2z"/>
<path d="M144.1 129.5h2v1.6h-2z"/>
<path d="M138.1 133.6h2v1.7h-2z"/>
<path d="M138.1 136.4h2v1.6h-2z"/>
<path d="M138.1 126.7h2v1.6h-2z"/>
<path d="M138.1 129.5h2v1.6h-2z"/>
<path d="M126.8 135.2h.4v.2h-.4z"/>
<path d="M126.8 134.7h.4v.2h-.4z"/>
<path d="M126.8 135.7h.4v.2h-.4z"/>
<path d="M126.8 134.2h.4v.2h-.4z"/>
<path d="M126.8 136.2h.4v.2h-.4z"/>
<path d="M129.4 136.2h.4v.2h-.4z"/>
<path d="M129.4 135.7h.4v.2h-.4z"/>
<path d="M129.4 135.2h.4v.2h-.4z"/>
<path d="M129.4 134.7h.4v.2h-.4z"/>
<path d="M129.4 134.2h.4v.2h-.4z"/>
<path d="M132.9 129.9h2v1.7h-2z"/>
<path d="M132.9 132.7h2v1.6h-2z"/>
<path d="M127.5 126.9h2v1.6h-2z"/>
<path d="M127.5 129.6h2v1.7h-2z"/>
<path d="M121.5 133.6h2v1.6h-2z"/>
<path d="M121.5 136.4h2v1.6h-2z"/>
<path d="M121.5 126.9h2v1.6h-2z"/>
<path d="M121.5 129.6h2v1.7h-2z"/>
<path d="M105.1 67.8h2v1.6h-2z"/>
<path d="M105.1 70.6h2v1.6h-2z"/>
<path d="M188.7 107.8h1.3v1.5h-1.3z"/>
<path d="M190.6 107.8h1.3v1.5h-1.3z"/>
<path d="M188.7 104.6h1.3v1.5h-1.3z"/>
<path d="M190.6 104.6h1.3v1.5h-1.3z"/>
<path d="M188.7 94.6h1.3v1.5h-1.3z"/>
<path d="M190.6 94.6h1.3v1.5h-1.3z"/>
<path d="M183.5 84.8h2.5v2.7h-2.5z"/>
<path d="M189.8 84.8h2.6v2.7h-2.6z"/>
<path d="M183.6 95h.5v1.7h-.5z"/>
<path d="M182.3 95h.6v1.7h-.6z"/>
<path d="M184.8 95h.6v1.7h-.6z"/>
<path d="M186.1 95h.6v1.7h-.6z"/>
<path d="M182.5 90.4h3.9v3.8h-3.9z"/>
<path d="M182.3 89.3h.6v1.4h-.6z"/>
<path d="M183.6 89.3h.5v1.4h-.5z"/>
<path d="M184.8 89.3h.6v1.4h-.6z"/>
<path d="M186.1 89.3h.6v1.4h-.6z"/>
<path d="M181.9 93.5h.7v.4h-.7z"/>
<path d="M186.4 93.5h.7v.4h-.7z"/>
<path d="M183.2 126.3h.6v1.7h-.6z"/>
<path d="M181.9 126.3h.6v1.7h-.6z"/>
<path d="M184.5 126.3h.6v1.7h-.6z"/>
<path d="M185.8 126.3h.6v1.7h-.6z"/>
<path d="M182.2 121.7h3.9v3.8h-3.9z"/>
<path d="M181.9 120.6h.6v1.4h-.6z"/>
<path d="M183.2 120.6h.6v1.4h-.6z"/>
<path d="M184.5 120.6h.6v1.4h-.6z"/>
<path d="M185.8 120.6h.6v1.4h-.6z"/>
<path d="M181.6 124.8h.7v.4h-.7z"/>
<path d="M186 124.8h.8v.4h-.8z"/>
<path d="M188.7 140.6h1.3v1.4h-1.3z"/>
<path d="M190.6 140.6h1.3v1.4h-1.3z"/>
<path d="M188.7 136.1h1.3v1.5h-1.3z"/>
<path d="M190.6 136.1h1.3v1.5h-1.3z"/>
<path d="M188.7 125.5h1.3v1.5h-1.3z"/>
<path d="M190.6 125.5h1.3v1.5h-1.3z"/>
<path d="M183.5 115.4h2.6v2.8h-2.6z"/>
<path d="M189.8 115.4h2.6v2.8h-2.6z"/>
<path d="M111.5 67.8h.6v1.6h-.6z"/>
<path d="M112.8 67.8h.6v1.6h-.6z"/>
<path d="M110.2 67.8h.6v1.6h-.6z"/>
<path d="M109 67.8h.6v1.6h-.6z"/>
<path d="M109.2 70.2h3.9v3.8h-3.9z"/>
<path d="M112.8 73.7h.6v1.4h-.6z"/>
<path d="M111.5 73.7h.6v1.4h-.6z"/>
<path d="M110.2 73.7h.6v1.4h-.6z"/>
<path d="M109 73.7h.6v1.4h-.6z"/>
<path d="M113.1 70.5h.7v.4h-.7z"/>
<path d="M108.6 70.5h.7v.4h-.7z"/>
<path d="M155.6 130h1.7v.6h-1.7z"/>
<path d="M155.6 128.8h1.7v.5h-1.7z"/>
<path d="M155.6 131.3h1.7v.6h-1.7z"/>
<path d="M155.6 132.6h1.7v.6h-1.7z"/>
<path d="M158.1 129h3.8v3.9h-3.8z"/>
<path d="M161.6 128.8h1.4v.5h-1.4z"/>
<path d="M161.6 130h1.4v.6h-1.4z"/>
<path d="M161.6 131.3h1.4v.6h-1.4z"/>
<path d="M161.6 132.6h1.4v.6h-1.4z"/>
<path d="M158.4 128.4h.4v.7h-.4z"/>
<path d="M158.4 132.8h.4v.7h-.4z"/>
<path d="M156.3 134.1h2v1.6h-2z"/>
<path d="M156.3 136.9h2v1.6h-2z"/>
<path d="M188.7 130.7h1.3v1.5h-1.3z"/>
<path d="M190.6 130.7h1.3v1.5h-1.3z"/>
<path d="M188.7 99.3h1.3v1.4h-1.3z"/>
<path d="M190.6 99.3h1.3v1.4h-1.3z"/>
<path d="M167.4 97.4h5.5v3.8h-5.5z"/>
<path d="M167.4 89.1h5.5v3.8h-5.5z"/>
<path d="M167.4 128.8h5.6v3.8h-5.6z"/>
<path d="M167.4 120.5h5.6v3.8h-5.6z"/>
<path d="M168.9 105.2h2.5v2.7h-2.5z"/>
<path d="M175.3 105.2h2.5v2.7h-2.5z"/>
<path d="M168.9 137.1h2.6v2.7h-2.6z"/>
<path d="M175.3 137.1h2.5v2.7h-2.5z"/>
<path d="M166 137.4h1.4v2.1h-1.4z"/>
<path d="M161.6 137.4h1.4v2.1h-1.4z"/>
<path d="M176.6 116.8h1.4v2.2h-1.4z"/>
<path d="M181 116.8h1.4v2.2h-1.4z"/>
<path d="M166.4 105.5h1.4v2.1h-1.4z"/>
<path d="M162 105.5h1.4v2.1h-1.4z"/>
<path d="M176.7 85.8h1.4v2.1h-1.4z"/>
<path d="M181.1 85.8h1.4v2.1h-1.4z"/>
<path d="M185.7 98.2h.4v1.3h-.4z"/>
<path d="M186.4 98.2h.3v1.3h-.3z"/>
<path d="M185 98.2h.4v1.3h-.4z"/>
<path d="M184.4 98.2h.4v1.3h-.4z"/>
<path d="M184.4 100.8h.4v1.3h-.4z"/>
<path d="M185 100.8h.4v1.3h-.4z"/>
<path d="M185.7 100.8h.4v1.3h-.4z"/>
<path d="M186.4 100.8h.3v1.3h-.3z"/>
<path d="M185.6 129.6h.4v1.2h-.4z"/>
<path d="M186.3 129.6h.3v1.2h-.3z"/>
<path d="M185 129.6h.3v1.2h-.3z"/>
<path d="M184.3 129.6h.4v1.2h-.4z"/>
<path d="M184.3 132.2h.4v1.2h-.4z"/>
<path d="M185 132.2h.3v1.2h-.3z"/>
<path d="M185.6 132.2h.4v1.2h-.4z"/>
<path d="M186.3 132.2h.3v1.2h-.3z"/>
<path d="M141.1 79.5h2.1v.6h-2.1z"/>
<path d="M147.3 79.5h2v.6h-2z"/>
<path d="M141.1 80.7h2.1v.7h-2.1z"/>
<path d="M141.1 82h2.1v.7h-2.1z"/>
<path d="M147.3 80.7h2v.7h-2z"/>
<path d="M147.3 82h2v.7h-2z"/>
<path d="M141.1 83.3h2.1v.6h-2.1z"/>
<path d="M147.3 83.3h2v.6h-2z"/>
<path d="M159.2 79.9h2v1.6h-2z"/>
<path d="M159.2 82.7h2v1.6h-2z"/>
<path d="M154.2 83.9h1.6v2h-1.6z"/>
<path d="M157 83.9h1.6v2h-1.6z"/>
<path d="M154.2 78.1h1.6v2h-1.6z"/>
<path d="M157 78.1h1.6v2h-1.6z"/>
<path d="M151.5 80.3h1.5v1.4h-1.5z"/>
<path d="M151.5 78.4h1.5v1.4h-1.5z"/>
<path d="M149.4 84.4h1.3v1.5h-1.3z"/>
<path d="M151.3 84.4h1.3v1.5h-1.3z"/>
<path d="M132.1 116.7h.6v1.2h-.6z"/>
<path d="M131.2 116.7h.5v1.2h-.5z"/>
<path d="M130.2 116.7h.6v1.2h-.6z"/>
<path d="M130.2 119.3h.6v1.2h-.6z"/>
<path d="M132.1 119.3h.6v1.2h-.6z"/>
<path d="M125.1 111.5h1.6v2h-1.6z"/>
<path d="M127.9 111.5h1.6v2h-1.6z"/>
<path d="M126.5 119.5h2v1.6h-2z"/>
<path d="M126.5 116.7h2v1.6h-2z"/>
<path d="M132.5 121.8h1.6v2h-1.6z"/>
<path d="M129.7 121.8h1.6v2h-1.6z"/>
<path d="M133.5 111.5h1.6v2h-1.6z"/>
<path d="M130.7 111.5h1.6v2h-1.6z"/>
<path d="M113.4 84.6h.6v1.6h-.6z"/>
<path d="M112.1 84.6h.6v1.6h-.6z"/>
<path d="M114.6 84.6h.6v1.6h-.6z"/>
<path d="M115.9 84.6h.6v1.6h-.6z"/>
<path d="M112.4 79.9h3.8v3.9h-3.8z"/>
<path d="M112.1 78.8h.6v1.5h-.6z"/>
<path d="M113.4 78.8h.6v1.5h-.6z"/>
<path d="M114.6 78.8h.6v1.5h-.6z"/>
<path d="M115.9 78.8h.6v1.5h-.6z"/>
<path d="M111.7 83.1h.7v.3h-.7z"/>
<path d="M116.2 83.1h.7v.3h-.7z"/>
<path d="M135.5 117.4h1.5v1.3h-1.5z"/>
<path d="M135.5 119.3h1.5v1.3h-1.5z"/>
<path d="M142 75.1h1.2v.5h-1.2z"/>
<path d="M142 74.1h1.2v.6h-1.2z"/>
<path d="M142 73.2h1.2v.5h-1.2z"/>
<path d="M139.4 73.2h1.2v.5h-1.2z"/>
<path d="M139.4 75.1h1.2v.5h-1.2z"/>
<path d="M146.3 116.7h.6v1.2h-.6z"/>
<path d="M145.4 116.7h.5v1.2h-.5z"/>
<path d="M144.4 116.7h.5v1.2h-.5z"/>
<path d="M144.4 119.3h.5v1.2h-.5z"/>
<path d="M146.3 119.3h.6v1.2h-.6z"/>
<path d="M140 111.4h1.6v1.9h-1.6z"/>
<path d="M142.8 111.4h1.6v1.9h-1.6z"/>
<path d="M139.7 119.3h1.9v1.6h-1.9z"/>
<path d="M139.7 116.5h1.9v1.6h-1.9z"/>
<path d="M146.7 121.5h1.6v2h-1.6z"/>
<path d="M143.9 121.5h1.6v2h-1.6z"/>
<path d="M148.1 111.4h1.6v1.9h-1.6z"/>
<path d="M145.3 111.4h1.6v1.9h-1.6z"/>
<path d="M120.3 84.6h.6v1.6h-.6z"/>
<path d="M119.1 84.6h.6v1.6h-.6z"/>
<path d="M121.6 84.6h.6v1.6h-.6z"/>
<path d="M122.9 84.6h.6v1.6h-.6z"/>
<path d="M119.3 79.9h3.9v3.9h-3.9z"/>
<path d="M119.1 78.8h.6v1.5h-.6z"/>
<path d="M120.3 78.8h.6v1.5h-.6z"/>
<path d="M121.6 78.8h.6v1.5h-.6z"/>
<path d="M122.9 78.8h.6v1.5h-.6z"/>
<path d="M118.7 83.1h.7v.3h-.7z"/>
<path d="M123.1 83.1h.7v.3h-.7z"/>
<path d="M149.7 117.3h1.5v1.3h-1.5z"/>
<path d="M149.7 119.2h1.5v1.3h-1.5z"/>
<path d="M151.4 96.9h1.1v.4h-1.1z"/>
<path d="M151.4 96.2h1.1v.5h-1.1z"/>
<path d="M151.4 95.6h1.1v.4h-1.1z"/>
<path d="M151.4 94.9h1.1v.5h-1.1z"/>
<path d="M151.4 94.3h1.1v.4h-1.1z"/>
<path d="M151.4 93.6h1.1v.5h-1.1z"/>
<path d="M151.4 93h1.1v.4h-1.1z"/>
<path d="M151.4 92.3h1.1v.5h-1.1z"/>
<path d="M151.4 91.7h1.1v.4h-1.1z"/>
<path d="M151.4 91h1.1v.5h-1.1z"/>
<path d="M145.9 91h1v.5h-1z"/>
<path d="M145.9 91.7h1v.4h-1z"/>
<path d="M145.9 92.3h1v.5h-1z"/>
<path d="M145.9 93h1v.4h-1z"/>
<path d="M145.9 93.6h1v.5h-1z"/>
<path d="M145.9 94.3h1v.4h-1z"/>
<path d="M145.9 94.9h1v.5h-1z"/>
<path d="M145.9 95.5h1v.5h-1z"/>
<path d="M145.9 96.2h1v.5h-1z"/>
<path d="M145.9 96.9h1v.4h-1z"/>
<path d="M155.4 93h1.5v1.3h-1.5z"/>
<path d="M155.4 91.1h1.5v1.3h-1.5z"/>
<path d="M153.1 93h1.5v1.3h-1.5z"/>
<path d="M153.1 91.1h1.5v1.3h-1.5z"/>
<path d="M140.6 97.3h2v1.6h-2z"/>
<path d="M140.6 94.5h2v1.6h-2z"/>
<path d="M172.6 81.2h1.3v.3h-1.3z"/>
<path d="M172.6 81.7h1.3v.3h-1.3z"/>
<path d="M172.6 82.2h1.3v.3h-1.3z"/>
<path d="M172.6 80.7h1.3v.3h-1.3z"/>
<path d="M172.6 80.2h1.3v.3h-1.3z"/>
<path d="M168.1 81.2h1.4v.3h-1.4z"/>
<path d="M168.1 81.7h1.4v.3h-1.4z"/>
<path d="M168.1 82.2h1.4v.3h-1.4z"/>
<path d="M168.1 80.7h1.4v.3h-1.4z"/>
<path d="M168.1 80.2h1.4v.3h-1.4z"/>
<path d="M179 78.3h2v1.6h-2z"/>
<path d="M179 81.1h2v1.6h-2z"/>
<path d="M183 78.3h2v1.6h-2z"/>
<path d="M183 81.1h2v1.6h-2z"/>
<path d="M183 73.4h2v1.6h-2z"/>
<path d="M183 76.2h2v1.6h-2z"/>
<path d="M179 73.4h2v1.6h-2z"/>
<path d="M179 76.2h2v1.6h-2z"/>
<path d="M147.8 99.6h1.7v2h-1.7z"/>
<path d="M145 99.6h1.6v2h-1.6z"/>
<path d="M154.3 99.6h1.6v2h-1.6z"/>
<path d="M151.5 99.6h1.6v2h-1.6z"/>
<path d="M136.5 90.2h2v1.6h-2z"/>
<path d="M136.5 93h2v1.6h-2z"/>
<path d="M133.2 91.3h2v1.6h-2z"/>
<path d="M133.2 88.5h2v1.6h-2z"/>
<path d="M175.9 73.7h.6v1.2h-.6z"/>
<path d="M175 73.7h.5v1.2h-.5z"/>
<path d="M174 73.7h.6v1.2h-.6z"/>
<path d="M174 76.3h.6v1.2h-.6z"/>
<path d="M175.9 76.3h.6v1.2h-.6z"/>
<path d="M164.6 84.8h1.6v2h-1.6z"/>
<path d="M167.4 84.8h1.6v2h-1.6z"/>
<path d="M185.7 70.8h2v1.7h-2z"/>
<path d="M185.7 68.1h2v1.6h-2z"/>
<path d="M164.3 114.5h.6v1.7h-.6z"/>
<path d="M163 114.5h.6v1.7h-.6z"/>
<path d="M165.5 114.5h.6v1.7h-.6z"/>
<path d="M166.8 114.5h.6v1.7h-.6z"/>
<path d="M163.3 109.9h3.9v3.8h-3.9z"/>
<path d="M163 108.8h.6v1.4h-.6z"/>
<path d="M164.3 108.8h.6v1.4h-.6z"/>
<path d="M165.5 108.8h.6v1.4h-.6z"/>
<path d="M166.8 108.8h.6v1.4h-.6z"/>
<path d="M162.6 113h.7v.4h-.7z"/>
<path d="M167.1 113h.7v.4h-.7z"/>
<path d="M170.7 112.3h2v1.6h-2z"/>
<path d="M170.7 115.1h2v1.6h-2z"/>
<path d="M112.6 142.9h60v4h-60z"/>
</g>
<g fill="#800000" stroke="#800000" stroke-width=".2">
<path d="M144 134.4h1.5v2.2h-1.5z" fill-rule="evenodd"/>
<path d="M127.5 134.2h1.5v2.2h-1.5z" fill-rule="evenodd"/>
</g>
<g fill="none" stroke="#800000" stroke-width=".42">
<path d="M106.1 71.4l.1 2.9M108.9 70.7h.9l1.4 1.4M109.3 74.4h3.8M110.5 68.6h2.6M111.2 72.1l.6 .6v1.7M111.8 67.7v.9M111.8 68.6h.1M113.1 66.4h.1M113.4 70.7h-.8l-1.4 1.4M115.7 63.8h2.6l1.2 1.3-1.2 1.3-2.2-.1M116.2 79.6h-3.8l1.9 1.9v.4M120.8 69.1v-2.8l1.3-1.2 1.2 1.3v1.9l-.8 .7h-1.7l-.5 .5"/>
<path d="M121.9 79.6v1.6l-2 2h-.9M124.6 65.1l1.3 1.3v8.7M125.9 79v33.5l2.2 2.2h.9l1.5 1.5v1.1M127.2 70.6v4.5M127.2 79l-.1 28.7 1.7 1.6h6.1l1.9 1.9M128.4 79v27.9l1.2 1.2h9.4l1.8 1.8v2.5l3.9 3.8v1.1M129.7 65.1l-1.3 1.2v8.8M134.8 65.1l1.3 1.3M135.1 69.9v3.7l4.9 4.9v3.8h2.1M138.6 69.8l2.7 2.7v3.7l3.9 3.9v2.2l1.3 1.3h1.8l1.6 1.6h.2M139.8 62.5l1.3 1.4h15.2l1.3-1.3M139.8 65.1l-1.3 1.3h-2.5v6.7l2.3 2.2h1.7"/>
<path d="M139.8 60l-1.2 1.3h-4.3l-.8 .8v11.3l4.8 4.8v5.4h3.8M142.1 78.7v2.4M142.6 75.4h4.9M142.6 75.3v.1M144.9 65.1h-1.2v3.3l-1.3 1.3-1.2-1.3v-2.1l1.2-1.2M145.4 69.7v2.1l-1.7 1.6h-1.1M146 74.2l-3.4 .2M146.2 78.4v2.6l1.2 1.3h3.6l1 1v1.9M147.4 65.1l-1.2 1.3v1.7l1.3 1.3 1.2-1.2v-3.1M152.2 79.1h.1M154.7 78.9h.2v.3M155 79.1h-6.7v.7"/>
<path d="M157.6 62.5v.1M157.8 79.1h2.4M160.1 65.1l-1.4 1.4v4.3l-2.2 2.4M160.1 69.9v.2M162.7 65.1h-1.3v-6.5h-47.1v4.7h-5.2l-3 3v2.3h3.2M177.8 73.2l1 1h1.2M186.7 65.7l.1 3.2M186.7 71.6v1.9M112.4 85.4h2.5M114.3 81.9l-1.4 1.3h-.8M114.3 81.9l1.4 1.3h.8M116.2 85.4v2.9l2.9 2.9h3l.8 .8v13.2"/>
<path d="M119.4 85.4h2.5M121.3 81.9l1.4 1.3h.8M123.2 85.4l1.2 1.2v20.2M129.7 82v23.7l1.3 1.3h8.9l3.7 3.7v1.7h2.5v.2l-.3-.2M134.2 92.1v1.2l-.5 .5M134.2 89.3h1.6l1.7 1.7 .6-.5h6.7l.7 .7h.9M137.5 93.8v.2l6.6 6.6h1.8M140.4 91.8h4.3l.7 .7h1M142 93.2h4.4M143.4 96.3v.4l.6 .6h.8l.8-.9 .8 .1M144.7 95.7l1.7 .1M146.4 95.1h-.7l-.5-.5h-2.9l-.7 .7"/>
<path d="M146.4 91.9h1l.4 .4v.6M146.4 94.5h2.9M146.4 93.8h2.9M148.3 81.1l3.9-.1 2.8 2.8v1.1M149.3 90.6v6.5M149.3 95.8h2.6M149.3 95.1h2.6M149.3 92.5h2.6M149.3 91.9h2.6M149.3 91.2h3.9l.5 .5M150.5 98.8v1.8M151.9 97.1h-6.1v3.5"/>
<path d="M151.9 93.2h-2.6M153.7 91.7h2.5M153.7 91.7v.1M153.8 93.6l-.2 .2h-1.7v.7h-1.1l-.3-.4M153.8 93.6v1.9l-.9 .9h-1M153.8 93.6h2.4M160.1 84.9v4.3M160.1 94.8l.2 .2M160.2 83.5v1.4h-2.4M165.4 83.1v2.7M167.6 85.2l.6 .6M177.3 99h-6.9l-.2 .3"/>
<path d="M177.4 86.9v2.2M177.4 89.1h.1M177.4 92.6v4.6l1.2 1.1v2.7M178.9 91v6.2l.5 .5h4.1l1.1 1.1M182.5 99l1 1h2.4M182.6 90h3.8M183.9 90v.7l-.4 .3v.3l2.4 2.4h.8M184.5 92.3l-1.4 1.4h-.8M184.7 86.1h.1M185.1 90h-1.2M185.1 95.8h-2.5l-.2 .2M185.2 97.5v1.3"/>
<path d="M185.9 98.9v1.1M186.4 95.8l.1 .2v2.8M187.8 95.3l1.5 .1M189.3 100h-3.4M191.1 91.4l.1 .2v9.8M191.1 86.1h.1M127.5 116v1.5M128.7 112.5h2.8v4.8M131.5 116.1h.1M132.4 117.3h.1M133.2 110.3l1.1 1.1v4l-1.9 1.9M136.2 119.9h.1"/>
<path d="M136.3 120l-2.9 2.8M138.4 117.2v2.1l-.6 .6h-5.4M140.7 117.3v-1.7h-3.8l-.6 .7v1.7M144.7 119.9v2.6M145.6 112.4v4.9M145.6 114.6h.1M146.6 119.9h3.9M147.7 109.1l1.2 1.2v4.6l-2.3 2.4M148.7 100.6h3.6M148.7 100.6h.1M150.4 119.9h.1M150.5 119.9l-2.7 2.6h-.3v.8l-1.2 1.2h-11.2l-1.7-1.7"/>
<path d="M150.5 115.8v2.2M158.1 100.4h-3v.2M160.2 113.3l.3 .3-.4 .4v8.2M163.3 109.5h3.8M163.3 115.3h2.5v1.4l.3 .2h4.6l1-1M164.6 109.5v1.7l2 2h.8M165.2 111.8l-1.4 1.4h-.8M167.1 106.6h.1M170.2 106.6h.1M171.7 113.1h-1l-2.2 2.2h-1.4M177.3 117.9v3.2M181.4 101v2.7h1.9"/>
<path d="M185.2 101.5v3.1l.9 .8 3.2-.1M185.9 101.5v1.3l.9 .9M186.1 108.2l3.3 .4M191.2 105.3v4.8h-6.3l-3.5-3.6M191.2 101.4v4.5M191.2 101.4l-4.7 .1M191.2 108.6h.1M122.5 127.7h.1M122.5 130.5v3.9M122.5 130.5h.1M122.5 130.5l.1 .4h2.8l1.6 1.6M122.6 127.7h6.7l2 1.9"/>
<path d="M125.8 129.3l1.2 1.2h1.5M127 134.8h.1M127 135.8h.1M127 136.3v.4l1.4 1.4M127 135.8h-3.1l-1.4 1.4M127 132.7h4.4M127 132.7v.1M127.5 120.3l.4-.4h2.6v2.8M128.4 138.1l-.1 .1M129.6 136.3v.6l-1.2 1.2M130.4 137.5h2.4M130.5 122.7v.1"/>
<path d="M130.7 135.3l.7 .7M131.3 129.6l1.1 1.1M131.3 129.6l-.5 .9M132.4 130.7v2.9l-.7 .7M132.4 130.7h1.5M133.3 122.8h.1M133.9 133.5v1.3M139.1 130.3h.1M139.1 127.5h6.6l3 3.1M139.1 130.3h2.3l2.1 2.2 4.3-.1M139.1 130.3v4.2M140.7 120.1h4"/>
<path d="M141.2 136h.1M143.5 137l1.3 1.3h.1M143.5 136h-3.2l-1.2 1.2M144.8 138.3v.2M145.1 130.3h-2.1M146.1 137.1l-1.2 1.1v.5M146.7 128.6h1.7M146.8 137.7h2.7M148.7 130.6v3.1l-.8 .8M148.7 130.6h1.7M150.4 133.4v1.6M156.5 132.9l.8 .8v1.2h1.8"/>
<path d="M156.5 130.3v1.3M157.3 137.7h-2.8v.1M158.6 128.7v.9l2.1 2h1.6M160 131l-1.4 1.4v.8M170.2 130.7h7.2M177.3 124.5v3.5l1.2 1.2v3.6M178.9 122.4v4.9l1.2 1.2h2.7l1.7 1.7M180.8 138.7l.4 .3M181.3 132.8v3.1h-.5l1-1h1.3M181.9 125h4.5M182.2 121.3h3.9M182.3 130.7l.7 .7h6.4"/>
<path d="M183.5 121.3l.7 .9-.1 2.8M184.5 132.8v2.9l-3.3 3.3M184.8 121.3v.5l-.6 .5M185.1 128.8v1.4M185.1 132.8v4.1l.9 .9 3.3-1M185.8 130.2v1.2M185.8 132.8v1l1.1 1.1M186.1 127.1l.4 .2v2.9M186.5 132.8h4.7M187.7 126.2l1.7 .1M191.1 122.6v3.5l.2 .2-.1 16.8h-6l-4-4.1M191.2 136.8h.1"/>
<path d="M191.3 131.4h.1M191.3 132.8h-.1M186 140.6l3.3 .7"/>
</g>
<g fill="none" stroke="#800000" stroke-width="1.3">
<path d="M120.8 69.1l-5.6 5.6M137.3 62.5h2.5M142.4 65.1h2.5M147.4 65.1h2.6M147.5 69.4v6h10M110.6 80.3l1.5 1.6h9.2M112.4 85.4v1l1.3 1.3M121.9 85.4v1.8l-.7 .7M164.8 85.1l.6 .7M170.2 91h13.3M170.2 99.3v7.3M181.8 86.9v2.4l.8 .7"/>
<path d="M184.7 86.1l-2.4-1.8h-3l-1.9 2.6M191.1 86.1v5.3M162.7 106.6v2.3l.6 .6M167.1 106.6h3.1M175.3 102.6v2.7l1.2 1.3M184.8 116.8l-2-1.9h-2.4l-3.1 3M191.1 116.8v5.8M162.3 129.1v9.3M170.2 122.4h14M170.2 130.7v7.7h-3.5M175.3 134.6v2.6l1.3 1.2"/>
</g>
<path d="M152.5 67.6l1.2 1.2v4.3M158.1 90.7v30.7l-5.7 5.6v10.5l-1.9 1.9h-4.9M128.3 138.2l-.7 .8h-1.8M156.5 125.9v4.4" fill="none" stroke="#800000" stroke-width="1"/>
<g fill="none" stroke="#800000" stroke-width=".32">
<path d="M173.7 79.2h-5.7l-.5 .5v1.3l.4 .4h.9M175.3 74.3v5.4l-.7 .6h-5.8M176.2 74.3v-.9l-.5-.5h-1l-.4 .4v1l-.4 .4h-9.6l-1.7 1.7v5.6l-1.5 1.5h-.9M176.2 76.9v1.8M180 77v2.1h-2.4l-1.8 1.8h-2.6M184 74.2h-4l-1.4 1.3h-2.6l-.7 .7M184 77v2.1h-1.2l-1.4 1.4h-3.6l-.9 .9h-3.7M168.8 81.9h-2.1l-1.3 1.2M168.8 82.4h-.5l-.7 .6v2.2M168.8 80.9h1.3l.4 .4v2.2l1.2 1.2h4M173.2 81.9h10.8M173.2 82.4h.7l1 .9h1.8l.4-.3"/>
<path d="M178.8 111.7h-5.7l-1.4 1.4M125.8 134.8h1.2M127 132.5v1.8M127 135.3v.5M129.6 134.3h2.1M129.6 135.8h.8v1.7M129.6 134.8h4.3M129.6 135.3h1.1M141.7 135h1.8M143.5 132.4v2.1M143.5 135.5v.5M143.5 136.5v.5"/>
<path d="M146.1 135h4.3M146.1 135.5h1l.7 .7M146.1 134.5h1.8M146.1 136h.7v1.7M146.1 136.5v.6M182.1 127l.1 .1h2.6"/>
</g>
<path d="M115.7 63.8l-2.6 2.6h3M129.8 79v.7l1.4 1.4v13.2l10.6 10.6h13.4l1.3 1.3v10.7M130.8 70.8l-1 1.1v3.2M164 117.9h13.3M177.3 117.9h.1M133.9 128.5v2.2M144.9 138.2v.5l.7 .7M156.5 129v.1" fill="none" stroke="#800000" stroke-width=".83"/>
<path d="M168.2 85.8l1.1 1.1h8.1M180.4 96h2M181.7 117.9v2.9l.5 .5M180.1 127h2" fill="none" stroke="#800000" stroke-width="1.4"/>
<path d="M106.2 74.2l2.8 2.8h24l2.5 2.5v6.4l2.8 2.8h21.8M113.1 66.4l-1.3 1.3M117 67.6v2.4l-2.1 2.1h-3.7M160.1 67.6l.1 13.1M164.8 76.6v8.5M180.5 60l2.9 2.9v5.1l-2 2.1h-21.3M160.1 94.9v27.3l-5.6 5.7v10.4l-2.8 2.8h-27.4l-1.8-1.8v-2.1M160.2 83.5l-.1 11.3M160.5 113.6l1.7 1.7h1.1M139.1 137.2l3.9 3.9" fill="none" stroke="#800000" stroke-width="1.7"/>
<circle cx="117" cy="62.5" r=".76" fill="#008000" stroke="#008000" stroke-width=".2"/>
<circle cx="117" cy="62.5" r=".51" fill="#fff" stroke="#000" stroke-width=".2"/>
<circle cx="117" cy="60" r=".76" fill="#008000" stroke="#008000" stroke-width=".2"/>
<circle cx="117" cy="60" r=".51" fill="#fff" stroke="#000" stroke-width=".2"/>
<circle cx="119.5" cy="62.5" r=".76" fill="#008000" stroke="#008000" stroke-width=".2"/>
<circle cx="119.5" cy="62.5" r=".51" fill="#fff" stroke="#000" stroke-width=".2"/>
<circle cx="119.5" cy="60" r=".76" fill="#008000" stroke="#008000" stroke-width=".2"/>
<circle cx="119.5" cy="60" r=".51" fill="#fff" stroke="#000" stroke-width=".2"/>
<circle cx="122.1" cy="62.5" r=".76" fill="#008000" stroke="#008000" stroke-width=".2"/>
<circle cx="122.1" cy="62.5" r=".51" fill="#fff" stroke="#000" stroke-width=".2"/>
<circle cx="122.1" cy="60" r=".76" fill="#008000" stroke="#008000" stroke-width=".2"/>
<circle cx="122.1" cy="60" r=".51" fill="#fff" stroke="#000" stroke-width=".2"/>
<circle cx="124.6" cy="62.5" r=".76" fill="#008000" stroke="#008000" stroke-width=".2"/>
<circle cx="124.6" cy="62.5" r=".51" fill="#fff" stroke="#000" stroke-width=".2"/>
<circle cx="124.6" cy="60" r=".76" fill="#008000" stroke="#008000" stroke-width=".2"/>
<circle cx="124.6" cy="60" r=".51" fill="#fff" stroke="#000" stroke-width=".2"/>
<circle cx="127.1" cy="62.5" r=".76" fill="#008000" stroke="#008000" stroke-width=".2"/>
<circle cx="127.1" cy="62.5" r=".51" fill="#fff" stroke="#000" stroke-width=".2"/>
<circle cx="127.1" cy="60" r=".76" fill="#008000" stroke="#008000" stroke-width=".2"/>
<circle cx="127.1" cy="60" r=".51" fill="#fff" stroke="#000" stroke-width=".2"/>
<circle cx="129.7" cy="62.5" r=".76" fill="#008000" stroke="#008000" stroke-width=".2"/>
<circle cx="129.7" cy="62.5" r=".51" fill="#fff" stroke="#000" stroke-width=".2"/>
<circle cx="129.7" cy="60" r=".76" fill="#008000" stroke="#008000" stroke-width=".2"/>
<circle cx="129.7" cy="60" r=".51" fill="#fff" stroke="#000" stroke-width=".2"/>
<circle cx="132.2" cy="62.5" r=".76" fill="#008000" stroke="#008000" stroke-width=".2"/>
<circle cx="132.2" cy="62.5" r=".51" fill="#fff" stroke="#000" stroke-width=".2"/>
<circle cx="132.2" cy="60" r=".76" fill="#008000" stroke="#008000" stroke-width=".2"/>
<circle cx="132.2" cy="60" r=".51" fill="#fff" stroke="#000" stroke-width=".2"/>
<circle cx="134.8" cy="62.5" r=".76" fill="#008000" stroke="#008000" stroke-width=".2"/>
<circle cx="134.8" cy="62.5" r=".51" fill="#fff" stroke="#000" stroke-width=".2"/>
<circle cx="134.8" cy="60" r=".76" fill="#008000" stroke="#008000" stroke-width=".2"/>
<circle cx="134.8" cy="60" r=".51" fill="#fff" stroke="#000" stroke-width=".2"/>
<circle cx="137.3" cy="62.5" r=".76" fill="#008000" stroke="#008000" stroke-width=".2"/>
<circle cx="137.3" cy="62.5" r=".51" fill="#fff" stroke="#000" stroke-width=".2"/>
<circle cx="137.3" cy="60" r=".76" fill="#008000" stroke="#008000" stroke-width=".2"/>
<circle cx="137.3" cy="60" r=".51" fill="#fff" stroke="#000" stroke-width=".2"/>
<circle cx="139.8" cy="62.5" r=".76" fill="#008000" stroke="#008000" stroke-width=".2"/>
<circle cx="139.8" cy="62.5" r=".51" fill="#fff" stroke="#000" stroke-width=".2"/>
<circle cx="139.8" cy="60" r=".76" fill="#008000" stroke="#008000" stroke-width=".2"/>
<circle cx="139.8" cy="60" r=".51" fill="#fff" stroke="#000" stroke-width=".2"/>
<circle cx="142.4" cy="62.5" r=".76" fill="#008000" stroke="#008000" stroke-width=".2"/>
<circle cx="142.4" cy="62.5" r=".51" fill="#fff" stroke="#000" stroke-width=".2"/>
<circle cx="142.4" cy="60" r=".76" fill="#008000" stroke="#008000" stroke-width=".2"/>
<circle cx="142.4" cy="60" r=".51" fill="#fff" stroke="#000" stroke-width=".2"/>
<circle cx="144.9" cy="62.5" r=".76" fill="#008000" stroke="#008000" stroke-width=".2"/>
<circle cx="144.9" cy="62.5" r=".51" fill="#fff" stroke="#000" stroke-width=".2"/>
<circle cx="144.9" cy="60" r=".76" fill="#008000" stroke="#008000" stroke-width=".2"/>
<circle cx="144.9" cy="60" r=".51" fill="#fff" stroke="#000" stroke-width=".2"/>
<circle cx="147.5" cy="62.5" r=".76" fill="#008000" stroke="#008000" stroke-width=".2"/>
<circle cx="147.5" cy="62.5" r=".51" fill="#fff" stroke="#000" stroke-width=".2"/>
<circle cx="147.5" cy="60" r=".76" fill="#008000" stroke="#008000" stroke-width=".2"/>
<circle cx="147.5" cy="60" r=".51" fill="#fff" stroke="#000" stroke-width=".2"/>
<circle cx="150" cy="62.5" r=".76" fill="#008000" stroke="#008000" stroke-width=".2"/>
<circle cx="150" cy="62.5" r=".51" fill="#fff" stroke="#000" stroke-width=".2"/>
<circle cx="150" cy="60" r=".76" fill="#008000" stroke="#008000" stroke-width=".2"/>
<circle cx="150" cy="60" r=".51" fill="#fff" stroke="#000" stroke-width=".2"/>
<circle cx="152.5" cy="62.5" r=".76" fill="#008000" stroke="#008000" stroke-width=".2"/>
<circle cx="152.5" cy="62.5" r=".51" fill="#fff" stroke="#000" stroke-width=".2"/>
<circle cx="152.5" cy="60" r=".76" fill="#008000" stroke="#008000" stroke-width=".2"/>
<circle cx="152.5" cy="60" r=".51" fill="#fff" stroke="#000" stroke-width=".2"/>
<circle cx="155.1" cy="62.5" r=".76" fill="#008000" stroke="#008000" stroke-width=".2"/>
<circle cx="155.1" cy="62.5" r=".51" fill="#fff" stroke="#000" stroke-width=".2"/>
<circle cx="155.1" cy="60" r=".76" fill="#008000" stroke="#008000" stroke-width=".2"/>
<circle cx="155.1" cy="60" r=".51" fill="#fff" stroke="#000" stroke-width=".2"/>
<circle cx="157.6" cy="62.5" r=".76" fill="#008000" stroke="#008000" stroke-width=".2"/>
<circle cx="157.6" cy="62.5" r=".51" fill="#fff" stroke="#000" stroke-width=".2"/>
<circle cx="157.6" cy="60" r=".76" fill="#008000" stroke="#008000" stroke-width=".2"/>
<circle cx="157.6" cy="60" r=".51" fill="#fff" stroke="#000" stroke-width=".2"/>
<circle cx="160.1" cy="62.5" r=".76" fill="#008000" stroke="#008000" stroke-width=".2"/>
<circle cx="160.1" cy="62.5" r=".51" fill="#fff" stroke="#000" stroke-width=".2"/>
<circle cx="160.1" cy="60" r=".76" fill="#008000" stroke="#008000" stroke-width=".2"/>
<circle cx="160.1" cy="60" r=".51" fill="#fff" stroke="#000" stroke-width=".2"/>
<circle cx="162.7" cy="62.5" r=".76" fill="#008000" stroke="#008000" stroke-width=".2"/>
<circle cx="162.7" cy="62.5" r=".51" fill="#fff" stroke="#000" stroke-width=".2"/>
<circle cx="162.7" cy="60" r=".76" fill="#008000" stroke="#008000" stroke-width=".2"/>
<circle cx="162.7" cy="60" r=".51" fill="#fff" stroke="#000" stroke-width=".2"/>
<circle cx="165.2" cy="62.5" r=".76" fill="#008000" stroke="#008000" stroke-width=".2"/>
<circle cx="165.2" cy="62.5" r=".51" fill="#fff" stroke="#000" stroke-width=".2"/>
<circle cx="165.2" cy="60" r=".76" fill="#008000" stroke="#008000" stroke-width=".2"/>
<circle cx="165.2" cy="60" r=".51" fill="#fff" stroke="#000" stroke-width=".2"/>
<circle cx="167.8" cy="62.5" r=".76" fill="#008000" stroke="#008000" stroke-width=".2"/>
<circle cx="167.8" cy="62.5" r=".51" fill="#fff" stroke="#000" stroke-width=".2"/>
<circle cx="167.8" cy="60" r=".76" fill="#008000" stroke="#008000" stroke-width=".2"/>
<circle cx="167.8" cy="60" r=".51" fill="#fff" stroke="#000" stroke-width=".2"/>
<circle cx="170.3" cy="62.5" r=".76" fill="#008000" stroke="#008000" stroke-width=".2"/>
<circle cx="170.3" cy="62.5" r=".51" fill="#fff" stroke="#000" stroke-width=".2"/>
<circle cx="170.3" cy="60" r=".76" fill="#008000" stroke="#008000" stroke-width=".2"/>
<circle cx="170.3" cy="60" r=".51" fill="#fff" stroke="#000" stroke-width=".2"/>
<circle cx="172.8" cy="62.5" r=".76" fill="#008000" stroke="#008000" stroke-width=".2"/>
<circle cx="172.8" cy="62.5" r=".51" fill="#fff" stroke="#000" stroke-width=".2"/>
<circle cx="172.8" cy="60" r=".76" fill="#008000" stroke="#008000" stroke-width=".2"/>
<circle cx="172.8" cy="60" r=".51" fill="#fff" stroke="#000" stroke-width=".2"/>
<circle cx="175.4" cy="62.5" r=".76" fill="#008000" stroke="#008000" stroke-width=".2"/>
<circle cx="175.4" cy="62.5" r=".51" fill="#fff" stroke="#000" stroke-width=".2"/>
<circle cx="175.4" cy="60" r=".76" fill="#008000" stroke="#008000" stroke-width=".2"/>
<circle cx="175.4" cy="60" r=".51" fill="#fff" stroke="#000" stroke-width=".2"/>
<circle cx="177.9" cy="62.5" r=".76" fill="#008000" stroke="#008000" stroke-width=".2"/>
<circle cx="177.9" cy="62.5" r=".51" fill="#fff" stroke="#000" stroke-width=".2"/>
<circle cx="177.9" cy="60" r=".76" fill="#008000" stroke="#008000" stroke-width=".2"/>
<circle cx="177.9" cy="60" r=".51" fill="#fff" stroke="#000" stroke-width=".2"/>
<circle cx="180.5" cy="62.5" r=".76" fill="#008000" stroke="#008000" stroke-width=".2"/>
<circle cx="180.5" cy="62.5" r=".51" fill="#fff" stroke="#000" stroke-width=".2"/>
<circle cx="180.5" cy="60" r=".76" fill="#008000" stroke="#008000" stroke-width=".2"/>
<circle cx="180.5" cy="60" r=".51" fill="#fff" stroke="#000" stroke-width=".2"/>
<circle cx="117" cy="67.6" r=".76" fill="#008000" stroke="#008000" stroke-width=".2"/>
<circle cx="117" cy="67.6" r=".51" fill="#fff" stroke="#000" stroke-width=".2"/>
<circle cx="117" cy="65.1" r=".76" fill="#008000" stroke="#008000" stroke-width=".2"/>
<circle cx="117" cy="65.1" r=".51" fill="#fff" stroke="#000" stroke-width=".2"/>
<circle cx="119.5" cy="67.6" r=".76" fill="#008000" stroke="#008000" stroke-width=".2"/>
<circle cx="119.5" cy="67.6" r=".51" fill="#fff" stroke="#000" stroke-width=".2"/>
<circle cx="119.5" cy="65.1" r=".76" fill="#008000" stroke="#008000" stroke-width=".2"/>
<circle cx="119.5" cy="65.1" r=".51" fill="#fff" stroke="#000" stroke-width=".2"/>
<circle cx="122.1" cy="67.6" r=".76" fill="#008000" stroke="#008000" stroke-width=".2"/>
<circle cx="122.1" cy="67.6" r=".51" fill="#fff" stroke="#000" stroke-width=".2"/>
<circle cx="122.1" cy="65.1" r=".76" fill="#008000" stroke="#008000" stroke-width=".2"/>
<circle cx="122.1" cy="65.1" r=".51" fill="#fff" stroke="#000" stroke-width=".2"/>
<circle cx="124.6" cy="67.6" r=".76" fill="#008000" stroke="#008000" stroke-width=".2"/>
<circle cx="124.6" cy="67.6" r=".51" fill="#fff" stroke="#000" stroke-width=".2"/>
<circle cx="124.6" cy="65.1" r=".76" fill="#008000" stroke="#008000" stroke-width=".2"/>
<circle cx="124.6" cy="65.1" r=".51" fill="#fff" stroke="#000" stroke-width=".2"/>
<circle cx="127.1" cy="67.6" r=".76" fill="#008000" stroke="#008000" stroke-width=".2"/>
<circle cx="127.1" cy="67.6" r=".51" fill="#fff" stroke="#000" stroke-width=".2"/>
<circle cx="127.1" cy="65.1" r=".76" fill="#008000" stroke="#008000" stroke-width=".2"/>
<circle cx="127.1" cy="65.1" r=".51" fill="#fff" stroke="#000" stroke-width=".2"/>
<circle cx="129.7" cy="67.6" r=".76" fill="#008000" stroke="#008000" stroke-width=".2"/>
<circle cx="129.7" cy="67.6" r=".51" fill="#fff" stroke="#000" stroke-width=".2"/>
<circle cx="129.7" cy="65.1" r=".76" fill="#008000" stroke="#008000" stroke-width=".2"/>
<circle cx="129.7" cy="65.1" r=".51" fill="#fff" stroke="#000" stroke-width=".2"/>
<circle cx="132.2" cy="67.6" r=".76" fill="#008000" stroke="#008000" stroke-width=".2"/>
<circle cx="132.2" cy="67.6" r=".51" fill="#fff" stroke="#000" stroke-width=".2"/>
<circle cx="132.2" cy="65.1" r=".76" fill="#008000" stroke="#008000" stroke-width=".2"/>
<circle cx="132.2" cy="65.1" r=".51" fill="#fff" stroke="#000" stroke-width=".2"/>
<circle cx="134.8" cy="67.6" r=".76" fill="#008000" stroke="#008000" stroke-width=".2"/>
<circle cx="134.8" cy="67.6" r=".51" fill="#fff" stroke="#000" stroke-width=".2"/>
<circle cx="134.8" cy="65.1" r=".76" fill="#008000" stroke="#008000" stroke-width=".2"/>
<circle cx="134.8" cy="65.1" r=".51" fill="#fff" stroke="#000" stroke-width=".2"/>
<circle cx="137.3" cy="67.6" r=".76" fill="#008000" stroke="#008000" stroke-width=".2"/>
<circle cx="137.3" cy="67.6" r=".51" fill="#fff" stroke="#000" stroke-width=".2"/>
<circle cx="137.3" cy="65.1" r=".76" fill="#008000" stroke="#008000" stroke-width=".2"/>
<circle cx="137.3" cy="65.1" r=".51" fill="#fff" stroke="#000" stroke-width=".2"/>
<circle cx="139.8" cy="67.6" r=".76" fill="#008000" stroke="#008000" stroke-width=".2"/>
<circle cx="139.8" cy="67.6" r=".51" fill="#fff" stroke="#000" stroke-width=".2"/>
<circle cx="139.8" cy="65.1" r=".76" fill="#008000" stroke="#008000" stroke-width=".2"/>
<circle cx="139.8" cy="65.1" r=".51" fill="#fff" stroke="#000" stroke-width=".2"/>
<circle cx="142.4" cy="67.6" r=".76" fill="#008000" stroke="#008000" stroke-width=".2"/>
<circle cx="142.4" cy="67.6" r=".51" fill="#fff" stroke="#000" stroke-width=".2"/>
<circle cx="142.4" cy="65.1" r=".76" fill="#008000" stroke="#008000" stroke-width=".2"/>
<circle cx="142.4" cy="65.1" r=".51" fill="#fff" stroke="#000" stroke-width=".2"/>
<circle cx="144.9" cy="67.6" r=".76" fill="#008000" stroke="#008000" stroke-width=".2"/>
<circle cx="144.9" cy="67.6" r=".51" fill="#fff" stroke="#000" stroke-width=".2"/>
<circle cx="144.9" cy="65.1" r=".76" fill="#008000" stroke="#008000" stroke-width=".2"/>
<circle cx="144.9" cy="65.1" r=".51" fill="#fff" stroke="#000" stroke-width=".2"/>
<circle cx="147.4" cy="67.6" r=".76" fill="#008000" stroke="#008000" stroke-width=".2"/>
<circle cx="147.4" cy="67.6" r=".51" fill="#fff" stroke="#000" stroke-width=".2"/>
<circle cx="147.4" cy="65.1" r=".76" fill="#008000" stroke="#008000" stroke-width=".2"/>
<circle cx="147.4" cy="65.1" r=".51" fill="#fff" stroke="#000" stroke-width=".2"/>
<circle cx="150" cy="67.6" r=".76" fill="#008000" stroke="#008000" stroke-width=".2"/>
<circle cx="150" cy="67.6" r=".51" fill="#fff" stroke="#000" stroke-width=".2"/>
<circle cx="150" cy="65.1" r=".76" fill="#008000" stroke="#008000" stroke-width=".2"/>
<circle cx="150" cy="65.1" r=".51" fill="#fff" stroke="#000" stroke-width=".2"/>
<circle cx="152.5" cy="67.6" r=".76" fill="#008000" stroke="#008000" stroke-width=".2"/>
<circle cx="152.5" cy="67.6" r=".51" fill="#fff" stroke="#000" stroke-width=".2"/>
<circle cx="152.5" cy="65.1" r=".76" fill="#008000" stroke="#008000" stroke-width=".2"/>
<circle cx="152.5" cy="65.1" r=".51" fill="#fff" stroke="#000" stroke-width=".2"/>
<circle cx="155.1" cy="67.6" r=".76" fill="#008000" stroke="#008000" stroke-width=".2"/>
<circle cx="155.1" cy="67.6" r=".51" fill="#fff" stroke="#000" stroke-width=".2"/>
<circle cx="155.1" cy="65.1" r=".76" fill="#008000" stroke="#008000" stroke-width=".2"/>
<circle cx="155.1" cy="65.1" r=".51" fill="#fff" stroke="#000" stroke-width=".2"/>
<circle cx="157.6" cy="67.6" r=".76" fill="#008000" stroke="#008000" stroke-width=".2"/>
<circle cx="157.6" cy="67.6" r=".51" fill="#fff" stroke="#000" stroke-width=".2"/>
<circle cx="157.6" cy="65.1" r=".76" fill="#008000" stroke="#008000" stroke-width=".2"/>
<circle cx="157.6" cy="65.1" r=".51" fill="#fff" stroke="#000" stroke-width=".2"/>
<circle cx="160.1" cy="67.6" r=".76" fill="#008000" stroke="#008000" stroke-width=".2"/>
<circle cx="160.1" cy="67.6" r=".51" fill="#fff" stroke="#000" stroke-width=".2"/>
<circle cx="160.1" cy="65.1" r=".76" fill="#008000" stroke="#008000" stroke-width=".2"/>
<circle cx="160.1" cy="65.1" r=".51" fill="#fff" stroke="#000" stroke-width=".2"/>
<circle cx="162.7" cy="67.6" r=".76" fill="#008000" stroke="#008000" stroke-width=".2"/>
<circle cx="162.7" cy="67.6" r=".51" fill="#fff" stroke="#000" stroke-width=".2"/>
<circle cx="162.7" cy="65.1" r=".76" fill="#008000" stroke="#008000" stroke-width=".2"/>
<circle cx="162.7" cy="65.1" r=".51" fill="#fff" stroke="#000" stroke-width=".2"/>
<circle cx="165.2" cy="67.6" r=".76" fill="#008000" stroke="#008000" stroke-width=".2"/>
<circle cx="165.2" cy="67.6" r=".51" fill="#fff" stroke="#000" stroke-width=".2"/>
<circle cx="165.2" cy="65.1" r=".76" fill="#008000" stroke="#008000" stroke-width=".2"/>
<circle cx="165.2" cy="65.1" r=".51" fill="#fff" stroke="#000" stroke-width=".2"/>
<circle cx="167.8" cy="67.6" r=".76" fill="#008000" stroke="#008000" stroke-width=".2"/>
<circle cx="167.8" cy="67.6" r=".51" fill="#fff" stroke="#000" stroke-width=".2"/>
<circle cx="167.8" cy="65.1" r=".76" fill="#008000" stroke="#008000" stroke-width=".2"/>
<circle cx="167.8" cy="65.1" r=".51" fill="#fff" stroke="#000" stroke-width=".2"/>
<circle cx="170.3" cy="67.6" r=".76" fill="#008000" stroke="#008000" stroke-width=".2"/>
<circle cx="170.3" cy="67.6" r=".51" fill="#fff" stroke="#000" stroke-width=".2"/>
<circle cx="170.3" cy="65.1" r=".76" fill="#008000" stroke="#008000" stroke-width=".2"/>
<circle cx="170.3" cy="65.1" r=".51" fill="#fff" stroke="#000" stroke-width=".2"/>
<circle cx="172.8" cy="67.6" r=".76" fill="#008000" stroke="#008000" stroke-width=".2"/>
<circle cx="172.8" cy="67.6" r=".51" fill="#fff" stroke="#000" stroke-width=".2"/>
<circle cx="172.8" cy="65.1" r=".76" fill="#008000" stroke="#008000" stroke-width=".2"/>
<circle cx="172.8" cy="65.1" r=".51" fill="#fff" stroke="#000" stroke-width=".2"/>
<circle cx="175.4" cy="67.6" r=".76" fill="#008000" stroke="#008000" stroke-width=".2"/>
<circle cx="175.4" cy="67.6" r=".51" fill="#fff" stroke="#000" stroke-width=".2"/>
<circle cx="175.4" cy="65.1" r=".76" fill="#008000" stroke="#008000" stroke-width=".2"/>
<circle cx="175.4" cy="65.1" r=".51" fill="#fff" stroke="#000" stroke-width=".2"/>
<circle cx="177.9" cy="67.6" r=".76" fill="#008000" stroke="#008000" stroke-width=".2"/>
<circle cx="177.9" cy="67.6" r=".51" fill="#fff" stroke="#000" stroke-width=".2"/>
<circle cx="177.9" cy="65.1" r=".76" fill="#008000" stroke="#008000" stroke-width=".2"/>
<circle cx="177.9" cy="65.1" r=".51" fill="#fff" stroke="#000" stroke-width=".2"/>
<circle cx="180.5" cy="67.6" r=".76" fill="#008000" stroke="#008000" stroke-width=".2"/>
<circle cx="180.5" cy="67.6" r=".51" fill="#fff" stroke="#000" stroke-width=".2"/>
<circle cx="180.5" cy="65.1" r=".76" fill="#008000" stroke="#008000" stroke-width=".2"/>
<circle cx="180.5" cy="65.1" r=".51" fill="#fff" stroke="#000" stroke-width=".2"/>
<circle cx="186.8" cy="103.7" r=".51" fill="#008000" stroke="#008000" stroke-width=".2"/>
<circle cx="186.8" cy="103.7" r=".3" fill="#fff" stroke="#000" stroke-width=".2"/>
<circle cx="183.3" cy="103.7" r=".51" fill="#008000" stroke="#008000" stroke-width=".2"/>
<circle cx="183.3" cy="103.7" r=".3" fill="#fff" stroke="#000" stroke-width=".2"/>
<circle cx="185.1" cy="128.8" r=".51" fill="#008000" stroke="#008000" stroke-width=".2"/>
<circle cx="185.1" cy="128.8" r=".3" fill="#fff" stroke="#000" stroke-width=".2"/>
<circle cx="187.7" cy="126.2" r=".51" fill="#008000" stroke="#008000" stroke-width=".2"/>
<circle cx="187.7" cy="126.2" r=".3" fill="#fff" stroke="#000" stroke-width=".2"/>
<circle cx="186.9" cy="134.9" r=".51" fill="#008000" stroke="#008000" stroke-width=".2"/>
<circle cx="186.9" cy="134.9" r=".3" fill="#fff" stroke="#000" stroke-width=".2"/>
<circle cx="183.1" cy="134.9" r=".51" fill="#008000" stroke="#008000" stroke-width=".2"/>
<circle cx="183.1" cy="134.9" r=".3" fill="#fff" stroke="#000" stroke-width=".2"/>
<circle cx="177.4" cy="130.7" r=".51" fill="#008000" stroke="#008000" stroke-width=".2"/>
<circle cx="177.4" cy="130.7" r=".3" fill="#fff" stroke="#000" stroke-width=".2"/>
<circle cx="182.3" cy="130.7" r=".51" fill="#008000" stroke="#008000" stroke-width=".2"/>
<circle cx="182.3" cy="130.7" r=".3" fill="#fff" stroke="#000" stroke-width=".2"/>
<circle cx="156.5" cy="73.2" r=".51" fill="#008000" stroke="#008000" stroke-width=".2"/>
<circle cx="156.5" cy="73.2" r=".3" fill="#fff" stroke="#000" stroke-width=".2"/>
<circle cx="159.1" cy="134.9" r=".51" fill="#008000" stroke="#008000" stroke-width=".2"/>
<circle cx="159.1" cy="134.9" r=".3" fill="#fff" stroke="#000" stroke-width=".2"/>
<circle cx="145.4" cy="69.7" r=".51" fill="#008000" stroke="#008000" stroke-width=".2"/>
<circle cx="145.4" cy="69.7" r=".3" fill="#fff" stroke="#000" stroke-width=".2"/>
<circle cx="133.7" cy="93.8" r=".51" fill="#008000" stroke="#008000" stroke-width=".2"/>
<circle cx="133.7" cy="93.8" r=".3" fill="#fff" stroke="#000" stroke-width=".2"/>
<circle cx="125.8" cy="139" r=".51" fill="#008000" stroke="#008000" stroke-width=".2"/>
<circle cx="125.8" cy="139" r=".3" fill="#fff" stroke="#000" stroke-width=".2"/>
<circle cx="141.7" cy="135" r=".51" fill="#008000" stroke="#008000" stroke-width=".2"/>
<circle cx="141.7" cy="135" r=".3" fill="#fff" stroke="#000" stroke-width=".2"/>
<circle cx="143" cy="130.3" r=".51" fill="#008000" stroke="#008000" stroke-width=".2"/>
<circle cx="143" cy="130.3" r=".3" fill="#fff" stroke="#000" stroke-width=".2"/>
<circle cx="147.8" cy="136.2" r=".51" fill="#008000" stroke="#008000" stroke-width=".2"/>
<circle cx="147.8" cy="136.2" r=".3" fill="#fff" stroke="#000" stroke-width=".2"/>
<circle cx="147.8" cy="132.4" r=".51" fill="#008000" stroke="#008000" stroke-width=".2"/>
<circle cx="147.8" cy="132.4" r=".3" fill="#fff" stroke="#000" stroke-width=".2"/>
<circle cx="180.4" cy="96" r=".51" fill="#008000" stroke="#008000" stroke-width=".2"/>
<circle cx="180.4" cy="96" r=".3" fill="#fff" stroke="#000" stroke-width=".2"/>
<circle cx="175.3" cy="102.6" r=".51" fill="#008000" stroke="#008000" stroke-width=".2"/>
<circle cx="175.3" cy="102.6" r=".3" fill="#fff" stroke="#000" stroke-width=".2"/>
<circle cx="191.1" cy="91.4" r=".51" fill="#008000" stroke="#008000" stroke-width=".2"/>
<circle cx="191.1" cy="91.4" r=".3" fill="#fff" stroke="#000" stroke-width=".2"/>
<circle cx="151.9" cy="83.2" r=".51" fill="#008000" stroke="#008000" stroke-width=".2"/>
<circle cx="151.9" cy="83.2" r=".3" fill="#fff" stroke="#000" stroke-width=".2"/>
<circle cx="132.8" cy="137.5" r=".51" fill="#008000" stroke="#008000" stroke-width=".2"/>
<circle cx="132.8" cy="137.5" r=".3" fill="#fff" stroke="#000" stroke-width=".2"/>
<circle cx="130.8" cy="130.5" r=".51" fill="#008000" stroke="#008000" stroke-width=".2"/>
<circle cx="130.8" cy="130.5" r=".3" fill="#fff" stroke="#000" stroke-width=".2"/>
<circle cx="149.5" cy="137.7" r=".51" fill="#008000" stroke="#008000" stroke-width=".2"/>
<circle cx="149.5" cy="137.7" r=".3" fill="#fff" stroke="#000" stroke-width=".2"/>
<circle cx="148.4" cy="128.6" r=".51" fill="#008000" stroke="#008000" stroke-width=".2"/>
<circle cx="148.4" cy="128.6" r=".3" fill="#fff" stroke="#000" stroke-width=".2"/>
<circle cx="127.2" cy="70.6" r=".51" fill="#008000" stroke="#008000" stroke-width=".2"/>
<circle cx="127.2" cy="70.6" r=".3" fill="#fff" stroke="#000" stroke-width=".2"/>
<circle cx="127.2" cy="75.1" r=".51" fill="#008000" stroke="#008000" stroke-width=".2"/>
<circle cx="127.2" cy="75.1" r=".3" fill="#fff" stroke="#000" stroke-width=".2"/>
<circle cx="180.1" cy="127" r=".51" fill="#008000" stroke="#008000" stroke-width=".2"/>
<circle cx="180.1" cy="127" r=".3" fill="#fff" stroke="#000" stroke-width=".2"/>
<circle cx="191.1" cy="122.6" r=".51" fill="#008000" stroke="#008000" stroke-width=".2"/>
<circle cx="191.1" cy="122.6" r=".3" fill="#fff" stroke="#000" stroke-width=".2"/>
<circle cx="175.3" cy="134.6" r=".51" fill="#008000" stroke="#008000" stroke-width=".2"/>
<circle cx="175.3" cy="134.6" r=".3" fill="#fff" stroke="#000" stroke-width=".2"/>
<circle cx="133.9" cy="128.5" r=".51" fill="#008000" stroke="#008000" stroke-width=".2"/>
<circle cx="133.9" cy="128.5" r=".3" fill="#fff" stroke="#000" stroke-width=".2"/>
<circle cx="149.3" cy="90.6" r=".51" fill="#008000" stroke="#008000" stroke-width=".2"/>
<circle cx="149.3" cy="90.6" r=".3" fill="#fff" stroke="#000" stroke-width=".2"/>
<circle cx="127.2" cy="79" r=".51" fill="#008000" stroke="#008000" stroke-width=".2"/>
<circle cx="127.2" cy="79" r=".3" fill="#fff" stroke="#000" stroke-width=".2"/>
<circle cx="142.1" cy="78.7" r=".51" fill="#008000" stroke="#008000" stroke-width=".2"/>
<circle cx="142.1" cy="78.7" r=".3" fill="#fff" stroke="#000" stroke-width=".2"/>
<circle cx="146.2" cy="78.4" r=".51" fill="#008000" stroke="#008000" stroke-width=".2"/>
<circle cx="146.2" cy="78.4" r=".3" fill="#fff" stroke="#000" stroke-width=".2"/>
<circle cx="146" cy="74.2" r=".51" fill="#008000" stroke="#008000" stroke-width=".2"/>
<circle cx="146" cy="74.2" r=".3" fill="#fff" stroke="#000" stroke-width=".2"/>
<circle cx="146.3" cy="124.5" r=".51" fill="#008000" stroke="#008000" stroke-width=".2"/>
<circle cx="146.3" cy="124.5" r=".3" fill="#fff" stroke="#000" stroke-width=".2"/>
<circle cx="136.8" cy="111.2" r=".51" fill="#008000" stroke="#008000" stroke-width=".2"/>
<circle cx="136.8" cy="111.2" r=".3" fill="#fff" stroke="#000" stroke-width=".2"/>
<circle cx="138.4" cy="117.2" r=".51" fill="#008000" stroke="#008000" stroke-width=".2"/>
<circle cx="138.4" cy="117.2" r=".3" fill="#fff" stroke="#000" stroke-width=".2"/>
<circle cx="113.7" cy="87.7" r=".51" fill="#008000" stroke="#008000" stroke-width=".2"/>
<circle cx="113.7" cy="87.7" r=".3" fill="#fff" stroke="#000" stroke-width=".2"/>
<circle cx="121.2" cy="87.9" r=".51" fill="#008000" stroke="#008000" stroke-width=".2"/>
<circle cx="121.2" cy="87.9" r=".3" fill="#fff" stroke="#000" stroke-width=".2"/>
<circle cx="177.8" cy="73.2" r=".51" fill="#008000" stroke="#008000" stroke-width=".2"/>
<circle cx="177.8" cy="73.2" r=".3" fill="#fff" stroke="#000" stroke-width=".2"/>
<circle cx="125.8" cy="129.3" r=".51" fill="#008000" stroke="#008000" stroke-width=".2"/>
<circle cx="125.8" cy="129.3" r=".3" fill="#fff" stroke="#000" stroke-width=".2"/>
<circle cx="125.8" cy="134.8" r=".51" fill="#008000" stroke="#008000" stroke-width=".2"/>
<circle cx="125.8" cy="134.8" r=".3" fill="#fff" stroke="#000" stroke-width=".2"/>
<circle cx="131.4" cy="136" r=".51" fill="#008000" stroke="#008000" stroke-width=".2"/>
<circle cx="131.4" cy="136" r=".3" fill="#fff" stroke="#000" stroke-width=".2"/>
<circle cx="131.4" cy="132.7" r=".51" fill="#008000" stroke="#008000" stroke-width=".2"/>
<circle cx="131.4" cy="132.7" r=".3" fill="#fff" stroke="#000" stroke-width=".2"/>
<circle cx="153.7" cy="73.1" r=".51" fill="#008000" stroke="#008000" stroke-width=".2"/>
<circle cx="153.7" cy="73.1" r=".3" fill="#fff" stroke="#000" stroke-width=".2"/>
<circle cx="158.1" cy="90.7" r=".51" fill="#008000" stroke="#008000" stroke-width=".2"/>
<circle cx="158.1" cy="90.7" r=".3" fill="#fff" stroke="#000" stroke-width=".2"/>
<circle cx="142.4" cy="69.7" r=".51" fill="#008000" stroke="#008000" stroke-width=".2"/>
<circle cx="142.4" cy="69.7" r=".3" fill="#fff" stroke="#000" stroke-width=".2"/>
<circle cx="129.8" cy="75.1" r=".51" fill="#008000" stroke="#008000" stroke-width=".2"/>
<circle cx="129.8" cy="75.1" r=".3" fill="#fff" stroke="#000" stroke-width=".2"/>
<circle cx="129.8" cy="79" r=".51" fill="#008000" stroke="#008000" stroke-width=".2"/>
<circle cx="129.8" cy="79" r=".3" fill="#fff" stroke="#000" stroke-width=".2"/>
<circle cx="177.3" cy="121.1" r=".51" fill="#008000" stroke="#008000" stroke-width=".2"/>
<circle cx="177.3" cy="121.1" r=".3" fill="#fff" stroke="#000" stroke-width=".2"/>
<circle cx="177.3" cy="124.5" r=".51" fill="#008000" stroke="#008000" stroke-width=".2"/>
<circle cx="177.3" cy="124.5" r=".3" fill="#fff" stroke="#000" stroke-width=".2"/>
<circle cx="156.5" cy="116.9" r=".51" fill="#008000" stroke="#008000" stroke-width=".2"/>
<circle cx="156.5" cy="116.9" r=".3" fill="#fff" stroke="#000" stroke-width=".2"/>
<circle cx="164" cy="117.9" r=".51" fill="#008000" stroke="#008000" stroke-width=".2"/>
<circle cx="164" cy="117.9" r=".3" fill="#fff" stroke="#000" stroke-width=".2"/>
<circle cx="130.8" cy="70.8" r=".51" fill="#008000" stroke="#008000" stroke-width=".2"/>
<circle cx="130.8" cy="70.8" r=".3" fill="#fff" stroke="#000" stroke-width=".2"/>
<circle cx="157.5" cy="75.4" r=".51" fill="#008000" stroke="#008000" stroke-width=".2"/>
<circle cx="157.5" cy="75.4" r=".3" fill="#fff" stroke="#000" stroke-width=".2"/>
<circle cx="136.3" cy="116.3" r=".51" fill="#008000" stroke="#008000" stroke-width=".2"/>
<circle cx="136.3" cy="116.3" r=".3" fill="#fff" stroke="#000" stroke-width=".2"/>
<circle cx="150.5" cy="115.8" r=".51" fill="#008000" stroke="#008000" stroke-width=".2"/>
<circle cx="150.5" cy="115.8" r=".3" fill="#fff" stroke="#000" stroke-width=".2"/>
<circle cx="145.1" cy="75.4" r=".51" fill="#008000" stroke="#008000" stroke-width=".2"/>
<circle cx="145.1" cy="75.4" r=".3" fill="#fff" stroke="#000" stroke-width=".2"/>
<circle cx="145.6" cy="114.6" r=".51" fill="#008000" stroke="#008000" stroke-width=".2"/>
<circle cx="145.6" cy="114.6" r=".3" fill="#fff" stroke="#000" stroke-width=".2"/>
<circle cx="140.7" cy="115.6" r=".51" fill="#008000" stroke="#008000" stroke-width=".2"/>
<circle cx="140.7" cy="115.6" r=".3" fill="#fff" stroke="#000" stroke-width=".2"/>
<circle cx="131.5" cy="115.3" r=".51" fill="#008000" stroke="#008000" stroke-width=".2"/>
<circle cx="131.5" cy="115.3" r=".3" fill="#fff" stroke="#000" stroke-width=".2"/>
<circle cx="127.5" cy="116" r=".51" fill="#008000" stroke="#008000" stroke-width=".2"/>
<circle cx="127.5" cy="116" r=".3" fill="#fff" stroke="#000" stroke-width=".2"/>
<circle cx="129.7" cy="82" r=".51" fill="#008000" stroke="#008000" stroke-width=".2"/>
<circle cx="129.7" cy="82" r=".3" fill="#fff" stroke="#000" stroke-width=".2"/>
<circle cx="164.8" cy="76.6" r=".51" fill="#008000" stroke="#008000" stroke-width=".2"/>
<circle cx="164.8" cy="76.6" r=".3" fill="#fff" stroke="#000" stroke-width=".2"/>
<circle cx="135.1" cy="69.9" r=".51" fill="#008000" stroke="#008000" stroke-width=".2"/>
<circle cx="135.1" cy="69.9" r=".3" fill="#fff" stroke="#000" stroke-width=".2"/>
<circle cx="140" cy="82.3" r=".51" fill="#008000" stroke="#008000" stroke-width=".2"/>
<circle cx="140" cy="82.3" r=".3" fill="#fff" stroke="#000" stroke-width=".2"/>
<circle cx="144.7" cy="95.7" r=".51" fill="#008000" stroke="#008000" stroke-width=".2"/>
<circle cx="144.7" cy="95.7" r=".3" fill="#fff" stroke="#000" stroke-width=".2"/>
<circle cx="138.3" cy="83.6" r=".51" fill="#008000" stroke="#008000" stroke-width=".2"/>
<circle cx="138.3" cy="83.6" r=".3" fill="#fff" stroke="#000" stroke-width=".2"/>
<circle cx="143.4" cy="96.3" r=".51" fill="#008000" stroke="#008000" stroke-width=".2"/>
<circle cx="143.4" cy="96.3" r=".3" fill="#fff" stroke="#000" stroke-width=".2"/>
<circle cx="125.9" cy="75.1" r=".51" fill="#008000" stroke="#008000" stroke-width=".2"/>
<circle cx="125.9" cy="75.1" r=".3" fill="#fff" stroke="#000" stroke-width=".2"/>
<circle cx="125.9" cy="79" r=".51" fill="#008000" stroke="#008000" stroke-width=".2"/>
<circle cx="125.9" cy="79" r=".3" fill="#fff" stroke="#000" stroke-width=".2"/>
<circle cx="140.4" cy="91.8" r=".51" fill="#008000" stroke="#008000" stroke-width=".2"/>
<circle cx="140.4" cy="91.8" r=".3" fill="#fff" stroke="#000" stroke-width=".2"/>
<circle cx="125.9" cy="95.4" r=".51" fill="#008000" stroke="#008000" stroke-width=".2"/>
<circle cx="125.9" cy="95.4" r=".3" fill="#fff" stroke="#000" stroke-width=".2"/>
<circle cx="133.2" cy="110.3" r=".51" fill="#008000" stroke="#008000" stroke-width=".2"/>
<circle cx="133.2" cy="110.3" r=".3" fill="#fff" stroke="#000" stroke-width=".2"/>
<circle cx="122.9" cy="105.2" r=".51" fill="#008000" stroke="#008000" stroke-width=".2"/>
<circle cx="122.9" cy="105.2" r=".3" fill="#fff" stroke="#000" stroke-width=".2"/>
<circle cx="115.2" cy="74.7" r=".51" fill="#008000" stroke="#008000" stroke-width=".2"/>
<circle cx="115.2" cy="74.7" r=".3" fill="#fff" stroke="#000" stroke-width=".2"/>
<circle cx="110.6" cy="80.3" r=".51" fill="#008000" stroke="#008000" stroke-width=".2"/>
<circle cx="110.6" cy="80.3" r=".3" fill="#fff" stroke="#000" stroke-width=".2"/>
<circle cx="147.7" cy="109.1" r=".51" fill="#008000" stroke="#008000" stroke-width=".2"/>
<circle cx="147.7" cy="109.1" r=".3" fill="#fff" stroke="#000" stroke-width=".2"/>
<circle cx="124.4" cy="106.8" r=".51" fill="#008000" stroke="#008000" stroke-width=".2"/>
<circle cx="124.4" cy="106.8" r=".3" fill="#fff" stroke="#000" stroke-width=".2"/>
<circle cx="128.4" cy="75.1" r=".51" fill="#008000" stroke="#008000" stroke-width=".2"/>
<circle cx="128.4" cy="75.1" r=".3" fill="#fff" stroke="#000" stroke-width=".2"/>
<circle cx="128.4" cy="79" r=".51" fill="#008000" stroke="#008000" stroke-width=".2"/>
<circle cx="128.4" cy="79" r=".3" fill="#fff" stroke="#000" stroke-width=".2"/>
<circle cx="142" cy="93.2" r=".51" fill="#008000" stroke="#008000" stroke-width=".2"/>
<circle cx="142" cy="93.2" r=".3" fill="#fff" stroke="#000" stroke-width=".2"/>
<circle cx="128.4" cy="98.3" r=".51" fill="#008000" stroke="#008000" stroke-width=".2"/>
<circle cx="128.4" cy="98.3" r=".3" fill="#fff" stroke="#000" stroke-width=".2"/>
<circle cx="147.8" cy="92.9" r=".51" fill="#008000" stroke="#008000" stroke-width=".2"/>
<circle cx="147.8" cy="92.9" r=".3" fill="#fff" stroke="#000" stroke-width=".2"/>
<circle cx="150.5" cy="98.8" r=".51" fill="#008000" stroke="#008000" stroke-width=".2"/>
<circle cx="150.5" cy="98.8" r=".3" fill="#fff" stroke="#000" stroke-width=".2"/>
<circle cx="177.1" cy="83" r=".51" fill="#008000" stroke="#008000" stroke-width=".2"/>
<circle cx="177.1" cy="83" r=".3" fill="#fff" stroke="#000" stroke-width=".2"/>
<circle cx="176.2" cy="78.7" r=".51" fill="#008000" stroke="#008000" stroke-width=".2"/>
<circle cx="176.2" cy="78.7" r=".3" fill="#fff" stroke="#000" stroke-width=".2"/>
<circle cx="185.2" cy="97.5" r=".51" fill="#008000" stroke="#008000" stroke-width=".2"/>
<circle cx="185.2" cy="97.5" r=".3" fill="#fff" stroke="#000" stroke-width=".2"/>
<circle cx="187.8" cy="95.3" r=".51" fill="#008000" stroke="#008000" stroke-width=".2"/>
<circle cx="187.8" cy="95.3" r=".3" fill="#fff" stroke="#000" stroke-width=".2"/>
<circle cx="177.3" cy="99" r=".51" fill="#008000" stroke="#008000" stroke-width=".2"/>
<circle cx="177.3" cy="99" r=".3" fill="#fff" stroke="#000" stroke-width=".2"/>
<circle cx="182.5" cy="99" r=".51" fill="#008000" stroke="#008000" stroke-width=".2"/>
<circle cx="182.5" cy="99" r=".3" fill="#fff" stroke="#000" stroke-width=".2"/>
<circle cx="175.7" cy="84.7" r=".51" fill="#008000" stroke="#008000" stroke-width=".2"/>
<circle cx="175.7" cy="84.7" r=".3" fill="#fff" stroke="#000" stroke-width=".2"/>
<circle cx="178.8" cy="111.7" r=".51" fill="#008000" stroke="#008000" stroke-width=".2"/>
<circle cx="178.8" cy="111.7" r=".3" fill="#fff" stroke="#000" stroke-width=".2"/>
<circle cx="138.6" cy="69.8" r=".51" fill="#008000" stroke="#008000" stroke-width=".2"/>
<circle cx="138.6" cy="69.8" r=".3" fill="#fff" stroke="#000" stroke-width=".2"/>
<circle cx="145.2" cy="82.3" r=".51" fill="#008000" stroke="#008000" stroke-width=".2"/>
<circle cx="145.2" cy="82.3" r=".3" fill="#fff" stroke="#000" stroke-width=".2"/>
<circle cx="150.5" cy="94.1" r=".51" fill="#008000" stroke="#008000" stroke-width=".2"/>
<circle cx="150.5" cy="94.1" r=".3" fill="#fff" stroke="#000" stroke-width=".2"/>
<circle cx="186.7" cy="65.7" r=".51" fill="#008000" stroke="#008000" stroke-width=".2"/>
<circle cx="186.7" cy="65.7" r=".3" fill="#fff" stroke="#000" stroke-width=".2"/>
<circle cx="177.4" cy="89.1" r=".51" fill="#008000" stroke="#008000" stroke-width=".2"/>
<circle cx="177.4" cy="89.1" r=".3" fill="#fff" stroke="#000" stroke-width=".2"/>
<circle cx="177.4" cy="92.6" r=".51" fill="#008000" stroke="#008000" stroke-width=".2"/>
<circle cx="177.4" cy="92.6" r=".3" fill="#fff" stroke="#000" stroke-width=".2"/>
<circle cx="106.2" cy="74.2" r=".51" fill="#008000" stroke="#008000" stroke-width=".2"/>
<circle cx="106.2" cy="74.2" r=".3" fill="#fff" stroke="#000" stroke-width=".2"/>
<circle cx="113.1" cy="66.4" r=".51" fill="#008000" stroke="#008000" stroke-width=".2"/>
<circle cx="113.1" cy="66.4" r=".3" fill="#fff" stroke="#000" stroke-width=".2"/>
<circle cx="173.7" cy="79.2" r=".51" fill="#008000" stroke="#008000" stroke-width=".2"/>
<circle cx="173.7" cy="79.2" r=".3" fill="#fff" stroke="#000" stroke-width=".2"/>
<circle cx="186.7" cy="73.5" r=".51" fill="#008000" stroke="#008000" stroke-width=".2"/>
<circle cx="186.7" cy="73.5" r=".3" fill="#fff" stroke="#000" stroke-width=".2"/>
<circle cx="185.3" cy="60.1" r="2.16" fill="#008000" stroke="#008000" stroke-width=".2"/>
<circle cx="185.3" cy="60.1" r="1.65" fill="#fff" stroke="#000" stroke-width=".2"/>
<circle cx="111.7" cy="60.1" r="2.16" fill="#008000" stroke="#008000" stroke-width=".2"/>
<circle cx="111.7" cy="60.1" r="1.65" fill="#fff" stroke="#000" stroke-width=".2"/>
<circle cx="107.9" cy="145.8" r="2.16" fill="#008000" stroke="#008000" stroke-width=".2"/>
<circle cx="107.9" cy="145.8" r="1.65" fill="#fff" stroke="#000" stroke-width=".2"/>
<circle cx="187.8" cy="145.8" r="2.16" fill="#008000" stroke="#008000" stroke-width=".2"/>
<circle cx="187.8" cy="145.8" r="1.65" fill="#fff" stroke="#000" stroke-width=".2"/>
<circle cx="113.6" cy="143.9" r=".51" fill="#008000" stroke="#008000" stroke-width=".2"/>
<circle cx="113.6" cy="143.9" r=".3" fill="#fff" stroke="#000" stroke-width=".2"/>
<circle cx="120.6" cy="145.9" r=".51" fill="#008000" stroke="#008000" stroke-width=".2"/>
<circle cx="120.6" cy="145.9" r=".3" fill="#fff" stroke="#000" stroke-width=".2"/>
<circle cx="127.6" cy="143.9" r=".51" fill="#008000" stroke="#008000" stroke-width=".2"/>
<circle cx="127.6" cy="143.9" r=".3" fill="#fff" stroke="#000" stroke-width=".2"/>
<circle cx="134.6" cy="145.9" r=".51" fill="#008000" stroke="#008000" stroke-width=".2"/>
<circle cx="134.6" cy="145.9" r=".3" fill="#fff" stroke="#000" stroke-width=".2"/>
<circle cx="141.6" cy="143.9" r=".51" fill="#008000" stroke="#008000" stroke-width=".2"/>
<circle cx="141.6" cy="143.9" r=".3" fill="#fff" stroke="#000" stroke-width=".2"/>
<circle cx="148.6" cy="145.9" r=".51" fill="#008000" stroke="#008000" stroke-width=".2"/>
<circle cx="148.6" cy="145.9" r=".3" fill="#fff" stroke="#000" stroke-width=".2"/>
<circle cx="155.6" cy="143.9" r=".51" fill="#008000" stroke="#008000" stroke-width=".2"/>
<circle cx="155.6" cy="143.9" r=".3" fill="#fff" stroke="#000" stroke-width=".2"/>
<circle cx="162.6" cy="145.9" r=".51" fill="#008000" stroke="#008000" stroke-width=".2"/>
<circle cx="162.6" cy="145.9" r=".3" fill="#fff" stroke="#000" stroke-width=".2"/>
<circle cx="169.6" cy="143.9" r=".51" fill="#008000" stroke="#008000" stroke-width=".2"/>
<circle cx="169.6" cy="143.9" r=".3" fill="#fff" stroke="#000" stroke-width=".2"/>
<circle cx="128.6" cy="135.9" r=".51" fill="#008000" stroke="#008000" stroke-width=".2"/>
<circle cx="128.6" cy="135.9" r=".3" fill="#fff" stroke="#000" stroke-width=".2"/>
<circle cx="128" cy="134.7" r=".51" fill="#008000" stroke="#008000" stroke-width=".2"/>
<circle cx="128" cy="134.7" r=".3" fill="#fff" stroke="#000" stroke-width=".2"/>
<circle cx="144.5" cy="134.9" r=".51" fill="#008000" stroke="#008000" stroke-width=".2"/>
<circle cx="144.5" cy="134.9" r=".3" fill="#fff" stroke="#000" stroke-width=".2"/>
<circle cx="145.1" cy="136.2" r=".51" fill="#008000" stroke="#008000" stroke-width=".2"/>
<circle cx="145.1" cy="136.2" r=".3" fill="#fff" stroke="#000" stroke-width=".2"/>
<g fill="none" stroke="#808080" stroke-width=".2">
<path d="M112.7 59.1l-2 2M118 59l-2 2M120.5 59l-2 2M123.1 59l-2 2M125.6 59l-2 2M128.2 59l-2.1 2M130.7 59l-2 2M133.2 59l-2 2M135.8 59l-2 2M138.3 59l-2 2M140.9 59l-2.1 2M143.4 59l-2 2"/>
<path d="M145.9 59l-2 2M148.5 59l-2 2M151 59l-2 2M153.5 59l-2 2M156.1 59l-2 2M158.6 59l-2 2M161.2 59l-2.1 2M163.7 59l-2 2M166.2 59l-2 2M168.8 59l-2 2M171.3 59l-2 2M173.9 59l-2.1 2"/>
<path d="M176.4 59l-2 2M178.9 59l-2 2M181.5 59l-2 2M186.3 59.1l-2 2M105.1 73.2l2.1 2M105.2 68.9v2.2M106.9 68.9v2.2M107.2 73.2l-2.1 2M108.7 68.5h4.9v5.9h-4.9zM109.6 79.3l2 2M111.6 79.3l-2 2M111.8 79.6h5v5.9h-5z"/>
<path d="M112.1 65.3l2.1 2.1M114.2 65.3l-2.1 2.1M114.2 73.7l2 2M116.2 73.7l-2 2M118 61.5l-2 2.1M118 64.1l-2 2M118 66.6l-2 2M118.8 79.6h4.9v5.9h-4.9zM120.5 61.5l-2 2.1M120.5 64.1l-2 2M120.5 66.6l-2 2M123.1 61.5l-2 2.1"/>
<path d="M123.1 64.1l-2 2M123.1 66.6l-2 2M124.9 74.1l2 2.1M124.9 77.9l2 2.1M125.6 61.5l-2 2.1M125.6 64.1l-2 2M125.6 66.6l-2 2M126.2 69.6l2 2M126.2 74.1l2 2.1M126.2 77.9l2 2.1M126.9 74.1l-2 2.1M126.9 77.9l-2 2.1"/>
<path d="M127.4 74.1l2.1 2.1M127.4 77.9l2.1 2.1M128.2 61.5l-2.1 2.1M128.2 64.1l-2.1 2M128.2 66.6l-2.1 2M128.2 69.6l-2 2M128.2 74.1l-2 2.1M128.2 77.9l-2 2.1M128.7 74.1l2.1 2.1M128.7 77.9l2.1 2.1M129.5 74.1l-2.1 2.1M129.5 77.9l-2.1 2.1"/>
<path d="M129.8 69.7l2 2.1M130.7 61.5l-2 2.1M130.7 64.1l-2 2M130.7 66.6l-2 2M130.8 74.1l-2.1 2.1M130.8 77.9l-2.1 2.1M131.8 69.7l-2 2.1M133.2 61.5l-2 2.1M133.2 64.1l-2 2M133.2 66.6l-2 2M134.1 68.9l2 2M135.8 61.5l-2 2.1"/>
<path d="M135.8 64.1l-2 2M135.8 66.6l-2 2M136.1 68.9l-2 2M137.6 68.7l2 2.1M138.3 61.5l-2 2.1M138.3 64.1l-2 2M138.3 66.6l-2 2M139.6 68.7l-2 2.1M140.5 73h1.6v2.8h-1.6zM140.9 61.5l-2.1 2.1M140.9 64.1l-2.1 2M140.9 66.6l-2.1 2"/>
<path d="M141.1 77.7l2.1 2M141.4 68.7l2 2M143.2 77.7l-2.1 2M143.4 61.5l-2 2.1M143.4 64.1l-2 2M143.4 66.6l-2 2M143.4 68.7l-2 2M143.6 79.2v5M143.6 79.2l-.2 .1-.2 .2v4.4l.4 .3M143.6 79.2h3.2l.2 .1 .2 .2v4.4l-.2 .2-.2 .1h-3.2M144.1 74.3l2 2.1M144.3 68.7l2.1 2"/>
<path d="M144.7 79.2a.51 .51 0 0 0 .5 .5 .51 .51 0 0 0 .5-.5M145 73.2l2.1 2M145.1 77.4l2.1 2M145.9 66.6l-2 2M145.9 64.1l-2 2M145.9 61.5l-2 2.1M146.1 74.3l-2 2.1M146.4 68.7l-2.1 2M147.1 73.2l-2.1 2M147.2 77.4l-2.1 2M148.5 66.6l-2.1 2M148.5 64.1l-2.1 2"/>
<path d="M148.5 61.5l-2 2.1M151 61.5l-2 2.1M151 64.1l-2 2M151 66.6l-2 2M151.6 79.7v.7M152.7 72.1l2 2M152.9 79.7v.7M153.5 61.5l-2 2.1M153.5 64.1l-2 2M153.5 66.6l-2 2M154.7 72.1l-2 2M155.3 78.3h2.3"/>
<path d="M155.3 79.9h2.3M155.4 72.1l2.1 2.1M156.1 61.5l-2 2.1M156.1 64.1l-2 2M156.1 66.6l-2 2M156.5 74.3l2 2.1M157.5 72.1l-2.1 2.1M158.5 74.3l-2 2.1M158.6 61.5l-2 2.1M158.6 64.1l-2 2M158.6 66.6l-2 2M161.2 61.5l-2.1 2.1"/>
<path d="M161.2 64.1l-2.1 2M161.2 66.6l-2.1 2M163.7 61.5l-2 2.1M163.7 64.1l-2 2M163.7 66.6l-2 2M163.7 75.6l2.1 2M165.8 75.6l-2.1 2M166.2 61.5l-2 2.1M166.2 64.1l-2 2M166.2 66.6l-2 2M168.8 61.5l-2 2.1M168.8 64.1l-2 2"/>
<path d="M168.8 66.6l-2 2M169.5 79.9h3.1v2.9h-3.1zM171.3 61.5l-2 2.1M171.3 64.1l-2 2M171.3 66.6l-2 2M172.7 78.1l2 2.1M173.8 74.8h2.9v1.6h-2.9zM173.9 61.5l-2.1 2.1M173.9 64.1l-2.1 2M173.9 66.6l-2.1 2M174.7 78.1l-2 2.1M175.2 77.7l2 2"/>
<path d="M176.4 61.5l-2 2.1M176.4 64.1l-2 2M176.4 66.6l-2 2M176.8 72.1l2 2.1M177.2 77.7l-2 2M178.8 72.1l-2 2.1M178.9 61.5l-2 2.1M178.9 64.1l-2 2M178.9 66.6l-2 2M179.1 74.4v2.3M179.1 79.4v2.3M180.8 74.4v2.3"/>
<path d="M180.8 79.4v2.3M181.5 61.5l-2 2.1M181.5 64.1l-2 2M181.5 66.6l-2 2M183.2 74.4v2.3M183.2 79.4v2.3M184.9 74.4v2.3M184.9 79.4v2.3M185.7 64.6l2 2.1M185.7 72.5l2 2M185.9 69.1v2.3M187.6 69.1v2.3"/>
<path d="M187.7 64.6l-2 2.1M187.7 72.5l-2 2M112.6 86.7l2.1 2M114.7 86.7l-2.1 2M120.1 86.9l2.1 2M122.2 86.9l-2.1 2M124.9 94.4l2 2M126.9 94.4l-2 2M127.4 97.3l2.1 2M128.7 81l2 2M129.5 97.3l-2.1 2M130.7 81l-2 2"/>
<path d="M132.7 92.8l2 2M133.4 89.6v2.2M134.7 92.8l-2 2M135.1 89.6v2.2M136.7 91.3v2.3M137.3 82.6l2 2M138.4 91.3v2.3M139 81.3l2 2M139.3 82.6l-2 2M139.3 90.8l2.1 2M140.8 95.5v2.3M141 92.2l2 2"/>
<path d="M141 81.3l-2 2M141.4 90.8l-2.1 2M142.4 95.3l2 2M142.5 95.5v2.3M143 92.2l-2 2M143.7 94.7l2 2.1M144.2 81.3l2 2M144.4 95.3l-2 2M145.7 94.7l-2 2.1M146.1 99.8h2.3M146.2 81.3l-2 2M146.8 91.9l2 2.1"/>
<path d="M147 90.9h4.4v6.5h-4.4zM148.3 89.5l2 2.1M148.8 91.9l-2 2.1M149.4 93.1l2.1 2M149.5 97.8l2 2M150.3 89.5l-2 2.1M150.6 84.5h.8M150.7 85.9h.7M150.9 82.2l2 2.1M151.5 93.1l-2.1 2M151.5 97.8l-2 2M152.6 99.8h2.3"/>
<path d="M152.9 82.2l-2 2.1M153.1 92.3v.8M154.5 92.3v.7M155.3 84h2.2M155.3 85.7h2.2M155.5 92.3v.8M156.8 92.3v.7M157.1 89.7l2 2.1M159.1 89.7l-2 2.1M159.3 81v2.3M161 81v2.3M163.9 88.9h12.5v12.5h-12.5z"/>
<path d="M165.7 84.9h2.3M165.7 86.6h2.3M174.7 83.7l2.1 2M176 81.9l2.1 2.1M176.3 98l2 2.1M176.4 88.1l2.1 2M176.4 91.6l2.1 2M176.8 83.7l-2.1 2M177.7 85.7h3.8v2.4h-3.8zM178.1 81.9l-2.1 2.1M178.3 98l-2 2.1M178.4 85.8v2.2"/>
<path d="M178.5 88.1l-2.1 2M178.5 91.6l-2.1 2M179.4 95l2 2M181.4 95l-2 2M181.5 98l2.1 2M182.1 90h4.8v5.9h-4.8zM183.6 98l-2.1 2M184.1 99.3h2.9v1.7h-2.9zM184.2 96.5l2 2M184.5 84h6.9v4.2h-6.9zM186.2 96.5l-2 2M186.8 94.3l2 2.1"/>
<path d="M188.8 94.3l-2 2.1M189.9 99.3h.7M189.9 94.7h.8M189.9 96h.8M190.1 90.4l2 2M192.1 90.4l-2 2M121.9 104.2l2.1 2M123.4 105.8l2 2.1M124 104.2l-2.1 2M125.4 105.8l-2 2.1M126.2 111.7h2.2M126.2 113.3h2.2"/>
<path d="M126.5 114.9l2 2.1M126.6 117.8v2.2M128.3 117.8v2.2M128.5 114.9l-2 2.1M130 117.8h2.9v1.6h-2.9zM130.5 114.3l2 2M131.8 111.7h2.3M131.8 113.3h2.3M132.2 109.3l2 2.1M132.5 114.3l-2 2M134.2 109.3l-2 2.1M135.3 115.3l2 2"/>
<path d="M135.6 118.6v.8M135.7 110.2l2.1 2M136.9 118.6v.8M137.3 115.3l-2 2M137.4 116.2l2 2.1M137.8 110.2l-2.1 2M139.4 116.2l-2 2.1M139.6 114.6l2.1 2M139.8 117.5v2.3M141.1 111.5h2.2M141.1 113.2h2.2M141.5 117.5v2.3"/>
<path d="M141.7 114.6l-2.1 2M144.2 117.8h2.8v1.6h-2.8zM144.6 113.6l2 2M146.1 101.5h2.3M146.4 111.5h2.3M146.4 113.2h2.3M146.6 113.6l-2 2M146.7 108.1l2 2M148.7 108.1l-2 2M149.5 114.8l2 2M149.8 118.6v.7M151.2 118.5v.8"/>
<path d="M151.5 114.8l-2 2M152.6 101.5h2.3M155.4 115.9l2.1 2M157.5 115.9l-2.1 2M162.8 109.5h4.9v5.9h-4.9zM163 116.9l2 2M163 105.4h3.8v2.4h-3.8zM165 116.9l-2 2M166.1 105.5v2.2M169.9 104.5h6.9v4.2h-6.9zM170.8 113.4v2.3M172.5 113.4v2.3"/>
<path d="M174.2 101.6l2.1 2M176.3 101.6l-2.1 2M177.6 116.7h3.8v2.4h-3.8zM177.8 110.7l2.1 2M178.3 116.8v2.2M178.8 101.9h2.3M178.8 100.2h2.3M179.9 110.7l-2.1 2M180.5 104v2.3M182.2 104v2.3M182.3 102.7l2 2.1M184.3 102.7l-2 2.1"/>
<path d="M184.5 114.7h6.9v4.2h-6.9zM185.3 105.7v2.2M185.8 102.7l2.1 2.1M186.9 105.7v2.2M187.9 102.7l-2.1 2.1M189.9 104.7h.7M189.9 106h.7M189.9 100.7h.7M189.9 107.9h.8M189.9 109.2h.8M121.7 127.9v2.3M121.7 134.6v2.3"/>
<path d="M123.4 127.9v2.3M123.4 134.6v2.3M124.8 128.2l2 2.1M124.8 133.8l2 2M124.8 138l2 2M126.8 133.8h3v3h-3zM126.8 128.2l-2 2.1M126.8 133.8l-2 2M126.8 138l-2 2M127 133.6l2 2.1M127.6 134.9l2 2M127.6 127.9v2.3"/>
<path d="M129 133.6l-2 2.1M129.3 127.9v2.3M129.6 134.9l-2 2M129.8 129.5l2 2.1M130.4 134.9l2 2.1M130.4 131.7l2 2.1M130.7 123.6h2.3M130.7 121.9h2.3M131.8 136.5l2 2M131.8 129.5l-2 2.1M132.4 134.9l-2 2.1M132.4 131.7l-2 2.1"/>
<path d="M132.9 127.5l2 2M133.1 131v2.3M133.8 136.5l-2 2M134.8 131v2.3M134.9 127.5l-2 2M138.3 127.8v2.3M138.3 134.7v2.3M139.9 127.8v2.3M139.9 134.7v2.3M140.7 134l2 2M142 129.3l2.1 2.1M142.7 134l-2 2"/>
<path d="M143.3 134h3v3h-3zM143.5 133.9l2 2M144 135.1l2.1 2.1M144.1 129.3l-2.1 2.1M144.3 127.8v2.3M144.9 123.4h2.3M144.9 121.7h2.3M145.3 123.5l2 2M145.5 133.9l-2 2M145.9 127.8v2.3M146.1 135.1l-2.1 2.1M146.8 135.2l2 2"/>
<path d="M146.8 131.4l2 2M147.3 123.5l-2 2M147.4 127.6l2 2M148.5 136.7l2 2M148.8 135.2l-2 2M148.8 131.4l-2 2M149.4 127.6l-2 2M149.6 130.9v2.3M150.5 136.7l-2 2M151.3 130.9v2.3M156.4 128.5h5.9v4.9h-5.9zM156.5 135.1v2.3"/>
<path d="M158.1 133.9l2 2M158.2 135.1v2.3M160.1 133.9l-2 2M162.6 137.2h3.8v2.4h-3.8zM164 120.3h12.4v12.5h-12.4zM165.7 137.3v2.2M169.9 136.3h6.9v4.2h-6.9zM174.3 133.6l2.1 2M176.3 120.1l2.1 2M176.3 123.4l2.1 2.1M176.4 133.6l-2.1 2M176.4 129.7l2 2"/>
<path d="M178.4 120.1l-2.1 2M178.4 123.4l-2.1 2.1M178.4 129.7l-2 2M178.8 133.6h2.2M178.8 131.9h2.2M179.1 125.9l2.1 2.1M180 136.1v2.3M181.2 125.9l-2.1 2.1M181.3 129.7l2 2M181.7 136.1v2.3M181.7 121.3h4.9v5.9h-4.9zM182.1 133.9l2 2"/>
<path d="M183.3 129.7l-2 2M184 130.6h2.9v1.8h-2.9zM184.1 127.8l2.1 2.1M184.1 133.9l-2 2M185.2 138.1v2.3M185.9 133.9l2.1 2M186.2 127.8l-2.1 2.1M186.7 125.2l2.1 2.1M186.9 138.1v2.3M188 133.9l-2.1 2M188.8 125.2l-2.1 2.1M189.9 136.2h.8"/>
<path d="M189.9 125.6h.8M189.9 130.8h.8M189.9 137.5h.8M189.9 126.9h.8M189.9 132.1h.8M190.1 121.6l2.1 2M192.2 121.6l-2.1 2M108.9 144.8l-2.1 2M112.6 142.9l2 2M114.6 142.9l-2 2M119.6 144.9l2 2M121.6 144.9l-2 2"/>
<path d="M126.6 142.9l2 2M128.6 142.9l-2 2M133.6 144.9l2 2M135.6 144.9l-2 2M140.6 142.9l2 2M142.6 142.9l-2 2M147.6 144.9l2 2M149.6 144.9l-2 2M154.6 142.9l2 2M156.6 142.9l-2 2M161.6 144.9l2 2M163.6 144.9l-2 2"/>
<path d="M168.6 142.9l2 2M170.6 142.9l-2 2M188.8 144.8l-2 2M189.9 140.7h.8M189.9 142h.8"/>
<circle cx="111.7" cy="60.1" r=".99"/>
<circle cx="117" cy="67.6" r=".99"/>
<circle cx="117" cy="65.1" r=".99"/>
<circle cx="117" cy="62.5" r=".99"/>
<circle cx="117" cy="60" r=".99"/>
<circle cx="119.5" cy="60" r=".99"/>
<circle cx="119.5" cy="62.5" r=".99"/>
<circle cx="119.5" cy="67.6" r=".99"/>
<circle cx="119.5" cy="65.1" r=".99"/>
<circle cx="122.1" cy="62.5" r=".99"/>
<circle cx="122.1" cy="67.6" r=".99"/>
<circle cx="122.1" cy="65.1" r=".99"/>
<circle cx="122.1" cy="60" r=".99"/>
<circle cx="124.6" cy="65.1" r=".99"/>
<circle cx="124.6" cy="60" r=".99"/>
<circle cx="124.6" cy="67.6" r=".99"/>
<circle cx="124.6" cy="62.5" r=".99"/>
<circle cx="127.1" cy="67.6" r=".99"/>
<circle cx="127.1" cy="65.1" r=".99"/>
<circle cx="127.1" cy="62.5" r=".99"/>
<circle cx="127.1" cy="60" r=".99"/>
<circle cx="129.7" cy="65.1" r=".99"/>
<circle cx="129.7" cy="67.6" r=".99"/>
<circle cx="129.7" cy="62.5" r=".99"/>
<circle cx="129.7" cy="60" r=".99"/>
<circle cx="132.2" cy="62.5" r=".99"/>
<circle cx="132.2" cy="60" r=".99"/>
<circle cx="132.2" cy="67.6" r=".99"/>
<circle cx="132.2" cy="65.1" r=".99"/>
<circle cx="134.8" cy="62.5" r=".99"/>
<circle cx="134.8" cy="67.6" r=".99"/>
<circle cx="134.8" cy="65.1" r=".99"/>
<circle cx="134.8" cy="60" r=".99"/>
<circle cx="137.3" cy="62.5" r=".99"/>
<circle cx="137.3" cy="65.1" r=".99"/>
<circle cx="137.3" cy="67.6" r=".99"/>
<circle cx="137.3" cy="60" r=".99"/>
<circle cx="139.8" cy="67.6" r=".99"/>
<circle cx="139.8" cy="62.5" r=".99"/>
<circle cx="139.8" cy="60" r=".99"/>
<circle cx="139.8" cy="65.1" r=".99"/>
<circle cx="142.4" cy="67.6" r=".99"/>
<circle cx="142.4" cy="62.5" r=".99"/>
<circle cx="142.4" cy="60" r=".99"/>
<circle cx="142.4" cy="65.1" r=".99"/>
<circle cx="144.9" cy="62.5" r=".99"/>
<circle cx="144.9" cy="60" r=".99"/>
<circle cx="144.9" cy="67.6" r=".99"/>
<circle cx="144.9" cy="65.1" r=".99"/>
<circle cx="147.4" cy="67.6" r=".99"/>
<circle cx="147.4" cy="65.1" r=".99"/>
<circle cx="147.5" cy="62.5" r=".99"/>
<circle cx="147.5" cy="60" r=".99"/>
<circle cx="150" cy="62.5" r=".99"/>
<circle cx="150" cy="60" r=".99"/>
<circle cx="150" cy="67.6" r=".99"/>
<circle cx="150" cy="65.1" r=".99"/>
<circle cx="152.5" cy="62.5" r=".99"/>
<circle cx="152.5" cy="65.1" r=".99"/>
<circle cx="152.5" cy="67.6" r=".99"/>
<circle cx="152.5" cy="60" r=".99"/>
<circle cx="155.1" cy="65.1" r=".99"/>
<circle cx="155.1" cy="67.6" r=".99"/>
<circle cx="155.1" cy="62.5" r=".99"/>
<circle cx="155.1" cy="60" r=".99"/>
<circle cx="157.6" cy="65.1" r=".99"/>
<circle cx="157.6" cy="67.6" r=".99"/>
<circle cx="157.6" cy="62.5" r=".99"/>
<circle cx="157.6" cy="60" r=".99"/>
<circle cx="160.1" cy="60" r=".99"/>
<circle cx="160.1" cy="67.6" r=".99"/>
<circle cx="160.1" cy="62.5" r=".99"/>
<circle cx="160.1" cy="65.1" r=".99"/>
<circle cx="162.7" cy="62.5" r=".99"/>
<circle cx="162.7" cy="60" r=".99"/>
<circle cx="162.7" cy="67.6" r=".99"/>
<circle cx="162.7" cy="65.1" r=".99"/>
<circle cx="165.2" cy="67.6" r=".99"/>
<circle cx="165.2" cy="62.5" r=".99"/>
<circle cx="165.2" cy="60" r=".99"/>
<circle cx="165.2" cy="65.1" r=".99"/>
<circle cx="167.8" cy="67.6" r=".99"/>
<circle cx="167.8" cy="62.5" r=".99"/>
<circle cx="167.8" cy="65.1" r=".99"/>
<circle cx="167.8" cy="60" r=".99"/>
<circle cx="170.3" cy="65.1" r=".99"/>
<circle cx="170.3" cy="62.5" r=".99"/>
<circle cx="170.3" cy="60" r=".99"/>
<circle cx="170.3" cy="67.6" r=".99"/>
<circle cx="172.8" cy="65.1" r=".99"/>
<circle cx="172.8" cy="67.6" r=".99"/>
<circle cx="172.8" cy="60" r=".99"/>
<circle cx="172.8" cy="62.5" r=".99"/>
<circle cx="175.4" cy="62.5" r=".99"/>
<circle cx="175.4" cy="60" r=".99"/>
<circle cx="175.4" cy="65.1" r=".99"/>
<circle cx="175.4" cy="67.6" r=".99"/>
<circle cx="177.9" cy="67.6" r=".99"/>
<circle cx="177.9" cy="65.1" r=".99"/>
<circle cx="177.9" cy="62.5" r=".99"/>
<circle cx="177.9" cy="60" r=".99"/>
<circle cx="180.5" cy="60" r=".99"/>
<circle cx="180.5" cy="62.5" r=".99"/>
<circle cx="180.5" cy="67.6" r=".99"/>
<circle cx="180.5" cy="65.1" r=".99"/>
<circle cx="185.3" cy="60.1" r=".99"/>
<circle cx="107.9" cy="145.8" r=".99"/>
<circle cx="187.8" cy="145.8" r=".99"/>
</g>
<g fill="#808080" stroke="#808080" stroke-width=".2">
<path d="M143.4 134.1h.2v.2h-.2z" fill-rule="evenodd"/>
<path d="M127 133.9h.1v.2h-.1z" fill-rule="evenodd"/>
<path d="M182.2 95.5h.2v.2h-.2l.2-.1h-.2z" fill-rule="evenodd"/>
<path d="M181.9 126.8h.2v.2h-.2l-.1-.1h.2h-.2z" fill-rule="evenodd"/>
<path d="M113.2 68.7h.2v.2h-.2v-.1h.1h-.1z" fill-rule="evenodd"/>
<path d="M156.6 128.7h.2v.2h-.2v-.1h.1h-.1z" fill-rule="evenodd"/>
<path d="M184.4 100.4h.3v.3h-.3v-.2h.3l-.2 .1-.1-.1z" fill-rule="evenodd"/>
<path d="M184.3 131.7h.3v.4l-.3-.1v-.1l.3-.1-.2 .2-.1-.1z" fill-rule="evenodd"/>
<path d="M112 85h.2v.3h-.2v-.1l.2-.1-.2 .1z" fill-rule="evenodd"/>
<path d="M119 85h.2v.3h-.2v-.1l.1-.1-.1 .1z" fill-rule="evenodd"/>
<path d="M150.7 96.8h.3l.1 .2-.4 .1v-.1l.2-.1-.2 .1z" fill-rule="evenodd"/>
<path d="M171.6 82.1a.35 .35 0 0 1 .6-.1 .35 .35 0 0 1-.1 .6 .35 .35 0 0 1-.5-.3h.1a.22 .22 0 0 1 .4-.2 .22 .22 0 0 1 0 .3l-.5-.1z" fill-rule="evenodd"/>
<path d="M163 115h.2v.2h-.2l-.1-.1h.2h-.2z" fill-rule="evenodd"/>
</g>
<g fill="#808080" stroke="#808080" stroke-width=".2">
<path d="M185.2 107.9h1.8v.6h-1.8z"/>
<path d="M185.2 105.1h1.8v.6h-1.8z"/>
<path d="M180.5 106.3h1.8v.5h-1.8z"/>
<path d="M180.5 103.4h1.8v.6h-1.8z"/>
<path d="M185.1 140.3h1.8v.6h-1.8z"/>
<path d="M185.1 137.5h1.8v.6h-1.8z"/>
<path d="M179.9 138.4h1.8v.6h-1.8z"/>
<path d="M179.9 135.6h1.8v.6h-1.8z"/>
<path d="M181 131.8h.6v1.9h-.6z"/>
<path d="M178.2 131.8h.6v1.9h-.6z"/>
<path d="M181.1 100.1h.6v1.9h-.6z"/>
<path d="M178.2 100.1h.6v1.9h-.6z"/>
<path d="M149.5 130.3h1.8v.6h-1.8z"/>
<path d="M149.5 133.1h1.8v.6h-1.8z"/>
<path d="M144.2 127.2h1.8v.6h-1.8z"/>
<path d="M144.2 130h1.8v.6h-1.8z"/>
<path d="M138.2 134.1h1.8v.6h-1.8z"/>
<path d="M138.2 137h1.8v.6h-1.8z"/>
<path d="M138.2 127.2h1.8v.6h-1.8z"/>
<path d="M138.2 130h1.8v.6h-1.8z"/>
<path d="M133 130.4h1.9v.6h-1.9z"/>
<path d="M133 133.2h1.9v.6h-1.9z"/>
<path d="M127.6 127.3h1.8v.6h-1.8z"/>
<path d="M127.6 130.2h1.8v.6h-1.8z"/>
<path d="M121.6 134h1.8v.6h-1.8z"/>
<path d="M121.6 136.9h1.8v.6h-1.8z"/>
<path d="M121.6 127.3h1.8v.6h-1.8z"/>
<path d="M121.6 130.2h1.8v.5h-1.8z"/>
<path d="M105.2 68.3h1.8v.6h-1.8z"/>
<path d="M105.2 71.1h1.8v.6h-1.8z"/>
<path d="M189.2 107.9h.8v1.4h-.8z"/>
<path d="M190.6 107.9h.8v1.4h-.8z"/>
<path d="M189.2 104.6h.7v1.5h-.7z"/>
<path d="M190.6 104.6h.8v1.5h-.8z"/>
<path d="M189.2 94.6h.7v1.5h-.7z"/>
<path d="M190.6 94.6h.8v1.5h-.8z"/>
<path d="M191.4 84.9h.2v2.4h-.2z"/>
<path d="M184.3 84.9h.1v2.4h-.1z"/>
<path d="M184.8 84h.5v4.2h-.5z"/>
<path d="M189.2 140.6h.7v1.4h-.7z"/>
<path d="M190.6 140.6h.8v1.4h-.8z"/>
<path d="M189.2 136.1h.7v1.5h-.7z"/>
<path d="M190.6 136.1h.8v1.5h-.8z"/>
<path d="M189.2 125.5h.8v1.5h-.8z"/>
<path d="M190.7 125.5h.7v1.5h-.7z"/>
<path d="M191.4 115.6h.2v2.4h-.2z"/>
<path d="M184.3 115.6h.2v2.4h-.2z"/>
<path d="M184.8 114.7h.5v4.2h-.5z"/>
<path d="M156.4 134.6h1.8v.6h-1.8z"/>
<path d="M156.4 137.4h1.8v.6h-1.8z"/>
<path d="M189.2 130.7h.8v1.5h-.8z"/>
<path d="M190.6 130.7h.8v1.5h-.8z"/>
<path d="M189.2 99.3h.7v1.4h-.7z"/>
<path d="M190.6 99.3h.8v1.4h-.8z"/>
<path d="M176.8 105.4h.2v2.4h-.2z"/>
<path d="M169.7 105.4h.2v2.4h-.2z"/>
<path d="M170.2 104.5h.5v4.2h-.5z"/>
<path d="M176.9 137.2h.1v2.4h-.1z"/>
<path d="M169.7 137.2h.2v2.4h-.2z"/>
<path d="M170.2 136.3h.5v4.2h-.5z"/>
<path d="M147.2 83.4h1.1v.5h-1.1z"/>
<path d="M142.1 79.5h1.1v.6h-1.1z"/>
<path d="M142.1 80.8h1.1v.5h-1.1z"/>
<path d="M142.1 82.1h1.2v.5h-1.2z"/>
<path d="M142.1 83.4h1.1v.5h-1.1z"/>
<path d="M147.2 82.1h1.1v.5h-1.1z"/>
<path d="M147.2 80.8h1.1v.5h-1.1z"/>
<path d="M147.2 79.5h1.1v.6h-1.1z"/>
<path d="M159.3 80.4h1.8v.6h-1.8z"/>
<path d="M159.3 83.2h1.8v.6h-1.8z"/>
<path d="M154.7 83.9h.6v1.9h-.6z"/>
<path d="M157.5 83.9h.6v1.9h-.6z"/>
<path d="M154.7 78.2h.6v1.8h-.6z"/>
<path d="M157.5 78.2h.6v1.8h-.6z"/>
<path d="M151.5 80.4h1.5v.8h-1.5z"/>
<path d="M151.5 79h1.5v.7h-1.5z"/>
<path d="M149.9 84.5h.8v1.4h-.8z"/>
<path d="M151.4 84.5h.7v1.4h-.7z"/>
<path d="M132.2 117.1h.5v.7h-.5z"/>
<path d="M131.2 117.1h.5v.7h-.5z"/>
<path d="M130.3 117.1h.5v.7h-.5z"/>
<path d="M130.3 119.5h.5v.6h-.5z"/>
<path d="M132.2 119.5h.5v.6h-.5z"/>
<path d="M125.6 111.6h.6v1.8h-.6z"/>
<path d="M128.4 111.6h.6v1.8h-.6z"/>
<path d="M126.6 120h1.8v.6h-1.8z"/>
<path d="M126.6 117.2h1.8v.6h-1.8z"/>
<path d="M133 121.9h.6v1.8h-.6z"/>
<path d="M130.2 121.9h.6v1.8h-.6z"/>
<path d="M134 111.6h.6v1.8h-.6z"/>
<path d="M131.2 111.6h.6v1.8h-.6z"/>
<path d="M135.6 117.9h1.4v.7h-1.4z"/>
<path d="M135.6 119.3h1.4v.8h-1.4z"/>
<path d="M142.2 75.1h.6v.5h-.6z"/>
<path d="M142.2 74.1h.6v.6h-.6z"/>
<path d="M142.2 73.2h.6v.5h-.6z"/>
<path d="M139.8 73.2h.7v.5h-.7z"/>
<path d="M139.8 75.1h.7v.5h-.7z"/>
<path d="M146.3 117.1h.5v.6h-.5z"/>
<path d="M145.4 117.1h.5v.6h-.5z"/>
<path d="M144.4 117.1h.5v.6h-.5z"/>
<path d="M144.4 119.4h.5v.7h-.5z"/>
<path d="M146.3 119.4h.5v.7h-.5z"/>
<path d="M140.5 111.4h.6v1.9h-.6z"/>
<path d="M143.3 111.4h.6v1.9h-.6z"/>
<path d="M139.7 119.8h1.9v.6h-1.9z"/>
<path d="M139.7 117h1.9v.6h-1.9z"/>
<path d="M147.2 121.6h.6v1.8h-.6z"/>
<path d="M144.4 121.6h.6v1.8h-.6z"/>
<path d="M148.6 111.4h.6v1.9h-.6z"/>
<path d="M145.8 111.4h.6v1.9h-.6z"/>
<path d="M149.8 117.8h1.4v.8h-1.4z"/>
<path d="M149.8 119.3h1.4v.7h-1.4z"/>
<path d="M155.5 93h1.4v.8h-1.4z"/>
<path d="M155.5 91.6h1.4v.8h-1.4z"/>
<path d="M153.1 93h1.4v.8h-1.4z"/>
<path d="M153.1 91.6h1.4v.8h-1.4z"/>
<path d="M140.7 97.8h1.8v.6h-1.8z"/>
<path d="M140.7 95h1.8v.6h-1.8z"/>
<path d="M179 78.8h1.9v.6h-1.9z"/>
<path d="M179 81.6h1.9v.6h-1.9z"/>
<path d="M183.1 78.8h1.8v.6h-1.8z"/>
<path d="M183.1 81.6h1.8v.6h-1.8z"/>
<path d="M183.1 73.9h1.8v.6h-1.8z"/>
<path d="M183.1 76.7h1.8v.6h-1.8z"/>
<path d="M179 73.9h1.9v.6h-1.9z"/>
<path d="M179 76.7h1.9v.6h-1.9z"/>
<path d="M148.4 99.7h.5v1.8h-.5z"/>
<path d="M145.5 99.7h.6v1.8h-.6z"/>
<path d="M154.9 99.7h.5v1.8h-.5z"/>
<path d="M152 99.7h.6v1.8h-.6z"/>
<path d="M136.6 90.7h1.9v.6h-1.9z"/>
<path d="M136.6 93.6h1.9v.5h-1.9z"/>
<path d="M133.3 91.8h1.8v.6h-1.8z"/>
<path d="M133.3 89h1.8v.6h-1.8z"/>
<path d="M176 74.1h.5v.7h-.5z"/>
<path d="M175 74.1h.5v.7h-.5z"/>
<path d="M174.1 74.1h.5v.7h-.5z"/>
<path d="M174.1 76.5h.5v.6h-.5z"/>
<path d="M176 76.5h.5v.6h-.5z"/>
<path d="M165.1 84.9h.6v1.8h-.6z"/>
<path d="M167.9 84.9h.6v1.8h-.6z"/>
<path d="M185.8 71.4h1.8v.6h-1.8z"/>
<path d="M185.8 68.6h1.8v.6h-1.8z"/>
<path d="M170.8 112.8h1.8v.6h-1.8z"/>
<path d="M170.8 115.6h1.8v.6h-1.8z"/>
</g>
<g fill="none" stroke="#000" stroke-width=".2">
<path d="M105.6 70h1M106.1 69.5v1M110.5 71.4h1.4M111.2 70.7v1.5M140.6 74.4h1.5M141.3 73.7v1.4M143.9 61.3h2M143.9 66.4h2M144.9 60.3v2M144.9 65.3v2.1M152.2 79.5v1.1M155.9 79.1h1"/>
<path d="M156.4 78.6v1M174.5 75.6h1.5M175.3 74.9v1.4M179.5 75.6h1M180 75.1v1M183.5 75.6h1M184 75.1v1M186.2 70.3h1M186.7 69.8v1M113.6 82.5h1.4M114.3 81.8v1.4M114.5 95a5.5 5.5 0 0 1 5.5 5.5 5.5 5.5 0 0 1-5.6 5.4"/>
<path d="M114.6 94.9h-12v-37.8h90.4v91.8h-90.4v-9.5h12M120.5 82.5h1.5M121.3 81.8v1.4M133.6 90.7h1.3M134.2 90.1v1.2M136.9 92.4h1.3M137.5 91.8v1.2M141.1 96.7h1.1M141.6 96.1v1.1M144.2 81.7h2M145.2 80.7v2M148.4 94.2h1.5"/>
<path d="M149.2 93.4v1.5M150.4 85.2h1.2M151 84.6v1.2M151.7 80.1h1.1M153.2 92.7h1.2M153.8 92.1v1.2M155.7 92.7h.9M155.9 84.9h1M156.2 92.2v.9M156.4 84.4v1M159.6 82.1h1.1M160.2 81.6v1"/>
<path d="M166.3 85.8h1M166.8 85.3v1M169.1 95.1h2.1M170.2 94.1v2.1M170.3 81.4h1.5M171 80.6v1.5M178.8 86.9h1.7M179.5 80.5h1M179.6 86v1.7M180 80v1M183.5 80.5h1M183.8 93h1.4"/>
<path d="M184 80v1M184.5 92.3v1.4M185.5 99.5v1.3M187.1 86.1h1.6M187.9 85.3v1.6M189.7 95.4h1.2M189.7 100h1.1M190.3 99.4v1.2M190.3 94.7v1.2M114.6 105.9h-12v22.5h12M126.7 112.5h1.1M126.9 118.9h1.1"/>
<path d="M127.3 111.9v1.2M127.5 118.3v1.2M130.7 118.6h1.5M131.5 117.9v1.5M132.4 112.5h1M132.9 112v1M135.7 119h1.1M136.3 118.4v1.1M140.1 118.7h1.1M140.7 118.1v1.2M141.6 112.4h1.2M142.2 111.8v1.1"/>
<path d="M144.9 118.6h1.4M145.6 117.9v1.4M146.6 100.6h1.2M147 112.4h1M147.3 100v1.2M147.5 111.8v1.1M149.9 118.9h1.2M150.5 118.3v1.2M153.1 100.6h1.2M153.7 100v1.2M164.1 106.6h1.7M164.5 112.5h1.4"/>
<path d="M164.9 105.7v1.7M165.2 111.8v1.4M171.2 114.5h1M171.7 114v1M172.6 106.6h1.6M173.4 105.7v1.7M178.7 117.9h1.7M179.3 101h1.3M179.5 117.1v1.7M180 100.4v1.2M180.9 105.1h1M181.4 104.6v1"/>
<path d="M184.9 100.2h1.3M185.5 106.8h1.2M186.1 106.2v1.2M187.1 116.8h1.7M188 116v1.6M189.7 108.6h1.2M189.7 105.3h1.1M190.3 104.8v1.1M190.3 108v1.2M114.5 128.4a5.5 5.5 0 0 1 5.5 5.5 5.5 5.5 0 0 1-5.6 5.5M121.9 129.1h1.2M121.9 135.8h1.2"/>
<path d="M122.5 128.4v1.2M122.5 135.1v1.3M127.7 135.3h1.1M128 129.1h1M128.3 134.7v1.1M128.5 128.5v1.1M131.3 122.8h1.2M131.9 122.2v1.1M133.4 132.1h1.1M133.9 131.6v1.1M138.5 128.9h1.2M138.5 135.8h1.2"/>
<path d="M139.1 128.3v1.2M139.1 135.3v1.1M144.2 135.5h1.1M144.6 128.9h1M144.8 135v1.1M145.1 128.4v1M145.5 122.5h1.2M146.1 122v1.1M149.9 132h1.1M150.4 131.4v1.2M156.8 136.3h1M157.3 135.8v1"/>
<path d="M158.6 131h1.4M159.3 130.2v1.5M163.6 138.4h1.8M164.5 137.5v1.8M169.2 126.5h2M170.2 125.5v2.1M172.6 138.4h1.6M173.4 137.6v1.6M179.3 132.8h1.2M179.9 132.2v1.2M180.3 137.3h1M180.8 136.8v1"/>
<path d="M183.4 124.3h1.5M184.1 123.6v1.4M184.8 131.5h1.4M185.4 139.2h1.2M185.5 130.8v1.4M186 138.6v1.2M189.7 136.8h1.2M189.7 126.3h1.2M189.7 131.4h1.2M190.3 136.2v1.3M190.3 125.7v1.2M190.3 130.9v1.1"/>
<path d="M142.2 144.9h.8M142.6 144.5v.8M189.7 141.3h1.2M190.3 140.7v1.2"/>
</g>
<g fill="none" stroke="#808000" stroke-width=".2">
<path d="M119.4 79.6h3.8M142.4 69.7h.1M126.8 96.7v.1M152 85.2h-.1M153.7 91.7l.1 .1M128.7 112.5h.1M131.5 112.5h.1M136.2 119.9h.1M145.8 100.6h.1M183.5 100l1.1 1.5M129.6 136.3h.1M143.5 136.5h.1"/>
<path d="M184.1 125h.1M189.4 126.3h.1"/>
</g>
<use href="#words"/>
</svg>
